VERSION 5.8 ;
BUSBITCHARS "[]" ;
DIVIDERCHAR "/" ;
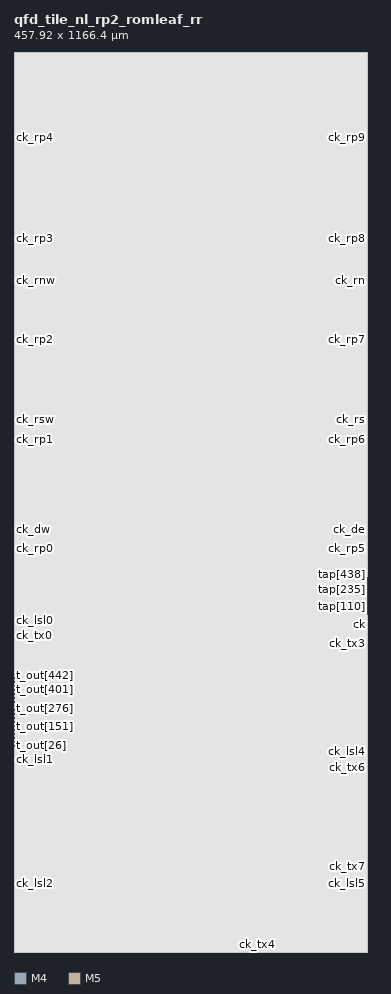
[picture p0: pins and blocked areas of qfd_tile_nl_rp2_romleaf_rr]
MACRO qfd_tile_nl_rp2_romleaf_rr
  CLASS BLOCK ;
  ORIGIN 0 0 ;
  FOREIGN qfd_tile_nl_rp2_romleaf_rr 0 0 ;
  SIZE 457.92 BY 1166.4 ;
  SYMMETRY X Y ;
  PIN t_out[0]
    DIRECTION OUTPUT ;
    USE SIGNAL ;
    PORT
      LAYER M4 ;
        RECT 0.000 262.752 0.192 262.776 ;
    END
  END t_out[0]
  PIN t_out[1]
    DIRECTION OUTPUT ;
    USE SIGNAL ;
    PORT
      LAYER M4 ;
        RECT 0.000 262.944 0.192 262.968 ;
    END
  END t_out[1]
  PIN t_out[2]
    DIRECTION OUTPUT ;
    USE SIGNAL ;
    PORT
      LAYER M4 ;
        RECT 0.000 263.136 0.192 263.160 ;
    END
  END t_out[2]
  PIN t_out[3]
    DIRECTION OUTPUT ;
    USE SIGNAL ;
    PORT
      LAYER M4 ;
        RECT 0.000 263.328 0.192 263.352 ;
    END
  END t_out[3]
  PIN t_out[4]
    DIRECTION OUTPUT ;
    USE SIGNAL ;
    PORT
      LAYER M4 ;
        RECT 0.000 263.520 0.192 263.544 ;
    END
  END t_out[4]
  PIN t_out[5]
    DIRECTION OUTPUT ;
    USE SIGNAL ;
    PORT
      LAYER M4 ;
        RECT 0.000 263.712 0.192 263.736 ;
    END
  END t_out[5]
  PIN t_out[6]
    DIRECTION OUTPUT ;
    USE SIGNAL ;
    PORT
      LAYER M4 ;
        RECT 0.000 263.904 0.192 263.928 ;
    END
  END t_out[6]
  PIN t_out[7]
    DIRECTION OUTPUT ;
    USE SIGNAL ;
    PORT
      LAYER M4 ;
        RECT 0.000 264.096 0.192 264.120 ;
    END
  END t_out[7]
  PIN t_out[8]
    DIRECTION OUTPUT ;
    USE SIGNAL ;
    PORT
      LAYER M4 ;
        RECT 0.000 264.288 0.192 264.312 ;
    END
  END t_out[8]
  PIN t_out[9]
    DIRECTION OUTPUT ;
    USE SIGNAL ;
    PORT
      LAYER M4 ;
        RECT 0.000 264.480 0.192 264.504 ;
    END
  END t_out[9]
  PIN t_out[10]
    DIRECTION OUTPUT ;
    USE SIGNAL ;
    PORT
      LAYER M4 ;
        RECT 0.000 264.672 0.192 264.696 ;
    END
  END t_out[10]
  PIN t_out[11]
    DIRECTION OUTPUT ;
    USE SIGNAL ;
    PORT
      LAYER M4 ;
        RECT 0.000 264.864 0.192 264.888 ;
    END
  END t_out[11]
  PIN t_out[12]
    DIRECTION OUTPUT ;
    USE SIGNAL ;
    PORT
      LAYER M4 ;
        RECT 0.000 265.056 0.192 265.080 ;
    END
  END t_out[12]
  PIN t_out[13]
    DIRECTION OUTPUT ;
    USE SIGNAL ;
    PORT
      LAYER M4 ;
        RECT 0.000 265.248 0.192 265.272 ;
    END
  END t_out[13]
  PIN t_out[14]
    DIRECTION OUTPUT ;
    USE SIGNAL ;
    PORT
      LAYER M4 ;
        RECT 0.000 265.440 0.192 265.464 ;
    END
  END t_out[14]
  PIN t_out[15]
    DIRECTION OUTPUT ;
    USE SIGNAL ;
    PORT
      LAYER M4 ;
        RECT 0.000 265.632 0.192 265.656 ;
    END
  END t_out[15]
  PIN t_out[16]
    DIRECTION OUTPUT ;
    USE SIGNAL ;
    PORT
      LAYER M4 ;
        RECT 0.000 265.824 0.192 265.848 ;
    END
  END t_out[16]
  PIN t_out[17]
    DIRECTION OUTPUT ;
    USE SIGNAL ;
    PORT
      LAYER M4 ;
        RECT 0.000 266.016 0.192 266.040 ;
    END
  END t_out[17]
  PIN t_out[18]
    DIRECTION OUTPUT ;
    USE SIGNAL ;
    PORT
      LAYER M4 ;
        RECT 0.000 266.208 0.192 266.232 ;
    END
  END t_out[18]
  PIN t_out[19]
    DIRECTION OUTPUT ;
    USE SIGNAL ;
    PORT
      LAYER M4 ;
        RECT 0.000 266.400 0.192 266.424 ;
    END
  END t_out[19]
  PIN t_out[20]
    DIRECTION OUTPUT ;
    USE SIGNAL ;
    PORT
      LAYER M4 ;
        RECT 0.000 266.592 0.192 266.616 ;
    END
  END t_out[20]
  PIN t_out[21]
    DIRECTION OUTPUT ;
    USE SIGNAL ;
    PORT
      LAYER M4 ;
        RECT 0.000 266.784 0.192 266.808 ;
    END
  END t_out[21]
  PIN t_out[22]
    DIRECTION OUTPUT ;
    USE SIGNAL ;
    PORT
      LAYER M4 ;
        RECT 0.000 266.976 0.192 267.000 ;
    END
  END t_out[22]
  PIN t_out[23]
    DIRECTION OUTPUT ;
    USE SIGNAL ;
    PORT
      LAYER M4 ;
        RECT 0.000 267.168 0.192 267.192 ;
    END
  END t_out[23]
  PIN t_out[24]
    DIRECTION OUTPUT ;
    USE SIGNAL ;
    PORT
      LAYER M4 ;
        RECT 0.000 267.360 0.192 267.384 ;
    END
  END t_out[24]
  PIN t_out[25]
    DIRECTION OUTPUT ;
    USE SIGNAL ;
    PORT
      LAYER M4 ;
        RECT 0.000 267.552 0.192 267.576 ;
    END
  END t_out[25]
  PIN t_out[26]
    DIRECTION OUTPUT ;
    USE SIGNAL ;
    PORT
      LAYER M4 ;
        RECT 0.000 267.744 0.192 267.768 ;
    END
  END t_out[26]
  PIN t_out[27]
    DIRECTION OUTPUT ;
    USE SIGNAL ;
    PORT
      LAYER M4 ;
        RECT 0.000 267.936 0.192 267.960 ;
    END
  END t_out[27]
  PIN t_out[28]
    DIRECTION OUTPUT ;
    USE SIGNAL ;
    PORT
      LAYER M4 ;
        RECT 0.000 268.128 0.192 268.152 ;
    END
  END t_out[28]
  PIN t_out[29]
    DIRECTION OUTPUT ;
    USE SIGNAL ;
    PORT
      LAYER M4 ;
        RECT 0.000 268.320 0.192 268.344 ;
    END
  END t_out[29]
  PIN t_out[30]
    DIRECTION OUTPUT ;
    USE SIGNAL ;
    PORT
      LAYER M4 ;
        RECT 0.000 268.512 0.192 268.536 ;
    END
  END t_out[30]
  PIN t_out[31]
    DIRECTION OUTPUT ;
    USE SIGNAL ;
    PORT
      LAYER M4 ;
        RECT 0.000 268.704 0.192 268.728 ;
    END
  END t_out[31]
  PIN t_out[32]
    DIRECTION OUTPUT ;
    USE SIGNAL ;
    PORT
      LAYER M4 ;
        RECT 0.000 268.896 0.192 268.920 ;
    END
  END t_out[32]
  PIN t_out[33]
    DIRECTION OUTPUT ;
    USE SIGNAL ;
    PORT
      LAYER M4 ;
        RECT 0.000 269.088 0.192 269.112 ;
    END
  END t_out[33]
  PIN t_out[34]
    DIRECTION OUTPUT ;
    USE SIGNAL ;
    PORT
      LAYER M4 ;
        RECT 0.000 269.280 0.192 269.304 ;
    END
  END t_out[34]
  PIN t_out[35]
    DIRECTION OUTPUT ;
    USE SIGNAL ;
    PORT
      LAYER M4 ;
        RECT 0.000 269.472 0.192 269.496 ;
    END
  END t_out[35]
  PIN t_out[36]
    DIRECTION OUTPUT ;
    USE SIGNAL ;
    PORT
      LAYER M4 ;
        RECT 0.000 269.664 0.192 269.688 ;
    END
  END t_out[36]
  PIN t_out[37]
    DIRECTION OUTPUT ;
    USE SIGNAL ;
    PORT
      LAYER M4 ;
        RECT 0.000 269.856 0.192 269.880 ;
    END
  END t_out[37]
  PIN t_out[38]
    DIRECTION OUTPUT ;
    USE SIGNAL ;
    PORT
      LAYER M4 ;
        RECT 0.000 270.048 0.192 270.072 ;
    END
  END t_out[38]
  PIN t_out[39]
    DIRECTION OUTPUT ;
    USE SIGNAL ;
    PORT
      LAYER M4 ;
        RECT 0.000 270.240 0.192 270.264 ;
    END
  END t_out[39]
  PIN t_out[40]
    DIRECTION OUTPUT ;
    USE SIGNAL ;
    PORT
      LAYER M4 ;
        RECT 0.000 270.432 0.192 270.456 ;
    END
  END t_out[40]
  PIN t_out[41]
    DIRECTION OUTPUT ;
    USE SIGNAL ;
    PORT
      LAYER M4 ;
        RECT 0.000 270.624 0.192 270.648 ;
    END
  END t_out[41]
  PIN t_out[42]
    DIRECTION OUTPUT ;
    USE SIGNAL ;
    PORT
      LAYER M4 ;
        RECT 0.000 270.816 0.192 270.840 ;
    END
  END t_out[42]
  PIN t_out[43]
    DIRECTION OUTPUT ;
    USE SIGNAL ;
    PORT
      LAYER M4 ;
        RECT 0.000 271.008 0.192 271.032 ;
    END
  END t_out[43]
  PIN t_out[44]
    DIRECTION OUTPUT ;
    USE SIGNAL ;
    PORT
      LAYER M4 ;
        RECT 0.000 271.200 0.192 271.224 ;
    END
  END t_out[44]
  PIN t_out[45]
    DIRECTION OUTPUT ;
    USE SIGNAL ;
    PORT
      LAYER M4 ;
        RECT 0.000 271.392 0.192 271.416 ;
    END
  END t_out[45]
  PIN t_out[46]
    DIRECTION OUTPUT ;
    USE SIGNAL ;
    PORT
      LAYER M4 ;
        RECT 0.000 271.584 0.192 271.608 ;
    END
  END t_out[46]
  PIN t_out[47]
    DIRECTION OUTPUT ;
    USE SIGNAL ;
    PORT
      LAYER M4 ;
        RECT 0.000 271.776 0.192 271.800 ;
    END
  END t_out[47]
  PIN t_out[48]
    DIRECTION OUTPUT ;
    USE SIGNAL ;
    PORT
      LAYER M4 ;
        RECT 0.000 271.968 0.192 271.992 ;
    END
  END t_out[48]
  PIN t_out[49]
    DIRECTION OUTPUT ;
    USE SIGNAL ;
    PORT
      LAYER M4 ;
        RECT 0.000 272.160 0.192 272.184 ;
    END
  END t_out[49]
  PIN t_out[50]
    DIRECTION OUTPUT ;
    USE SIGNAL ;
    PORT
      LAYER M4 ;
        RECT 0.000 272.352 0.192 272.376 ;
    END
  END t_out[50]
  PIN t_out[51]
    DIRECTION OUTPUT ;
    USE SIGNAL ;
    PORT
      LAYER M4 ;
        RECT 0.000 272.544 0.192 272.568 ;
    END
  END t_out[51]
  PIN t_out[52]
    DIRECTION OUTPUT ;
    USE SIGNAL ;
    PORT
      LAYER M4 ;
        RECT 0.000 272.736 0.192 272.760 ;
    END
  END t_out[52]
  PIN t_out[53]
    DIRECTION OUTPUT ;
    USE SIGNAL ;
    PORT
      LAYER M4 ;
        RECT 0.000 272.928 0.192 272.952 ;
    END
  END t_out[53]
  PIN t_out[54]
    DIRECTION OUTPUT ;
    USE SIGNAL ;
    PORT
      LAYER M4 ;
        RECT 0.000 273.120 0.192 273.144 ;
    END
  END t_out[54]
  PIN t_out[55]
    DIRECTION OUTPUT ;
    USE SIGNAL ;
    PORT
      LAYER M4 ;
        RECT 0.000 273.312 0.192 273.336 ;
    END
  END t_out[55]
  PIN t_out[56]
    DIRECTION OUTPUT ;
    USE SIGNAL ;
    PORT
      LAYER M4 ;
        RECT 0.000 273.504 0.192 273.528 ;
    END
  END t_out[56]
  PIN t_out[57]
    DIRECTION OUTPUT ;
    USE SIGNAL ;
    PORT
      LAYER M4 ;
        RECT 0.000 273.696 0.192 273.720 ;
    END
  END t_out[57]
  PIN t_out[58]
    DIRECTION OUTPUT ;
    USE SIGNAL ;
    PORT
      LAYER M4 ;
        RECT 0.000 273.888 0.192 273.912 ;
    END
  END t_out[58]
  PIN t_out[59]
    DIRECTION OUTPUT ;
    USE SIGNAL ;
    PORT
      LAYER M4 ;
        RECT 0.000 274.080 0.192 274.104 ;
    END
  END t_out[59]
  PIN t_out[60]
    DIRECTION OUTPUT ;
    USE SIGNAL ;
    PORT
      LAYER M4 ;
        RECT 0.000 274.272 0.192 274.296 ;
    END
  END t_out[60]
  PIN t_out[61]
    DIRECTION OUTPUT ;
    USE SIGNAL ;
    PORT
      LAYER M4 ;
        RECT 0.000 274.464 0.192 274.488 ;
    END
  END t_out[61]
  PIN t_out[62]
    DIRECTION OUTPUT ;
    USE SIGNAL ;
    PORT
      LAYER M4 ;
        RECT 0.000 274.656 0.192 274.680 ;
    END
  END t_out[62]
  PIN t_out[63]
    DIRECTION OUTPUT ;
    USE SIGNAL ;
    PORT
      LAYER M4 ;
        RECT 0.000 274.848 0.192 274.872 ;
    END
  END t_out[63]
  PIN t_out[64]
    DIRECTION OUTPUT ;
    USE SIGNAL ;
    PORT
      LAYER M4 ;
        RECT 0.000 275.040 0.192 275.064 ;
    END
  END t_out[64]
  PIN t_out[65]
    DIRECTION OUTPUT ;
    USE SIGNAL ;
    PORT
      LAYER M4 ;
        RECT 0.000 275.232 0.192 275.256 ;
    END
  END t_out[65]
  PIN t_out[66]
    DIRECTION OUTPUT ;
    USE SIGNAL ;
    PORT
      LAYER M4 ;
        RECT 0.000 275.424 0.192 275.448 ;
    END
  END t_out[66]
  PIN t_out[67]
    DIRECTION OUTPUT ;
    USE SIGNAL ;
    PORT
      LAYER M4 ;
        RECT 0.000 275.616 0.192 275.640 ;
    END
  END t_out[67]
  PIN t_out[68]
    DIRECTION OUTPUT ;
    USE SIGNAL ;
    PORT
      LAYER M4 ;
        RECT 0.000 275.808 0.192 275.832 ;
    END
  END t_out[68]
  PIN t_out[69]
    DIRECTION OUTPUT ;
    USE SIGNAL ;
    PORT
      LAYER M4 ;
        RECT 0.000 276.000 0.192 276.024 ;
    END
  END t_out[69]
  PIN t_out[70]
    DIRECTION OUTPUT ;
    USE SIGNAL ;
    PORT
      LAYER M4 ;
        RECT 0.000 276.192 0.192 276.216 ;
    END
  END t_out[70]
  PIN t_out[71]
    DIRECTION OUTPUT ;
    USE SIGNAL ;
    PORT
      LAYER M4 ;
        RECT 0.000 276.384 0.192 276.408 ;
    END
  END t_out[71]
  PIN t_out[72]
    DIRECTION OUTPUT ;
    USE SIGNAL ;
    PORT
      LAYER M4 ;
        RECT 0.000 276.576 0.192 276.600 ;
    END
  END t_out[72]
  PIN t_out[73]
    DIRECTION OUTPUT ;
    USE SIGNAL ;
    PORT
      LAYER M4 ;
        RECT 0.000 276.768 0.192 276.792 ;
    END
  END t_out[73]
  PIN t_out[74]
    DIRECTION OUTPUT ;
    USE SIGNAL ;
    PORT
      LAYER M4 ;
        RECT 0.000 276.960 0.192 276.984 ;
    END
  END t_out[74]
  PIN t_out[75]
    DIRECTION OUTPUT ;
    USE SIGNAL ;
    PORT
      LAYER M4 ;
        RECT 0.000 277.152 0.192 277.176 ;
    END
  END t_out[75]
  PIN t_out[76]
    DIRECTION OUTPUT ;
    USE SIGNAL ;
    PORT
      LAYER M4 ;
        RECT 0.000 277.344 0.192 277.368 ;
    END
  END t_out[76]
  PIN t_out[77]
    DIRECTION OUTPUT ;
    USE SIGNAL ;
    PORT
      LAYER M4 ;
        RECT 0.000 277.536 0.192 277.560 ;
    END
  END t_out[77]
  PIN t_out[78]
    DIRECTION OUTPUT ;
    USE SIGNAL ;
    PORT
      LAYER M4 ;
        RECT 0.000 277.728 0.192 277.752 ;
    END
  END t_out[78]
  PIN t_out[79]
    DIRECTION OUTPUT ;
    USE SIGNAL ;
    PORT
      LAYER M4 ;
        RECT 0.000 277.920 0.192 277.944 ;
    END
  END t_out[79]
  PIN t_out[80]
    DIRECTION OUTPUT ;
    USE SIGNAL ;
    PORT
      LAYER M4 ;
        RECT 0.000 278.112 0.192 278.136 ;
    END
  END t_out[80]
  PIN t_out[81]
    DIRECTION OUTPUT ;
    USE SIGNAL ;
    PORT
      LAYER M4 ;
        RECT 0.000 278.304 0.192 278.328 ;
    END
  END t_out[81]
  PIN t_out[82]
    DIRECTION OUTPUT ;
    USE SIGNAL ;
    PORT
      LAYER M4 ;
        RECT 0.000 278.496 0.192 278.520 ;
    END
  END t_out[82]
  PIN t_out[83]
    DIRECTION OUTPUT ;
    USE SIGNAL ;
    PORT
      LAYER M4 ;
        RECT 0.000 278.688 0.192 278.712 ;
    END
  END t_out[83]
  PIN t_out[84]
    DIRECTION OUTPUT ;
    USE SIGNAL ;
    PORT
      LAYER M4 ;
        RECT 0.000 278.880 0.192 278.904 ;
    END
  END t_out[84]
  PIN t_out[85]
    DIRECTION OUTPUT ;
    USE SIGNAL ;
    PORT
      LAYER M4 ;
        RECT 0.000 279.072 0.192 279.096 ;
    END
  END t_out[85]
  PIN t_out[86]
    DIRECTION OUTPUT ;
    USE SIGNAL ;
    PORT
      LAYER M4 ;
        RECT 0.000 279.264 0.192 279.288 ;
    END
  END t_out[86]
  PIN t_out[87]
    DIRECTION OUTPUT ;
    USE SIGNAL ;
    PORT
      LAYER M4 ;
        RECT 0.000 279.456 0.192 279.480 ;
    END
  END t_out[87]
  PIN t_out[88]
    DIRECTION OUTPUT ;
    USE SIGNAL ;
    PORT
      LAYER M4 ;
        RECT 0.000 279.648 0.192 279.672 ;
    END
  END t_out[88]
  PIN t_out[89]
    DIRECTION OUTPUT ;
    USE SIGNAL ;
    PORT
      LAYER M4 ;
        RECT 0.000 279.840 0.192 279.864 ;
    END
  END t_out[89]
  PIN t_out[90]
    DIRECTION OUTPUT ;
    USE SIGNAL ;
    PORT
      LAYER M4 ;
        RECT 0.000 280.032 0.192 280.056 ;
    END
  END t_out[90]
  PIN t_out[91]
    DIRECTION OUTPUT ;
    USE SIGNAL ;
    PORT
      LAYER M4 ;
        RECT 0.000 280.224 0.192 280.248 ;
    END
  END t_out[91]
  PIN t_out[92]
    DIRECTION OUTPUT ;
    USE SIGNAL ;
    PORT
      LAYER M4 ;
        RECT 0.000 280.416 0.192 280.440 ;
    END
  END t_out[92]
  PIN t_out[93]
    DIRECTION OUTPUT ;
    USE SIGNAL ;
    PORT
      LAYER M4 ;
        RECT 0.000 280.608 0.192 280.632 ;
    END
  END t_out[93]
  PIN t_out[94]
    DIRECTION OUTPUT ;
    USE SIGNAL ;
    PORT
      LAYER M4 ;
        RECT 0.000 280.800 0.192 280.824 ;
    END
  END t_out[94]
  PIN t_out[95]
    DIRECTION OUTPUT ;
    USE SIGNAL ;
    PORT
      LAYER M4 ;
        RECT 0.000 280.992 0.192 281.016 ;
    END
  END t_out[95]
  PIN t_out[96]
    DIRECTION OUTPUT ;
    USE SIGNAL ;
    PORT
      LAYER M4 ;
        RECT 0.000 281.184 0.192 281.208 ;
    END
  END t_out[96]
  PIN t_out[97]
    DIRECTION OUTPUT ;
    USE SIGNAL ;
    PORT
      LAYER M4 ;
        RECT 0.000 281.376 0.192 281.400 ;
    END
  END t_out[97]
  PIN t_out[98]
    DIRECTION OUTPUT ;
    USE SIGNAL ;
    PORT
      LAYER M4 ;
        RECT 0.000 281.568 0.192 281.592 ;
    END
  END t_out[98]
  PIN t_out[99]
    DIRECTION OUTPUT ;
    USE SIGNAL ;
    PORT
      LAYER M4 ;
        RECT 0.000 281.760 0.192 281.784 ;
    END
  END t_out[99]
  PIN t_out[100]
    DIRECTION OUTPUT ;
    USE SIGNAL ;
    PORT
      LAYER M4 ;
        RECT 0.000 281.952 0.192 281.976 ;
    END
  END t_out[100]
  PIN t_out[101]
    DIRECTION OUTPUT ;
    USE SIGNAL ;
    PORT
      LAYER M4 ;
        RECT 0.000 282.144 0.192 282.168 ;
    END
  END t_out[101]
  PIN t_out[102]
    DIRECTION OUTPUT ;
    USE SIGNAL ;
    PORT
      LAYER M4 ;
        RECT 0.000 282.336 0.192 282.360 ;
    END
  END t_out[102]
  PIN t_out[103]
    DIRECTION OUTPUT ;
    USE SIGNAL ;
    PORT
      LAYER M4 ;
        RECT 0.000 282.528 0.192 282.552 ;
    END
  END t_out[103]
  PIN t_out[104]
    DIRECTION OUTPUT ;
    USE SIGNAL ;
    PORT
      LAYER M4 ;
        RECT 0.000 282.720 0.192 282.744 ;
    END
  END t_out[104]
  PIN t_out[105]
    DIRECTION OUTPUT ;
    USE SIGNAL ;
    PORT
      LAYER M4 ;
        RECT 0.000 282.912 0.192 282.936 ;
    END
  END t_out[105]
  PIN t_out[106]
    DIRECTION OUTPUT ;
    USE SIGNAL ;
    PORT
      LAYER M4 ;
        RECT 0.000 283.104 0.192 283.128 ;
    END
  END t_out[106]
  PIN t_out[107]
    DIRECTION OUTPUT ;
    USE SIGNAL ;
    PORT
      LAYER M4 ;
        RECT 0.000 283.296 0.192 283.320 ;
    END
  END t_out[107]
  PIN t_out[108]
    DIRECTION OUTPUT ;
    USE SIGNAL ;
    PORT
      LAYER M4 ;
        RECT 0.000 283.488 0.192 283.512 ;
    END
  END t_out[108]
  PIN t_out[109]
    DIRECTION OUTPUT ;
    USE SIGNAL ;
    PORT
      LAYER M4 ;
        RECT 0.000 283.680 0.192 283.704 ;
    END
  END t_out[109]
  PIN t_out[110]
    DIRECTION OUTPUT ;
    USE SIGNAL ;
    PORT
      LAYER M4 ;
        RECT 0.000 283.872 0.192 283.896 ;
    END
  END t_out[110]
  PIN t_out[111]
    DIRECTION OUTPUT ;
    USE SIGNAL ;
    PORT
      LAYER M4 ;
        RECT 0.000 284.064 0.192 284.088 ;
    END
  END t_out[111]
  PIN t_out[112]
    DIRECTION OUTPUT ;
    USE SIGNAL ;
    PORT
      LAYER M4 ;
        RECT 0.000 284.256 0.192 284.280 ;
    END
  END t_out[112]
  PIN t_out[113]
    DIRECTION OUTPUT ;
    USE SIGNAL ;
    PORT
      LAYER M4 ;
        RECT 0.000 284.448 0.192 284.472 ;
    END
  END t_out[113]
  PIN t_out[114]
    DIRECTION OUTPUT ;
    USE SIGNAL ;
    PORT
      LAYER M4 ;
        RECT 0.000 284.640 0.192 284.664 ;
    END
  END t_out[114]
  PIN t_out[115]
    DIRECTION OUTPUT ;
    USE SIGNAL ;
    PORT
      LAYER M4 ;
        RECT 0.000 284.832 0.192 284.856 ;
    END
  END t_out[115]
  PIN t_out[116]
    DIRECTION OUTPUT ;
    USE SIGNAL ;
    PORT
      LAYER M4 ;
        RECT 0.000 285.024 0.192 285.048 ;
    END
  END t_out[116]
  PIN t_out[117]
    DIRECTION OUTPUT ;
    USE SIGNAL ;
    PORT
      LAYER M4 ;
        RECT 0.000 285.216 0.192 285.240 ;
    END
  END t_out[117]
  PIN t_out[118]
    DIRECTION OUTPUT ;
    USE SIGNAL ;
    PORT
      LAYER M4 ;
        RECT 0.000 285.408 0.192 285.432 ;
    END
  END t_out[118]
  PIN t_out[119]
    DIRECTION OUTPUT ;
    USE SIGNAL ;
    PORT
      LAYER M4 ;
        RECT 0.000 285.600 0.192 285.624 ;
    END
  END t_out[119]
  PIN t_out[120]
    DIRECTION OUTPUT ;
    USE SIGNAL ;
    PORT
      LAYER M4 ;
        RECT 0.000 285.792 0.192 285.816 ;
    END
  END t_out[120]
  PIN t_out[121]
    DIRECTION OUTPUT ;
    USE SIGNAL ;
    PORT
      LAYER M4 ;
        RECT 0.000 285.984 0.192 286.008 ;
    END
  END t_out[121]
  PIN t_out[122]
    DIRECTION OUTPUT ;
    USE SIGNAL ;
    PORT
      LAYER M4 ;
        RECT 0.000 286.176 0.192 286.200 ;
    END
  END t_out[122]
  PIN t_out[123]
    DIRECTION OUTPUT ;
    USE SIGNAL ;
    PORT
      LAYER M4 ;
        RECT 0.000 286.368 0.192 286.392 ;
    END
  END t_out[123]
  PIN t_out[124]
    DIRECTION OUTPUT ;
    USE SIGNAL ;
    PORT
      LAYER M4 ;
        RECT 0.000 286.560 0.192 286.584 ;
    END
  END t_out[124]
  PIN t_out[125]
    DIRECTION OUTPUT ;
    USE SIGNAL ;
    PORT
      LAYER M4 ;
        RECT 0.000 286.752 0.192 286.776 ;
    END
  END t_out[125]
  PIN t_out[126]
    DIRECTION OUTPUT ;
    USE SIGNAL ;
    PORT
      LAYER M4 ;
        RECT 0.000 286.944 0.192 286.968 ;
    END
  END t_out[126]
  PIN t_out[127]
    DIRECTION OUTPUT ;
    USE SIGNAL ;
    PORT
      LAYER M4 ;
        RECT 0.000 287.136 0.192 287.160 ;
    END
  END t_out[127]
  PIN t_out[128]
    DIRECTION OUTPUT ;
    USE SIGNAL ;
    PORT
      LAYER M4 ;
        RECT 0.000 287.328 0.192 287.352 ;
    END
  END t_out[128]
  PIN t_out[129]
    DIRECTION OUTPUT ;
    USE SIGNAL ;
    PORT
      LAYER M4 ;
        RECT 0.000 287.520 0.192 287.544 ;
    END
  END t_out[129]
  PIN t_out[130]
    DIRECTION OUTPUT ;
    USE SIGNAL ;
    PORT
      LAYER M4 ;
        RECT 0.000 287.712 0.192 287.736 ;
    END
  END t_out[130]
  PIN t_out[131]
    DIRECTION OUTPUT ;
    USE SIGNAL ;
    PORT
      LAYER M4 ;
        RECT 0.000 287.904 0.192 287.928 ;
    END
  END t_out[131]
  PIN t_out[132]
    DIRECTION OUTPUT ;
    USE SIGNAL ;
    PORT
      LAYER M4 ;
        RECT 0.000 288.096 0.192 288.120 ;
    END
  END t_out[132]
  PIN t_out[133]
    DIRECTION OUTPUT ;
    USE SIGNAL ;
    PORT
      LAYER M4 ;
        RECT 0.000 288.288 0.192 288.312 ;
    END
  END t_out[133]
  PIN t_out[134]
    DIRECTION OUTPUT ;
    USE SIGNAL ;
    PORT
      LAYER M4 ;
        RECT 0.000 288.480 0.192 288.504 ;
    END
  END t_out[134]
  PIN t_out[135]
    DIRECTION OUTPUT ;
    USE SIGNAL ;
    PORT
      LAYER M4 ;
        RECT 0.000 288.672 0.192 288.696 ;
    END
  END t_out[135]
  PIN t_out[136]
    DIRECTION OUTPUT ;
    USE SIGNAL ;
    PORT
      LAYER M4 ;
        RECT 0.000 288.864 0.192 288.888 ;
    END
  END t_out[136]
  PIN t_out[137]
    DIRECTION OUTPUT ;
    USE SIGNAL ;
    PORT
      LAYER M4 ;
        RECT 0.000 289.056 0.192 289.080 ;
    END
  END t_out[137]
  PIN t_out[138]
    DIRECTION OUTPUT ;
    USE SIGNAL ;
    PORT
      LAYER M4 ;
        RECT 0.000 289.248 0.192 289.272 ;
    END
  END t_out[138]
  PIN t_out[139]
    DIRECTION OUTPUT ;
    USE SIGNAL ;
    PORT
      LAYER M4 ;
        RECT 0.000 289.440 0.192 289.464 ;
    END
  END t_out[139]
  PIN t_out[140]
    DIRECTION OUTPUT ;
    USE SIGNAL ;
    PORT
      LAYER M4 ;
        RECT 0.000 289.632 0.192 289.656 ;
    END
  END t_out[140]
  PIN t_out[141]
    DIRECTION OUTPUT ;
    USE SIGNAL ;
    PORT
      LAYER M4 ;
        RECT 0.000 289.824 0.192 289.848 ;
    END
  END t_out[141]
  PIN t_out[142]
    DIRECTION OUTPUT ;
    USE SIGNAL ;
    PORT
      LAYER M4 ;
        RECT 0.000 290.016 0.192 290.040 ;
    END
  END t_out[142]
  PIN t_out[143]
    DIRECTION OUTPUT ;
    USE SIGNAL ;
    PORT
      LAYER M4 ;
        RECT 0.000 290.208 0.192 290.232 ;
    END
  END t_out[143]
  PIN t_out[144]
    DIRECTION OUTPUT ;
    USE SIGNAL ;
    PORT
      LAYER M4 ;
        RECT 0.000 290.400 0.192 290.424 ;
    END
  END t_out[144]
  PIN t_out[145]
    DIRECTION OUTPUT ;
    USE SIGNAL ;
    PORT
      LAYER M4 ;
        RECT 0.000 290.592 0.192 290.616 ;
    END
  END t_out[145]
  PIN t_out[146]
    DIRECTION OUTPUT ;
    USE SIGNAL ;
    PORT
      LAYER M4 ;
        RECT 0.000 290.784 0.192 290.808 ;
    END
  END t_out[146]
  PIN t_out[147]
    DIRECTION OUTPUT ;
    USE SIGNAL ;
    PORT
      LAYER M4 ;
        RECT 0.000 290.976 0.192 291.000 ;
    END
  END t_out[147]
  PIN t_out[148]
    DIRECTION OUTPUT ;
    USE SIGNAL ;
    PORT
      LAYER M4 ;
        RECT 0.000 291.168 0.192 291.192 ;
    END
  END t_out[148]
  PIN t_out[149]
    DIRECTION OUTPUT ;
    USE SIGNAL ;
    PORT
      LAYER M4 ;
        RECT 0.000 291.360 0.192 291.384 ;
    END
  END t_out[149]
  PIN t_out[150]
    DIRECTION OUTPUT ;
    USE SIGNAL ;
    PORT
      LAYER M4 ;
        RECT 0.000 291.552 0.192 291.576 ;
    END
  END t_out[150]
  PIN t_out[151]
    DIRECTION OUTPUT ;
    USE SIGNAL ;
    PORT
      LAYER M4 ;
        RECT 0.000 291.744 0.192 291.768 ;
    END
  END t_out[151]
  PIN t_out[152]
    DIRECTION OUTPUT ;
    USE SIGNAL ;
    PORT
      LAYER M4 ;
        RECT 0.000 291.936 0.192 291.960 ;
    END
  END t_out[152]
  PIN t_out[153]
    DIRECTION OUTPUT ;
    USE SIGNAL ;
    PORT
      LAYER M4 ;
        RECT 0.000 292.128 0.192 292.152 ;
    END
  END t_out[153]
  PIN t_out[154]
    DIRECTION OUTPUT ;
    USE SIGNAL ;
    PORT
      LAYER M4 ;
        RECT 0.000 292.320 0.192 292.344 ;
    END
  END t_out[154]
  PIN t_out[155]
    DIRECTION OUTPUT ;
    USE SIGNAL ;
    PORT
      LAYER M4 ;
        RECT 0.000 292.512 0.192 292.536 ;
    END
  END t_out[155]
  PIN t_out[156]
    DIRECTION OUTPUT ;
    USE SIGNAL ;
    PORT
      LAYER M4 ;
        RECT 0.000 292.704 0.192 292.728 ;
    END
  END t_out[156]
  PIN t_out[157]
    DIRECTION OUTPUT ;
    USE SIGNAL ;
    PORT
      LAYER M4 ;
        RECT 0.000 292.896 0.192 292.920 ;
    END
  END t_out[157]
  PIN t_out[158]
    DIRECTION OUTPUT ;
    USE SIGNAL ;
    PORT
      LAYER M4 ;
        RECT 0.000 293.088 0.192 293.112 ;
    END
  END t_out[158]
  PIN t_out[159]
    DIRECTION OUTPUT ;
    USE SIGNAL ;
    PORT
      LAYER M4 ;
        RECT 0.000 293.280 0.192 293.304 ;
    END
  END t_out[159]
  PIN t_out[160]
    DIRECTION OUTPUT ;
    USE SIGNAL ;
    PORT
      LAYER M4 ;
        RECT 0.000 293.472 0.192 293.496 ;
    END
  END t_out[160]
  PIN t_out[161]
    DIRECTION OUTPUT ;
    USE SIGNAL ;
    PORT
      LAYER M4 ;
        RECT 0.000 293.664 0.192 293.688 ;
    END
  END t_out[161]
  PIN t_out[162]
    DIRECTION OUTPUT ;
    USE SIGNAL ;
    PORT
      LAYER M4 ;
        RECT 0.000 293.856 0.192 293.880 ;
    END
  END t_out[162]
  PIN t_out[163]
    DIRECTION OUTPUT ;
    USE SIGNAL ;
    PORT
      LAYER M4 ;
        RECT 0.000 294.048 0.192 294.072 ;
    END
  END t_out[163]
  PIN t_out[164]
    DIRECTION OUTPUT ;
    USE SIGNAL ;
    PORT
      LAYER M4 ;
        RECT 0.000 294.240 0.192 294.264 ;
    END
  END t_out[164]
  PIN t_out[165]
    DIRECTION OUTPUT ;
    USE SIGNAL ;
    PORT
      LAYER M4 ;
        RECT 0.000 294.432 0.192 294.456 ;
    END
  END t_out[165]
  PIN t_out[166]
    DIRECTION OUTPUT ;
    USE SIGNAL ;
    PORT
      LAYER M4 ;
        RECT 0.000 294.624 0.192 294.648 ;
    END
  END t_out[166]
  PIN t_out[167]
    DIRECTION OUTPUT ;
    USE SIGNAL ;
    PORT
      LAYER M4 ;
        RECT 0.000 294.816 0.192 294.840 ;
    END
  END t_out[167]
  PIN t_out[168]
    DIRECTION OUTPUT ;
    USE SIGNAL ;
    PORT
      LAYER M4 ;
        RECT 0.000 295.008 0.192 295.032 ;
    END
  END t_out[168]
  PIN t_out[169]
    DIRECTION OUTPUT ;
    USE SIGNAL ;
    PORT
      LAYER M4 ;
        RECT 0.000 295.200 0.192 295.224 ;
    END
  END t_out[169]
  PIN t_out[170]
    DIRECTION OUTPUT ;
    USE SIGNAL ;
    PORT
      LAYER M4 ;
        RECT 0.000 295.392 0.192 295.416 ;
    END
  END t_out[170]
  PIN t_out[171]
    DIRECTION OUTPUT ;
    USE SIGNAL ;
    PORT
      LAYER M4 ;
        RECT 0.000 295.584 0.192 295.608 ;
    END
  END t_out[171]
  PIN t_out[172]
    DIRECTION OUTPUT ;
    USE SIGNAL ;
    PORT
      LAYER M4 ;
        RECT 0.000 295.776 0.192 295.800 ;
    END
  END t_out[172]
  PIN t_out[173]
    DIRECTION OUTPUT ;
    USE SIGNAL ;
    PORT
      LAYER M4 ;
        RECT 0.000 295.968 0.192 295.992 ;
    END
  END t_out[173]
  PIN t_out[174]
    DIRECTION OUTPUT ;
    USE SIGNAL ;
    PORT
      LAYER M4 ;
        RECT 0.000 296.160 0.192 296.184 ;
    END
  END t_out[174]
  PIN t_out[175]
    DIRECTION OUTPUT ;
    USE SIGNAL ;
    PORT
      LAYER M4 ;
        RECT 0.000 296.352 0.192 296.376 ;
    END
  END t_out[175]
  PIN t_out[176]
    DIRECTION OUTPUT ;
    USE SIGNAL ;
    PORT
      LAYER M4 ;
        RECT 0.000 296.544 0.192 296.568 ;
    END
  END t_out[176]
  PIN t_out[177]
    DIRECTION OUTPUT ;
    USE SIGNAL ;
    PORT
      LAYER M4 ;
        RECT 0.000 296.736 0.192 296.760 ;
    END
  END t_out[177]
  PIN t_out[178]
    DIRECTION OUTPUT ;
    USE SIGNAL ;
    PORT
      LAYER M4 ;
        RECT 0.000 296.928 0.192 296.952 ;
    END
  END t_out[178]
  PIN t_out[179]
    DIRECTION OUTPUT ;
    USE SIGNAL ;
    PORT
      LAYER M4 ;
        RECT 0.000 297.120 0.192 297.144 ;
    END
  END t_out[179]
  PIN t_out[180]
    DIRECTION OUTPUT ;
    USE SIGNAL ;
    PORT
      LAYER M4 ;
        RECT 0.000 297.312 0.192 297.336 ;
    END
  END t_out[180]
  PIN t_out[181]
    DIRECTION OUTPUT ;
    USE SIGNAL ;
    PORT
      LAYER M4 ;
        RECT 0.000 297.504 0.192 297.528 ;
    END
  END t_out[181]
  PIN t_out[182]
    DIRECTION OUTPUT ;
    USE SIGNAL ;
    PORT
      LAYER M4 ;
        RECT 0.000 297.696 0.192 297.720 ;
    END
  END t_out[182]
  PIN t_out[183]
    DIRECTION OUTPUT ;
    USE SIGNAL ;
    PORT
      LAYER M4 ;
        RECT 0.000 297.888 0.192 297.912 ;
    END
  END t_out[183]
  PIN t_out[184]
    DIRECTION OUTPUT ;
    USE SIGNAL ;
    PORT
      LAYER M4 ;
        RECT 0.000 298.080 0.192 298.104 ;
    END
  END t_out[184]
  PIN t_out[185]
    DIRECTION OUTPUT ;
    USE SIGNAL ;
    PORT
      LAYER M4 ;
        RECT 0.000 298.272 0.192 298.296 ;
    END
  END t_out[185]
  PIN t_out[186]
    DIRECTION OUTPUT ;
    USE SIGNAL ;
    PORT
      LAYER M4 ;
        RECT 0.000 298.464 0.192 298.488 ;
    END
  END t_out[186]
  PIN t_out[187]
    DIRECTION OUTPUT ;
    USE SIGNAL ;
    PORT
      LAYER M4 ;
        RECT 0.000 298.656 0.192 298.680 ;
    END
  END t_out[187]
  PIN t_out[188]
    DIRECTION OUTPUT ;
    USE SIGNAL ;
    PORT
      LAYER M4 ;
        RECT 0.000 298.848 0.192 298.872 ;
    END
  END t_out[188]
  PIN t_out[189]
    DIRECTION OUTPUT ;
    USE SIGNAL ;
    PORT
      LAYER M4 ;
        RECT 0.000 299.040 0.192 299.064 ;
    END
  END t_out[189]
  PIN t_out[190]
    DIRECTION OUTPUT ;
    USE SIGNAL ;
    PORT
      LAYER M4 ;
        RECT 0.000 299.232 0.192 299.256 ;
    END
  END t_out[190]
  PIN t_out[191]
    DIRECTION OUTPUT ;
    USE SIGNAL ;
    PORT
      LAYER M4 ;
        RECT 0.000 299.424 0.192 299.448 ;
    END
  END t_out[191]
  PIN t_out[192]
    DIRECTION OUTPUT ;
    USE SIGNAL ;
    PORT
      LAYER M4 ;
        RECT 0.000 299.616 0.192 299.640 ;
    END
  END t_out[192]
  PIN t_out[193]
    DIRECTION OUTPUT ;
    USE SIGNAL ;
    PORT
      LAYER M4 ;
        RECT 0.000 299.808 0.192 299.832 ;
    END
  END t_out[193]
  PIN t_out[194]
    DIRECTION OUTPUT ;
    USE SIGNAL ;
    PORT
      LAYER M4 ;
        RECT 0.000 300.000 0.192 300.024 ;
    END
  END t_out[194]
  PIN t_out[195]
    DIRECTION OUTPUT ;
    USE SIGNAL ;
    PORT
      LAYER M4 ;
        RECT 0.000 300.192 0.192 300.216 ;
    END
  END t_out[195]
  PIN t_out[196]
    DIRECTION OUTPUT ;
    USE SIGNAL ;
    PORT
      LAYER M4 ;
        RECT 0.000 300.384 0.192 300.408 ;
    END
  END t_out[196]
  PIN t_out[197]
    DIRECTION OUTPUT ;
    USE SIGNAL ;
    PORT
      LAYER M4 ;
        RECT 0.000 300.576 0.192 300.600 ;
    END
  END t_out[197]
  PIN t_out[198]
    DIRECTION OUTPUT ;
    USE SIGNAL ;
    PORT
      LAYER M4 ;
        RECT 0.000 300.768 0.192 300.792 ;
    END
  END t_out[198]
  PIN t_out[199]
    DIRECTION OUTPUT ;
    USE SIGNAL ;
    PORT
      LAYER M4 ;
        RECT 0.000 300.960 0.192 300.984 ;
    END
  END t_out[199]
  PIN t_out[200]
    DIRECTION OUTPUT ;
    USE SIGNAL ;
    PORT
      LAYER M4 ;
        RECT 0.000 301.152 0.192 301.176 ;
    END
  END t_out[200]
  PIN t_out[201]
    DIRECTION OUTPUT ;
    USE SIGNAL ;
    PORT
      LAYER M4 ;
        RECT 0.000 301.344 0.192 301.368 ;
    END
  END t_out[201]
  PIN t_out[202]
    DIRECTION OUTPUT ;
    USE SIGNAL ;
    PORT
      LAYER M4 ;
        RECT 0.000 301.536 0.192 301.560 ;
    END
  END t_out[202]
  PIN t_out[203]
    DIRECTION OUTPUT ;
    USE SIGNAL ;
    PORT
      LAYER M4 ;
        RECT 0.000 301.728 0.192 301.752 ;
    END
  END t_out[203]
  PIN t_out[204]
    DIRECTION OUTPUT ;
    USE SIGNAL ;
    PORT
      LAYER M4 ;
        RECT 0.000 301.920 0.192 301.944 ;
    END
  END t_out[204]
  PIN t_out[205]
    DIRECTION OUTPUT ;
    USE SIGNAL ;
    PORT
      LAYER M4 ;
        RECT 0.000 302.112 0.192 302.136 ;
    END
  END t_out[205]
  PIN t_out[206]
    DIRECTION OUTPUT ;
    USE SIGNAL ;
    PORT
      LAYER M4 ;
        RECT 0.000 302.304 0.192 302.328 ;
    END
  END t_out[206]
  PIN t_out[207]
    DIRECTION OUTPUT ;
    USE SIGNAL ;
    PORT
      LAYER M4 ;
        RECT 0.000 302.496 0.192 302.520 ;
    END
  END t_out[207]
  PIN t_out[208]
    DIRECTION OUTPUT ;
    USE SIGNAL ;
    PORT
      LAYER M4 ;
        RECT 0.000 302.688 0.192 302.712 ;
    END
  END t_out[208]
  PIN t_out[209]
    DIRECTION OUTPUT ;
    USE SIGNAL ;
    PORT
      LAYER M4 ;
        RECT 0.000 302.880 0.192 302.904 ;
    END
  END t_out[209]
  PIN t_out[210]
    DIRECTION OUTPUT ;
    USE SIGNAL ;
    PORT
      LAYER M4 ;
        RECT 0.000 303.072 0.192 303.096 ;
    END
  END t_out[210]
  PIN t_out[211]
    DIRECTION OUTPUT ;
    USE SIGNAL ;
    PORT
      LAYER M4 ;
        RECT 0.000 303.264 0.192 303.288 ;
    END
  END t_out[211]
  PIN t_out[212]
    DIRECTION OUTPUT ;
    USE SIGNAL ;
    PORT
      LAYER M4 ;
        RECT 0.000 303.456 0.192 303.480 ;
    END
  END t_out[212]
  PIN t_out[213]
    DIRECTION OUTPUT ;
    USE SIGNAL ;
    PORT
      LAYER M4 ;
        RECT 0.000 303.648 0.192 303.672 ;
    END
  END t_out[213]
  PIN t_out[214]
    DIRECTION OUTPUT ;
    USE SIGNAL ;
    PORT
      LAYER M4 ;
        RECT 0.000 303.840 0.192 303.864 ;
    END
  END t_out[214]
  PIN t_out[215]
    DIRECTION OUTPUT ;
    USE SIGNAL ;
    PORT
      LAYER M4 ;
        RECT 0.000 304.032 0.192 304.056 ;
    END
  END t_out[215]
  PIN t_out[216]
    DIRECTION OUTPUT ;
    USE SIGNAL ;
    PORT
      LAYER M4 ;
        RECT 0.000 304.224 0.192 304.248 ;
    END
  END t_out[216]
  PIN t_out[217]
    DIRECTION OUTPUT ;
    USE SIGNAL ;
    PORT
      LAYER M4 ;
        RECT 0.000 304.416 0.192 304.440 ;
    END
  END t_out[217]
  PIN t_out[218]
    DIRECTION OUTPUT ;
    USE SIGNAL ;
    PORT
      LAYER M4 ;
        RECT 0.000 304.608 0.192 304.632 ;
    END
  END t_out[218]
  PIN t_out[219]
    DIRECTION OUTPUT ;
    USE SIGNAL ;
    PORT
      LAYER M4 ;
        RECT 0.000 304.800 0.192 304.824 ;
    END
  END t_out[219]
  PIN t_out[220]
    DIRECTION OUTPUT ;
    USE SIGNAL ;
    PORT
      LAYER M4 ;
        RECT 0.000 304.992 0.192 305.016 ;
    END
  END t_out[220]
  PIN t_out[221]
    DIRECTION OUTPUT ;
    USE SIGNAL ;
    PORT
      LAYER M4 ;
        RECT 0.000 305.184 0.192 305.208 ;
    END
  END t_out[221]
  PIN t_out[222]
    DIRECTION OUTPUT ;
    USE SIGNAL ;
    PORT
      LAYER M4 ;
        RECT 0.000 305.376 0.192 305.400 ;
    END
  END t_out[222]
  PIN t_out[223]
    DIRECTION OUTPUT ;
    USE SIGNAL ;
    PORT
      LAYER M4 ;
        RECT 0.000 305.568 0.192 305.592 ;
    END
  END t_out[223]
  PIN t_out[224]
    DIRECTION OUTPUT ;
    USE SIGNAL ;
    PORT
      LAYER M4 ;
        RECT 0.000 305.760 0.192 305.784 ;
    END
  END t_out[224]
  PIN t_out[225]
    DIRECTION OUTPUT ;
    USE SIGNAL ;
    PORT
      LAYER M4 ;
        RECT 0.000 305.952 0.192 305.976 ;
    END
  END t_out[225]
  PIN t_out[226]
    DIRECTION OUTPUT ;
    USE SIGNAL ;
    PORT
      LAYER M4 ;
        RECT 0.000 306.144 0.192 306.168 ;
    END
  END t_out[226]
  PIN t_out[227]
    DIRECTION OUTPUT ;
    USE SIGNAL ;
    PORT
      LAYER M4 ;
        RECT 0.000 306.336 0.192 306.360 ;
    END
  END t_out[227]
  PIN t_out[228]
    DIRECTION OUTPUT ;
    USE SIGNAL ;
    PORT
      LAYER M4 ;
        RECT 0.000 306.528 0.192 306.552 ;
    END
  END t_out[228]
  PIN t_out[229]
    DIRECTION OUTPUT ;
    USE SIGNAL ;
    PORT
      LAYER M4 ;
        RECT 0.000 306.720 0.192 306.744 ;
    END
  END t_out[229]
  PIN t_out[230]
    DIRECTION OUTPUT ;
    USE SIGNAL ;
    PORT
      LAYER M4 ;
        RECT 0.000 306.912 0.192 306.936 ;
    END
  END t_out[230]
  PIN t_out[231]
    DIRECTION OUTPUT ;
    USE SIGNAL ;
    PORT
      LAYER M4 ;
        RECT 0.000 307.104 0.192 307.128 ;
    END
  END t_out[231]
  PIN t_out[232]
    DIRECTION OUTPUT ;
    USE SIGNAL ;
    PORT
      LAYER M4 ;
        RECT 0.000 307.296 0.192 307.320 ;
    END
  END t_out[232]
  PIN t_out[233]
    DIRECTION OUTPUT ;
    USE SIGNAL ;
    PORT
      LAYER M4 ;
        RECT 0.000 307.488 0.192 307.512 ;
    END
  END t_out[233]
  PIN t_out[234]
    DIRECTION OUTPUT ;
    USE SIGNAL ;
    PORT
      LAYER M4 ;
        RECT 0.000 307.680 0.192 307.704 ;
    END
  END t_out[234]
  PIN t_out[235]
    DIRECTION OUTPUT ;
    USE SIGNAL ;
    PORT
      LAYER M4 ;
        RECT 0.000 307.872 0.192 307.896 ;
    END
  END t_out[235]
  PIN t_out[236]
    DIRECTION OUTPUT ;
    USE SIGNAL ;
    PORT
      LAYER M4 ;
        RECT 0.000 308.064 0.192 308.088 ;
    END
  END t_out[236]
  PIN t_out[237]
    DIRECTION OUTPUT ;
    USE SIGNAL ;
    PORT
      LAYER M4 ;
        RECT 0.000 308.256 0.192 308.280 ;
    END
  END t_out[237]
  PIN t_out[238]
    DIRECTION OUTPUT ;
    USE SIGNAL ;
    PORT
      LAYER M4 ;
        RECT 0.000 308.448 0.192 308.472 ;
    END
  END t_out[238]
  PIN t_out[239]
    DIRECTION OUTPUT ;
    USE SIGNAL ;
    PORT
      LAYER M4 ;
        RECT 0.000 308.640 0.192 308.664 ;
    END
  END t_out[239]
  PIN t_out[240]
    DIRECTION OUTPUT ;
    USE SIGNAL ;
    PORT
      LAYER M4 ;
        RECT 0.000 308.832 0.192 308.856 ;
    END
  END t_out[240]
  PIN t_out[241]
    DIRECTION OUTPUT ;
    USE SIGNAL ;
    PORT
      LAYER M4 ;
        RECT 0.000 309.024 0.192 309.048 ;
    END
  END t_out[241]
  PIN t_out[242]
    DIRECTION OUTPUT ;
    USE SIGNAL ;
    PORT
      LAYER M4 ;
        RECT 0.000 309.216 0.192 309.240 ;
    END
  END t_out[242]
  PIN t_out[243]
    DIRECTION OUTPUT ;
    USE SIGNAL ;
    PORT
      LAYER M4 ;
        RECT 0.000 309.408 0.192 309.432 ;
    END
  END t_out[243]
  PIN t_out[244]
    DIRECTION OUTPUT ;
    USE SIGNAL ;
    PORT
      LAYER M4 ;
        RECT 0.000 309.600 0.192 309.624 ;
    END
  END t_out[244]
  PIN t_out[245]
    DIRECTION OUTPUT ;
    USE SIGNAL ;
    PORT
      LAYER M4 ;
        RECT 0.000 309.792 0.192 309.816 ;
    END
  END t_out[245]
  PIN t_out[246]
    DIRECTION OUTPUT ;
    USE SIGNAL ;
    PORT
      LAYER M4 ;
        RECT 0.000 309.984 0.192 310.008 ;
    END
  END t_out[246]
  PIN t_out[247]
    DIRECTION OUTPUT ;
    USE SIGNAL ;
    PORT
      LAYER M4 ;
        RECT 0.000 310.176 0.192 310.200 ;
    END
  END t_out[247]
  PIN t_out[248]
    DIRECTION OUTPUT ;
    USE SIGNAL ;
    PORT
      LAYER M4 ;
        RECT 0.000 310.368 0.192 310.392 ;
    END
  END t_out[248]
  PIN t_out[249]
    DIRECTION OUTPUT ;
    USE SIGNAL ;
    PORT
      LAYER M4 ;
        RECT 0.000 310.560 0.192 310.584 ;
    END
  END t_out[249]
  PIN t_out[250]
    DIRECTION OUTPUT ;
    USE SIGNAL ;
    PORT
      LAYER M4 ;
        RECT 0.000 310.752 0.192 310.776 ;
    END
  END t_out[250]
  PIN t_out[251]
    DIRECTION OUTPUT ;
    USE SIGNAL ;
    PORT
      LAYER M4 ;
        RECT 0.000 310.944 0.192 310.968 ;
    END
  END t_out[251]
  PIN t_out[252]
    DIRECTION OUTPUT ;
    USE SIGNAL ;
    PORT
      LAYER M4 ;
        RECT 0.000 311.136 0.192 311.160 ;
    END
  END t_out[252]
  PIN t_out[253]
    DIRECTION OUTPUT ;
    USE SIGNAL ;
    PORT
      LAYER M4 ;
        RECT 0.000 311.328 0.192 311.352 ;
    END
  END t_out[253]
  PIN t_out[254]
    DIRECTION OUTPUT ;
    USE SIGNAL ;
    PORT
      LAYER M4 ;
        RECT 0.000 311.520 0.192 311.544 ;
    END
  END t_out[254]
  PIN t_out[255]
    DIRECTION OUTPUT ;
    USE SIGNAL ;
    PORT
      LAYER M4 ;
        RECT 0.000 311.712 0.192 311.736 ;
    END
  END t_out[255]
  PIN t_out[256]
    DIRECTION OUTPUT ;
    USE SIGNAL ;
    PORT
      LAYER M4 ;
        RECT 0.000 311.904 0.192 311.928 ;
    END
  END t_out[256]
  PIN t_out[257]
    DIRECTION OUTPUT ;
    USE SIGNAL ;
    PORT
      LAYER M4 ;
        RECT 0.000 312.096 0.192 312.120 ;
    END
  END t_out[257]
  PIN t_out[258]
    DIRECTION OUTPUT ;
    USE SIGNAL ;
    PORT
      LAYER M4 ;
        RECT 0.000 312.288 0.192 312.312 ;
    END
  END t_out[258]
  PIN t_out[259]
    DIRECTION OUTPUT ;
    USE SIGNAL ;
    PORT
      LAYER M4 ;
        RECT 0.000 312.480 0.192 312.504 ;
    END
  END t_out[259]
  PIN t_out[260]
    DIRECTION OUTPUT ;
    USE SIGNAL ;
    PORT
      LAYER M4 ;
        RECT 0.000 312.672 0.192 312.696 ;
    END
  END t_out[260]
  PIN t_out[261]
    DIRECTION OUTPUT ;
    USE SIGNAL ;
    PORT
      LAYER M4 ;
        RECT 0.000 312.864 0.192 312.888 ;
    END
  END t_out[261]
  PIN t_out[262]
    DIRECTION OUTPUT ;
    USE SIGNAL ;
    PORT
      LAYER M4 ;
        RECT 0.000 313.056 0.192 313.080 ;
    END
  END t_out[262]
  PIN t_out[263]
    DIRECTION OUTPUT ;
    USE SIGNAL ;
    PORT
      LAYER M4 ;
        RECT 0.000 313.248 0.192 313.272 ;
    END
  END t_out[263]
  PIN t_out[264]
    DIRECTION OUTPUT ;
    USE SIGNAL ;
    PORT
      LAYER M4 ;
        RECT 0.000 313.440 0.192 313.464 ;
    END
  END t_out[264]
  PIN t_out[265]
    DIRECTION OUTPUT ;
    USE SIGNAL ;
    PORT
      LAYER M4 ;
        RECT 0.000 313.632 0.192 313.656 ;
    END
  END t_out[265]
  PIN t_out[266]
    DIRECTION OUTPUT ;
    USE SIGNAL ;
    PORT
      LAYER M4 ;
        RECT 0.000 313.824 0.192 313.848 ;
    END
  END t_out[266]
  PIN t_out[267]
    DIRECTION OUTPUT ;
    USE SIGNAL ;
    PORT
      LAYER M4 ;
        RECT 0.000 314.016 0.192 314.040 ;
    END
  END t_out[267]
  PIN t_out[268]
    DIRECTION OUTPUT ;
    USE SIGNAL ;
    PORT
      LAYER M4 ;
        RECT 0.000 314.208 0.192 314.232 ;
    END
  END t_out[268]
  PIN t_out[269]
    DIRECTION OUTPUT ;
    USE SIGNAL ;
    PORT
      LAYER M4 ;
        RECT 0.000 314.400 0.192 314.424 ;
    END
  END t_out[269]
  PIN t_out[270]
    DIRECTION OUTPUT ;
    USE SIGNAL ;
    PORT
      LAYER M4 ;
        RECT 0.000 314.592 0.192 314.616 ;
    END
  END t_out[270]
  PIN t_out[271]
    DIRECTION OUTPUT ;
    USE SIGNAL ;
    PORT
      LAYER M4 ;
        RECT 0.000 314.784 0.192 314.808 ;
    END
  END t_out[271]
  PIN t_out[272]
    DIRECTION OUTPUT ;
    USE SIGNAL ;
    PORT
      LAYER M4 ;
        RECT 0.000 314.976 0.192 315.000 ;
    END
  END t_out[272]
  PIN t_out[273]
    DIRECTION OUTPUT ;
    USE SIGNAL ;
    PORT
      LAYER M4 ;
        RECT 0.000 315.168 0.192 315.192 ;
    END
  END t_out[273]
  PIN t_out[274]
    DIRECTION OUTPUT ;
    USE SIGNAL ;
    PORT
      LAYER M4 ;
        RECT 0.000 315.360 0.192 315.384 ;
    END
  END t_out[274]
  PIN t_out[275]
    DIRECTION OUTPUT ;
    USE SIGNAL ;
    PORT
      LAYER M4 ;
        RECT 0.000 315.552 0.192 315.576 ;
    END
  END t_out[275]
  PIN t_out[276]
    DIRECTION OUTPUT ;
    USE SIGNAL ;
    PORT
      LAYER M4 ;
        RECT 0.000 315.744 0.192 315.768 ;
    END
  END t_out[276]
  PIN t_out[277]
    DIRECTION OUTPUT ;
    USE SIGNAL ;
    PORT
      LAYER M4 ;
        RECT 0.000 315.936 0.192 315.960 ;
    END
  END t_out[277]
  PIN t_out[278]
    DIRECTION OUTPUT ;
    USE SIGNAL ;
    PORT
      LAYER M4 ;
        RECT 0.000 316.128 0.192 316.152 ;
    END
  END t_out[278]
  PIN t_out[279]
    DIRECTION OUTPUT ;
    USE SIGNAL ;
    PORT
      LAYER M4 ;
        RECT 0.000 316.320 0.192 316.344 ;
    END
  END t_out[279]
  PIN t_out[280]
    DIRECTION OUTPUT ;
    USE SIGNAL ;
    PORT
      LAYER M4 ;
        RECT 0.000 316.512 0.192 316.536 ;
    END
  END t_out[280]
  PIN t_out[281]
    DIRECTION OUTPUT ;
    USE SIGNAL ;
    PORT
      LAYER M4 ;
        RECT 0.000 316.704 0.192 316.728 ;
    END
  END t_out[281]
  PIN t_out[282]
    DIRECTION OUTPUT ;
    USE SIGNAL ;
    PORT
      LAYER M4 ;
        RECT 0.000 316.896 0.192 316.920 ;
    END
  END t_out[282]
  PIN t_out[283]
    DIRECTION OUTPUT ;
    USE SIGNAL ;
    PORT
      LAYER M4 ;
        RECT 0.000 317.088 0.192 317.112 ;
    END
  END t_out[283]
  PIN t_out[284]
    DIRECTION OUTPUT ;
    USE SIGNAL ;
    PORT
      LAYER M4 ;
        RECT 0.000 317.280 0.192 317.304 ;
    END
  END t_out[284]
  PIN t_out[285]
    DIRECTION OUTPUT ;
    USE SIGNAL ;
    PORT
      LAYER M4 ;
        RECT 0.000 317.472 0.192 317.496 ;
    END
  END t_out[285]
  PIN t_out[286]
    DIRECTION OUTPUT ;
    USE SIGNAL ;
    PORT
      LAYER M4 ;
        RECT 0.000 317.664 0.192 317.688 ;
    END
  END t_out[286]
  PIN t_out[287]
    DIRECTION OUTPUT ;
    USE SIGNAL ;
    PORT
      LAYER M4 ;
        RECT 0.000 317.856 0.192 317.880 ;
    END
  END t_out[287]
  PIN t_out[288]
    DIRECTION OUTPUT ;
    USE SIGNAL ;
    PORT
      LAYER M4 ;
        RECT 0.000 318.048 0.192 318.072 ;
    END
  END t_out[288]
  PIN t_out[289]
    DIRECTION OUTPUT ;
    USE SIGNAL ;
    PORT
      LAYER M4 ;
        RECT 0.000 318.240 0.192 318.264 ;
    END
  END t_out[289]
  PIN t_out[290]
    DIRECTION OUTPUT ;
    USE SIGNAL ;
    PORT
      LAYER M4 ;
        RECT 0.000 318.432 0.192 318.456 ;
    END
  END t_out[290]
  PIN t_out[291]
    DIRECTION OUTPUT ;
    USE SIGNAL ;
    PORT
      LAYER M4 ;
        RECT 0.000 318.624 0.192 318.648 ;
    END
  END t_out[291]
  PIN t_out[292]
    DIRECTION OUTPUT ;
    USE SIGNAL ;
    PORT
      LAYER M4 ;
        RECT 0.000 318.816 0.192 318.840 ;
    END
  END t_out[292]
  PIN t_out[293]
    DIRECTION OUTPUT ;
    USE SIGNAL ;
    PORT
      LAYER M4 ;
        RECT 0.000 319.008 0.192 319.032 ;
    END
  END t_out[293]
  PIN t_out[294]
    DIRECTION OUTPUT ;
    USE SIGNAL ;
    PORT
      LAYER M4 ;
        RECT 0.000 319.200 0.192 319.224 ;
    END
  END t_out[294]
  PIN t_out[295]
    DIRECTION OUTPUT ;
    USE SIGNAL ;
    PORT
      LAYER M4 ;
        RECT 0.000 319.392 0.192 319.416 ;
    END
  END t_out[295]
  PIN t_out[296]
    DIRECTION OUTPUT ;
    USE SIGNAL ;
    PORT
      LAYER M4 ;
        RECT 0.000 319.584 0.192 319.608 ;
    END
  END t_out[296]
  PIN t_out[297]
    DIRECTION OUTPUT ;
    USE SIGNAL ;
    PORT
      LAYER M4 ;
        RECT 0.000 319.776 0.192 319.800 ;
    END
  END t_out[297]
  PIN t_out[298]
    DIRECTION OUTPUT ;
    USE SIGNAL ;
    PORT
      LAYER M4 ;
        RECT 0.000 319.968 0.192 319.992 ;
    END
  END t_out[298]
  PIN t_out[299]
    DIRECTION OUTPUT ;
    USE SIGNAL ;
    PORT
      LAYER M4 ;
        RECT 0.000 320.160 0.192 320.184 ;
    END
  END t_out[299]
  PIN t_out[300]
    DIRECTION OUTPUT ;
    USE SIGNAL ;
    PORT
      LAYER M4 ;
        RECT 0.000 320.352 0.192 320.376 ;
    END
  END t_out[300]
  PIN t_out[301]
    DIRECTION OUTPUT ;
    USE SIGNAL ;
    PORT
      LAYER M4 ;
        RECT 0.000 320.544 0.192 320.568 ;
    END
  END t_out[301]
  PIN t_out[302]
    DIRECTION OUTPUT ;
    USE SIGNAL ;
    PORT
      LAYER M4 ;
        RECT 0.000 320.736 0.192 320.760 ;
    END
  END t_out[302]
  PIN t_out[303]
    DIRECTION OUTPUT ;
    USE SIGNAL ;
    PORT
      LAYER M4 ;
        RECT 0.000 320.928 0.192 320.952 ;
    END
  END t_out[303]
  PIN t_out[304]
    DIRECTION OUTPUT ;
    USE SIGNAL ;
    PORT
      LAYER M4 ;
        RECT 0.000 321.120 0.192 321.144 ;
    END
  END t_out[304]
  PIN t_out[305]
    DIRECTION OUTPUT ;
    USE SIGNAL ;
    PORT
      LAYER M4 ;
        RECT 0.000 321.312 0.192 321.336 ;
    END
  END t_out[305]
  PIN t_out[306]
    DIRECTION OUTPUT ;
    USE SIGNAL ;
    PORT
      LAYER M4 ;
        RECT 0.000 321.504 0.192 321.528 ;
    END
  END t_out[306]
  PIN t_out[307]
    DIRECTION OUTPUT ;
    USE SIGNAL ;
    PORT
      LAYER M4 ;
        RECT 0.000 321.696 0.192 321.720 ;
    END
  END t_out[307]
  PIN t_out[308]
    DIRECTION OUTPUT ;
    USE SIGNAL ;
    PORT
      LAYER M4 ;
        RECT 0.000 321.888 0.192 321.912 ;
    END
  END t_out[308]
  PIN t_out[309]
    DIRECTION OUTPUT ;
    USE SIGNAL ;
    PORT
      LAYER M4 ;
        RECT 0.000 322.080 0.192 322.104 ;
    END
  END t_out[309]
  PIN t_out[310]
    DIRECTION OUTPUT ;
    USE SIGNAL ;
    PORT
      LAYER M4 ;
        RECT 0.000 322.272 0.192 322.296 ;
    END
  END t_out[310]
  PIN t_out[311]
    DIRECTION OUTPUT ;
    USE SIGNAL ;
    PORT
      LAYER M4 ;
        RECT 0.000 322.464 0.192 322.488 ;
    END
  END t_out[311]
  PIN t_out[312]
    DIRECTION OUTPUT ;
    USE SIGNAL ;
    PORT
      LAYER M4 ;
        RECT 0.000 322.656 0.192 322.680 ;
    END
  END t_out[312]
  PIN t_out[313]
    DIRECTION OUTPUT ;
    USE SIGNAL ;
    PORT
      LAYER M4 ;
        RECT 0.000 322.848 0.192 322.872 ;
    END
  END t_out[313]
  PIN t_out[314]
    DIRECTION OUTPUT ;
    USE SIGNAL ;
    PORT
      LAYER M4 ;
        RECT 0.000 323.040 0.192 323.064 ;
    END
  END t_out[314]
  PIN t_out[315]
    DIRECTION OUTPUT ;
    USE SIGNAL ;
    PORT
      LAYER M4 ;
        RECT 0.000 323.232 0.192 323.256 ;
    END
  END t_out[315]
  PIN t_out[316]
    DIRECTION OUTPUT ;
    USE SIGNAL ;
    PORT
      LAYER M4 ;
        RECT 0.000 323.424 0.192 323.448 ;
    END
  END t_out[316]
  PIN t_out[317]
    DIRECTION OUTPUT ;
    USE SIGNAL ;
    PORT
      LAYER M4 ;
        RECT 0.000 323.616 0.192 323.640 ;
    END
  END t_out[317]
  PIN t_out[318]
    DIRECTION OUTPUT ;
    USE SIGNAL ;
    PORT
      LAYER M4 ;
        RECT 0.000 323.808 0.192 323.832 ;
    END
  END t_out[318]
  PIN t_out[319]
    DIRECTION OUTPUT ;
    USE SIGNAL ;
    PORT
      LAYER M4 ;
        RECT 0.000 324.000 0.192 324.024 ;
    END
  END t_out[319]
  PIN t_out[320]
    DIRECTION OUTPUT ;
    USE SIGNAL ;
    PORT
      LAYER M4 ;
        RECT 0.000 324.192 0.192 324.216 ;
    END
  END t_out[320]
  PIN t_out[321]
    DIRECTION OUTPUT ;
    USE SIGNAL ;
    PORT
      LAYER M4 ;
        RECT 0.000 324.384 0.192 324.408 ;
    END
  END t_out[321]
  PIN t_out[322]
    DIRECTION OUTPUT ;
    USE SIGNAL ;
    PORT
      LAYER M4 ;
        RECT 0.000 324.576 0.192 324.600 ;
    END
  END t_out[322]
  PIN t_out[323]
    DIRECTION OUTPUT ;
    USE SIGNAL ;
    PORT
      LAYER M4 ;
        RECT 0.000 324.768 0.192 324.792 ;
    END
  END t_out[323]
  PIN t_out[324]
    DIRECTION OUTPUT ;
    USE SIGNAL ;
    PORT
      LAYER M4 ;
        RECT 0.000 324.960 0.192 324.984 ;
    END
  END t_out[324]
  PIN t_out[325]
    DIRECTION OUTPUT ;
    USE SIGNAL ;
    PORT
      LAYER M4 ;
        RECT 0.000 325.152 0.192 325.176 ;
    END
  END t_out[325]
  PIN t_out[326]
    DIRECTION OUTPUT ;
    USE SIGNAL ;
    PORT
      LAYER M4 ;
        RECT 0.000 325.344 0.192 325.368 ;
    END
  END t_out[326]
  PIN t_out[327]
    DIRECTION OUTPUT ;
    USE SIGNAL ;
    PORT
      LAYER M4 ;
        RECT 0.000 325.536 0.192 325.560 ;
    END
  END t_out[327]
  PIN t_out[328]
    DIRECTION OUTPUT ;
    USE SIGNAL ;
    PORT
      LAYER M4 ;
        RECT 0.000 325.728 0.192 325.752 ;
    END
  END t_out[328]
  PIN t_out[329]
    DIRECTION OUTPUT ;
    USE SIGNAL ;
    PORT
      LAYER M4 ;
        RECT 0.000 325.920 0.192 325.944 ;
    END
  END t_out[329]
  PIN t_out[330]
    DIRECTION OUTPUT ;
    USE SIGNAL ;
    PORT
      LAYER M4 ;
        RECT 0.000 326.112 0.192 326.136 ;
    END
  END t_out[330]
  PIN t_out[331]
    DIRECTION OUTPUT ;
    USE SIGNAL ;
    PORT
      LAYER M4 ;
        RECT 0.000 326.304 0.192 326.328 ;
    END
  END t_out[331]
  PIN t_out[332]
    DIRECTION OUTPUT ;
    USE SIGNAL ;
    PORT
      LAYER M4 ;
        RECT 0.000 326.496 0.192 326.520 ;
    END
  END t_out[332]
  PIN t_out[333]
    DIRECTION OUTPUT ;
    USE SIGNAL ;
    PORT
      LAYER M4 ;
        RECT 0.000 326.688 0.192 326.712 ;
    END
  END t_out[333]
  PIN t_out[334]
    DIRECTION OUTPUT ;
    USE SIGNAL ;
    PORT
      LAYER M4 ;
        RECT 0.000 326.880 0.192 326.904 ;
    END
  END t_out[334]
  PIN t_out[335]
    DIRECTION OUTPUT ;
    USE SIGNAL ;
    PORT
      LAYER M4 ;
        RECT 0.000 327.072 0.192 327.096 ;
    END
  END t_out[335]
  PIN t_out[336]
    DIRECTION OUTPUT ;
    USE SIGNAL ;
    PORT
      LAYER M4 ;
        RECT 0.000 327.264 0.192 327.288 ;
    END
  END t_out[336]
  PIN t_out[337]
    DIRECTION OUTPUT ;
    USE SIGNAL ;
    PORT
      LAYER M4 ;
        RECT 0.000 327.456 0.192 327.480 ;
    END
  END t_out[337]
  PIN t_out[338]
    DIRECTION OUTPUT ;
    USE SIGNAL ;
    PORT
      LAYER M4 ;
        RECT 0.000 327.648 0.192 327.672 ;
    END
  END t_out[338]
  PIN t_out[339]
    DIRECTION OUTPUT ;
    USE SIGNAL ;
    PORT
      LAYER M4 ;
        RECT 0.000 327.840 0.192 327.864 ;
    END
  END t_out[339]
  PIN t_out[340]
    DIRECTION OUTPUT ;
    USE SIGNAL ;
    PORT
      LAYER M4 ;
        RECT 0.000 328.032 0.192 328.056 ;
    END
  END t_out[340]
  PIN t_out[341]
    DIRECTION OUTPUT ;
    USE SIGNAL ;
    PORT
      LAYER M4 ;
        RECT 0.000 328.224 0.192 328.248 ;
    END
  END t_out[341]
  PIN t_out[342]
    DIRECTION OUTPUT ;
    USE SIGNAL ;
    PORT
      LAYER M4 ;
        RECT 0.000 328.416 0.192 328.440 ;
    END
  END t_out[342]
  PIN t_out[343]
    DIRECTION OUTPUT ;
    USE SIGNAL ;
    PORT
      LAYER M4 ;
        RECT 0.000 328.608 0.192 328.632 ;
    END
  END t_out[343]
  PIN t_out[344]
    DIRECTION OUTPUT ;
    USE SIGNAL ;
    PORT
      LAYER M4 ;
        RECT 0.000 328.800 0.192 328.824 ;
    END
  END t_out[344]
  PIN t_out[345]
    DIRECTION OUTPUT ;
    USE SIGNAL ;
    PORT
      LAYER M4 ;
        RECT 0.000 328.992 0.192 329.016 ;
    END
  END t_out[345]
  PIN t_out[346]
    DIRECTION OUTPUT ;
    USE SIGNAL ;
    PORT
      LAYER M4 ;
        RECT 0.000 329.184 0.192 329.208 ;
    END
  END t_out[346]
  PIN t_out[347]
    DIRECTION OUTPUT ;
    USE SIGNAL ;
    PORT
      LAYER M4 ;
        RECT 0.000 329.376 0.192 329.400 ;
    END
  END t_out[347]
  PIN t_out[348]
    DIRECTION OUTPUT ;
    USE SIGNAL ;
    PORT
      LAYER M4 ;
        RECT 0.000 329.568 0.192 329.592 ;
    END
  END t_out[348]
  PIN t_out[349]
    DIRECTION OUTPUT ;
    USE SIGNAL ;
    PORT
      LAYER M4 ;
        RECT 0.000 329.760 0.192 329.784 ;
    END
  END t_out[349]
  PIN t_out[350]
    DIRECTION OUTPUT ;
    USE SIGNAL ;
    PORT
      LAYER M4 ;
        RECT 0.000 329.952 0.192 329.976 ;
    END
  END t_out[350]
  PIN t_out[351]
    DIRECTION OUTPUT ;
    USE SIGNAL ;
    PORT
      LAYER M4 ;
        RECT 0.000 330.144 0.192 330.168 ;
    END
  END t_out[351]
  PIN t_out[352]
    DIRECTION OUTPUT ;
    USE SIGNAL ;
    PORT
      LAYER M4 ;
        RECT 0.000 330.336 0.192 330.360 ;
    END
  END t_out[352]
  PIN t_out[353]
    DIRECTION OUTPUT ;
    USE SIGNAL ;
    PORT
      LAYER M4 ;
        RECT 0.000 330.528 0.192 330.552 ;
    END
  END t_out[353]
  PIN t_out[354]
    DIRECTION OUTPUT ;
    USE SIGNAL ;
    PORT
      LAYER M4 ;
        RECT 0.000 330.720 0.192 330.744 ;
    END
  END t_out[354]
  PIN t_out[355]
    DIRECTION OUTPUT ;
    USE SIGNAL ;
    PORT
      LAYER M4 ;
        RECT 0.000 330.912 0.192 330.936 ;
    END
  END t_out[355]
  PIN t_out[356]
    DIRECTION OUTPUT ;
    USE SIGNAL ;
    PORT
      LAYER M4 ;
        RECT 0.000 331.104 0.192 331.128 ;
    END
  END t_out[356]
  PIN t_out[357]
    DIRECTION OUTPUT ;
    USE SIGNAL ;
    PORT
      LAYER M4 ;
        RECT 0.000 331.296 0.192 331.320 ;
    END
  END t_out[357]
  PIN t_out[358]
    DIRECTION OUTPUT ;
    USE SIGNAL ;
    PORT
      LAYER M4 ;
        RECT 0.000 331.488 0.192 331.512 ;
    END
  END t_out[358]
  PIN t_out[359]
    DIRECTION OUTPUT ;
    USE SIGNAL ;
    PORT
      LAYER M4 ;
        RECT 0.000 331.680 0.192 331.704 ;
    END
  END t_out[359]
  PIN t_out[360]
    DIRECTION OUTPUT ;
    USE SIGNAL ;
    PORT
      LAYER M4 ;
        RECT 0.000 331.872 0.192 331.896 ;
    END
  END t_out[360]
  PIN t_out[361]
    DIRECTION OUTPUT ;
    USE SIGNAL ;
    PORT
      LAYER M4 ;
        RECT 0.000 332.064 0.192 332.088 ;
    END
  END t_out[361]
  PIN t_out[362]
    DIRECTION OUTPUT ;
    USE SIGNAL ;
    PORT
      LAYER M4 ;
        RECT 0.000 332.256 0.192 332.280 ;
    END
  END t_out[362]
  PIN t_out[363]
    DIRECTION OUTPUT ;
    USE SIGNAL ;
    PORT
      LAYER M4 ;
        RECT 0.000 332.448 0.192 332.472 ;
    END
  END t_out[363]
  PIN t_out[364]
    DIRECTION OUTPUT ;
    USE SIGNAL ;
    PORT
      LAYER M4 ;
        RECT 0.000 332.640 0.192 332.664 ;
    END
  END t_out[364]
  PIN t_out[365]
    DIRECTION OUTPUT ;
    USE SIGNAL ;
    PORT
      LAYER M4 ;
        RECT 0.000 332.832 0.192 332.856 ;
    END
  END t_out[365]
  PIN t_out[366]
    DIRECTION OUTPUT ;
    USE SIGNAL ;
    PORT
      LAYER M4 ;
        RECT 0.000 333.024 0.192 333.048 ;
    END
  END t_out[366]
  PIN t_out[367]
    DIRECTION OUTPUT ;
    USE SIGNAL ;
    PORT
      LAYER M4 ;
        RECT 0.000 333.216 0.192 333.240 ;
    END
  END t_out[367]
  PIN t_out[368]
    DIRECTION OUTPUT ;
    USE SIGNAL ;
    PORT
      LAYER M4 ;
        RECT 0.000 333.408 0.192 333.432 ;
    END
  END t_out[368]
  PIN t_out[369]
    DIRECTION OUTPUT ;
    USE SIGNAL ;
    PORT
      LAYER M4 ;
        RECT 0.000 333.600 0.192 333.624 ;
    END
  END t_out[369]
  PIN t_out[370]
    DIRECTION OUTPUT ;
    USE SIGNAL ;
    PORT
      LAYER M4 ;
        RECT 0.000 333.792 0.192 333.816 ;
    END
  END t_out[370]
  PIN t_out[371]
    DIRECTION OUTPUT ;
    USE SIGNAL ;
    PORT
      LAYER M4 ;
        RECT 0.000 333.984 0.192 334.008 ;
    END
  END t_out[371]
  PIN t_out[372]
    DIRECTION OUTPUT ;
    USE SIGNAL ;
    PORT
      LAYER M4 ;
        RECT 0.000 334.176 0.192 334.200 ;
    END
  END t_out[372]
  PIN t_out[373]
    DIRECTION OUTPUT ;
    USE SIGNAL ;
    PORT
      LAYER M4 ;
        RECT 0.000 334.368 0.192 334.392 ;
    END
  END t_out[373]
  PIN t_out[374]
    DIRECTION OUTPUT ;
    USE SIGNAL ;
    PORT
      LAYER M4 ;
        RECT 0.000 334.560 0.192 334.584 ;
    END
  END t_out[374]
  PIN t_out[375]
    DIRECTION OUTPUT ;
    USE SIGNAL ;
    PORT
      LAYER M4 ;
        RECT 0.000 334.752 0.192 334.776 ;
    END
  END t_out[375]
  PIN t_out[376]
    DIRECTION OUTPUT ;
    USE SIGNAL ;
    PORT
      LAYER M4 ;
        RECT 0.000 334.944 0.192 334.968 ;
    END
  END t_out[376]
  PIN t_out[377]
    DIRECTION OUTPUT ;
    USE SIGNAL ;
    PORT
      LAYER M4 ;
        RECT 0.000 335.136 0.192 335.160 ;
    END
  END t_out[377]
  PIN t_out[378]
    DIRECTION OUTPUT ;
    USE SIGNAL ;
    PORT
      LAYER M4 ;
        RECT 0.000 335.328 0.192 335.352 ;
    END
  END t_out[378]
  PIN t_out[379]
    DIRECTION OUTPUT ;
    USE SIGNAL ;
    PORT
      LAYER M4 ;
        RECT 0.000 335.520 0.192 335.544 ;
    END
  END t_out[379]
  PIN t_out[380]
    DIRECTION OUTPUT ;
    USE SIGNAL ;
    PORT
      LAYER M4 ;
        RECT 0.000 335.712 0.192 335.736 ;
    END
  END t_out[380]
  PIN t_out[381]
    DIRECTION OUTPUT ;
    USE SIGNAL ;
    PORT
      LAYER M4 ;
        RECT 0.000 335.904 0.192 335.928 ;
    END
  END t_out[381]
  PIN t_out[382]
    DIRECTION OUTPUT ;
    USE SIGNAL ;
    PORT
      LAYER M4 ;
        RECT 0.000 336.096 0.192 336.120 ;
    END
  END t_out[382]
  PIN t_out[383]
    DIRECTION OUTPUT ;
    USE SIGNAL ;
    PORT
      LAYER M4 ;
        RECT 0.000 336.288 0.192 336.312 ;
    END
  END t_out[383]
  PIN t_out[384]
    DIRECTION OUTPUT ;
    USE SIGNAL ;
    PORT
      LAYER M4 ;
        RECT 0.000 336.480 0.192 336.504 ;
    END
  END t_out[384]
  PIN t_out[385]
    DIRECTION OUTPUT ;
    USE SIGNAL ;
    PORT
      LAYER M4 ;
        RECT 0.000 336.672 0.192 336.696 ;
    END
  END t_out[385]
  PIN t_out[386]
    DIRECTION OUTPUT ;
    USE SIGNAL ;
    PORT
      LAYER M4 ;
        RECT 0.000 336.864 0.192 336.888 ;
    END
  END t_out[386]
  PIN t_out[387]
    DIRECTION OUTPUT ;
    USE SIGNAL ;
    PORT
      LAYER M4 ;
        RECT 0.000 337.056 0.192 337.080 ;
    END
  END t_out[387]
  PIN t_out[388]
    DIRECTION OUTPUT ;
    USE SIGNAL ;
    PORT
      LAYER M4 ;
        RECT 0.000 337.248 0.192 337.272 ;
    END
  END t_out[388]
  PIN t_out[389]
    DIRECTION OUTPUT ;
    USE SIGNAL ;
    PORT
      LAYER M4 ;
        RECT 0.000 337.440 0.192 337.464 ;
    END
  END t_out[389]
  PIN t_out[390]
    DIRECTION OUTPUT ;
    USE SIGNAL ;
    PORT
      LAYER M4 ;
        RECT 0.000 337.632 0.192 337.656 ;
    END
  END t_out[390]
  PIN t_out[391]
    DIRECTION OUTPUT ;
    USE SIGNAL ;
    PORT
      LAYER M4 ;
        RECT 0.000 337.824 0.192 337.848 ;
    END
  END t_out[391]
  PIN t_out[392]
    DIRECTION OUTPUT ;
    USE SIGNAL ;
    PORT
      LAYER M4 ;
        RECT 0.000 338.016 0.192 338.040 ;
    END
  END t_out[392]
  PIN t_out[393]
    DIRECTION OUTPUT ;
    USE SIGNAL ;
    PORT
      LAYER M4 ;
        RECT 0.000 338.208 0.192 338.232 ;
    END
  END t_out[393]
  PIN t_out[394]
    DIRECTION OUTPUT ;
    USE SIGNAL ;
    PORT
      LAYER M4 ;
        RECT 0.000 338.400 0.192 338.424 ;
    END
  END t_out[394]
  PIN t_out[395]
    DIRECTION OUTPUT ;
    USE SIGNAL ;
    PORT
      LAYER M4 ;
        RECT 0.000 338.592 0.192 338.616 ;
    END
  END t_out[395]
  PIN t_out[396]
    DIRECTION OUTPUT ;
    USE SIGNAL ;
    PORT
      LAYER M4 ;
        RECT 0.000 338.784 0.192 338.808 ;
    END
  END t_out[396]
  PIN t_out[397]
    DIRECTION OUTPUT ;
    USE SIGNAL ;
    PORT
      LAYER M4 ;
        RECT 0.000 338.976 0.192 339.000 ;
    END
  END t_out[397]
  PIN t_out[398]
    DIRECTION OUTPUT ;
    USE SIGNAL ;
    PORT
      LAYER M4 ;
        RECT 0.000 339.168 0.192 339.192 ;
    END
  END t_out[398]
  PIN t_out[399]
    DIRECTION OUTPUT ;
    USE SIGNAL ;
    PORT
      LAYER M4 ;
        RECT 0.000 339.360 0.192 339.384 ;
    END
  END t_out[399]
  PIN t_out[400]
    DIRECTION OUTPUT ;
    USE SIGNAL ;
    PORT
      LAYER M4 ;
        RECT 0.000 339.552 0.192 339.576 ;
    END
  END t_out[400]
  PIN t_out[401]
    DIRECTION OUTPUT ;
    USE SIGNAL ;
    PORT
      LAYER M4 ;
        RECT 0.000 339.744 0.192 339.768 ;
    END
  END t_out[401]
  PIN t_out[402]
    DIRECTION OUTPUT ;
    USE SIGNAL ;
    PORT
      LAYER M4 ;
        RECT 0.000 339.936 0.192 339.960 ;
    END
  END t_out[402]
  PIN t_out[403]
    DIRECTION OUTPUT ;
    USE SIGNAL ;
    PORT
      LAYER M4 ;
        RECT 0.000 340.128 0.192 340.152 ;
    END
  END t_out[403]
  PIN t_out[404]
    DIRECTION OUTPUT ;
    USE SIGNAL ;
    PORT
      LAYER M4 ;
        RECT 0.000 340.320 0.192 340.344 ;
    END
  END t_out[404]
  PIN t_out[405]
    DIRECTION OUTPUT ;
    USE SIGNAL ;
    PORT
      LAYER M4 ;
        RECT 0.000 340.512 0.192 340.536 ;
    END
  END t_out[405]
  PIN t_out[406]
    DIRECTION OUTPUT ;
    USE SIGNAL ;
    PORT
      LAYER M4 ;
        RECT 0.000 340.704 0.192 340.728 ;
    END
  END t_out[406]
  PIN t_out[407]
    DIRECTION OUTPUT ;
    USE SIGNAL ;
    PORT
      LAYER M4 ;
        RECT 0.000 340.896 0.192 340.920 ;
    END
  END t_out[407]
  PIN t_out[408]
    DIRECTION OUTPUT ;
    USE SIGNAL ;
    PORT
      LAYER M4 ;
        RECT 0.000 341.088 0.192 341.112 ;
    END
  END t_out[408]
  PIN t_out[409]
    DIRECTION OUTPUT ;
    USE SIGNAL ;
    PORT
      LAYER M4 ;
        RECT 0.000 341.280 0.192 341.304 ;
    END
  END t_out[409]
  PIN t_out[410]
    DIRECTION OUTPUT ;
    USE SIGNAL ;
    PORT
      LAYER M4 ;
        RECT 0.000 341.472 0.192 341.496 ;
    END
  END t_out[410]
  PIN t_out[411]
    DIRECTION OUTPUT ;
    USE SIGNAL ;
    PORT
      LAYER M4 ;
        RECT 0.000 341.664 0.192 341.688 ;
    END
  END t_out[411]
  PIN t_out[412]
    DIRECTION OUTPUT ;
    USE SIGNAL ;
    PORT
      LAYER M4 ;
        RECT 0.000 341.856 0.192 341.880 ;
    END
  END t_out[412]
  PIN t_out[413]
    DIRECTION OUTPUT ;
    USE SIGNAL ;
    PORT
      LAYER M4 ;
        RECT 0.000 342.048 0.192 342.072 ;
    END
  END t_out[413]
  PIN t_out[414]
    DIRECTION OUTPUT ;
    USE SIGNAL ;
    PORT
      LAYER M4 ;
        RECT 0.000 342.240 0.192 342.264 ;
    END
  END t_out[414]
  PIN t_out[415]
    DIRECTION OUTPUT ;
    USE SIGNAL ;
    PORT
      LAYER M4 ;
        RECT 0.000 342.432 0.192 342.456 ;
    END
  END t_out[415]
  PIN t_out[416]
    DIRECTION OUTPUT ;
    USE SIGNAL ;
    PORT
      LAYER M4 ;
        RECT 0.000 342.624 0.192 342.648 ;
    END
  END t_out[416]
  PIN t_out[417]
    DIRECTION OUTPUT ;
    USE SIGNAL ;
    PORT
      LAYER M4 ;
        RECT 0.000 342.816 0.192 342.840 ;
    END
  END t_out[417]
  PIN t_out[418]
    DIRECTION OUTPUT ;
    USE SIGNAL ;
    PORT
      LAYER M4 ;
        RECT 0.000 343.008 0.192 343.032 ;
    END
  END t_out[418]
  PIN t_out[419]
    DIRECTION OUTPUT ;
    USE SIGNAL ;
    PORT
      LAYER M4 ;
        RECT 0.000 343.200 0.192 343.224 ;
    END
  END t_out[419]
  PIN t_out[420]
    DIRECTION OUTPUT ;
    USE SIGNAL ;
    PORT
      LAYER M4 ;
        RECT 0.000 343.392 0.192 343.416 ;
    END
  END t_out[420]
  PIN t_out[421]
    DIRECTION OUTPUT ;
    USE SIGNAL ;
    PORT
      LAYER M4 ;
        RECT 0.000 343.584 0.192 343.608 ;
    END
  END t_out[421]
  PIN t_out[422]
    DIRECTION OUTPUT ;
    USE SIGNAL ;
    PORT
      LAYER M4 ;
        RECT 0.000 343.776 0.192 343.800 ;
    END
  END t_out[422]
  PIN t_out[423]
    DIRECTION OUTPUT ;
    USE SIGNAL ;
    PORT
      LAYER M4 ;
        RECT 0.000 343.968 0.192 343.992 ;
    END
  END t_out[423]
  PIN t_out[424]
    DIRECTION OUTPUT ;
    USE SIGNAL ;
    PORT
      LAYER M4 ;
        RECT 0.000 344.160 0.192 344.184 ;
    END
  END t_out[424]
  PIN t_out[425]
    DIRECTION OUTPUT ;
    USE SIGNAL ;
    PORT
      LAYER M4 ;
        RECT 0.000 344.352 0.192 344.376 ;
    END
  END t_out[425]
  PIN t_out[426]
    DIRECTION OUTPUT ;
    USE SIGNAL ;
    PORT
      LAYER M4 ;
        RECT 0.000 344.544 0.192 344.568 ;
    END
  END t_out[426]
  PIN t_out[427]
    DIRECTION OUTPUT ;
    USE SIGNAL ;
    PORT
      LAYER M4 ;
        RECT 0.000 344.736 0.192 344.760 ;
    END
  END t_out[427]
  PIN t_out[428]
    DIRECTION OUTPUT ;
    USE SIGNAL ;
    PORT
      LAYER M4 ;
        RECT 0.000 344.928 0.192 344.952 ;
    END
  END t_out[428]
  PIN t_out[429]
    DIRECTION OUTPUT ;
    USE SIGNAL ;
    PORT
      LAYER M4 ;
        RECT 0.000 345.120 0.192 345.144 ;
    END
  END t_out[429]
  PIN t_out[430]
    DIRECTION OUTPUT ;
    USE SIGNAL ;
    PORT
      LAYER M4 ;
        RECT 0.000 345.312 0.192 345.336 ;
    END
  END t_out[430]
  PIN t_out[431]
    DIRECTION OUTPUT ;
    USE SIGNAL ;
    PORT
      LAYER M4 ;
        RECT 0.000 345.504 0.192 345.528 ;
    END
  END t_out[431]
  PIN t_out[432]
    DIRECTION OUTPUT ;
    USE SIGNAL ;
    PORT
      LAYER M4 ;
        RECT 0.000 345.696 0.192 345.720 ;
    END
  END t_out[432]
  PIN t_out[433]
    DIRECTION OUTPUT ;
    USE SIGNAL ;
    PORT
      LAYER M4 ;
        RECT 0.000 345.888 0.192 345.912 ;
    END
  END t_out[433]
  PIN t_out[434]
    DIRECTION OUTPUT ;
    USE SIGNAL ;
    PORT
      LAYER M4 ;
        RECT 0.000 346.080 0.192 346.104 ;
    END
  END t_out[434]
  PIN t_out[435]
    DIRECTION OUTPUT ;
    USE SIGNAL ;
    PORT
      LAYER M4 ;
        RECT 0.000 346.272 0.192 346.296 ;
    END
  END t_out[435]
  PIN t_out[436]
    DIRECTION OUTPUT ;
    USE SIGNAL ;
    PORT
      LAYER M4 ;
        RECT 0.000 346.464 0.192 346.488 ;
    END
  END t_out[436]
  PIN t_out[437]
    DIRECTION OUTPUT ;
    USE SIGNAL ;
    PORT
      LAYER M4 ;
        RECT 0.000 346.656 0.192 346.680 ;
    END
  END t_out[437]
  PIN t_out[438]
    DIRECTION OUTPUT ;
    USE SIGNAL ;
    PORT
      LAYER M4 ;
        RECT 0.000 346.848 0.192 346.872 ;
    END
  END t_out[438]
  PIN t_out[439]
    DIRECTION OUTPUT ;
    USE SIGNAL ;
    PORT
      LAYER M4 ;
        RECT 0.000 347.040 0.192 347.064 ;
    END
  END t_out[439]
  PIN t_out[440]
    DIRECTION OUTPUT ;
    USE SIGNAL ;
    PORT
      LAYER M4 ;
        RECT 0.000 347.232 0.192 347.256 ;
    END
  END t_out[440]
  PIN t_out[441]
    DIRECTION OUTPUT ;
    USE SIGNAL ;
    PORT
      LAYER M4 ;
        RECT 0.000 347.424 0.192 347.448 ;
    END
  END t_out[441]
  PIN t_out[442]
    DIRECTION OUTPUT ;
    USE SIGNAL ;
    PORT
      LAYER M4 ;
        RECT 0.000 347.616 0.192 347.640 ;
    END
  END t_out[442]
  PIN t_out[443]
    DIRECTION OUTPUT ;
    USE SIGNAL ;
    PORT
      LAYER M4 ;
        RECT 0.000 347.808 0.192 347.832 ;
    END
  END t_out[443]
  PIN t_out[444]
    DIRECTION OUTPUT ;
    USE SIGNAL ;
    PORT
      LAYER M4 ;
        RECT 0.000 348.000 0.192 348.024 ;
    END
  END t_out[444]
  PIN t_out[445]
    DIRECTION OUTPUT ;
    USE SIGNAL ;
    PORT
      LAYER M4 ;
        RECT 0.000 348.192 0.192 348.216 ;
    END
  END t_out[445]
  PIN t_out[446]
    DIRECTION OUTPUT ;
    USE SIGNAL ;
    PORT
      LAYER M4 ;
        RECT 0.000 348.384 0.192 348.408 ;
    END
  END t_out[446]
  PIN t_out[447]
    DIRECTION OUTPUT ;
    USE SIGNAL ;
    PORT
      LAYER M4 ;
        RECT 0.000 348.576 0.192 348.600 ;
    END
  END t_out[447]
  PIN t_out[448]
    DIRECTION OUTPUT ;
    USE SIGNAL ;
    PORT
      LAYER M4 ;
        RECT 0.000 348.768 0.192 348.792 ;
    END
  END t_out[448]
  PIN t_out[449]
    DIRECTION OUTPUT ;
    USE SIGNAL ;
    PORT
      LAYER M4 ;
        RECT 0.000 348.960 0.192 348.984 ;
    END
  END t_out[449]
  PIN t_out[450]
    DIRECTION OUTPUT ;
    USE SIGNAL ;
    PORT
      LAYER M4 ;
        RECT 0.000 349.152 0.192 349.176 ;
    END
  END t_out[450]
  PIN t_out[451]
    DIRECTION OUTPUT ;
    USE SIGNAL ;
    PORT
      LAYER M4 ;
        RECT 0.000 349.344 0.192 349.368 ;
    END
  END t_out[451]
  PIN t_out[452]
    DIRECTION OUTPUT ;
    USE SIGNAL ;
    PORT
      LAYER M4 ;
        RECT 0.000 349.536 0.192 349.560 ;
    END
  END t_out[452]
  PIN t_out[453]
    DIRECTION OUTPUT ;
    USE SIGNAL ;
    PORT
      LAYER M4 ;
        RECT 0.000 349.728 0.192 349.752 ;
    END
  END t_out[453]
  PIN t_out[454]
    DIRECTION OUTPUT ;
    USE SIGNAL ;
    PORT
      LAYER M4 ;
        RECT 0.000 349.920 0.192 349.944 ;
    END
  END t_out[454]
  PIN t_out[455]
    DIRECTION OUTPUT ;
    USE SIGNAL ;
    PORT
      LAYER M4 ;
        RECT 0.000 350.112 0.192 350.136 ;
    END
  END t_out[455]
  PIN t_out[456]
    DIRECTION OUTPUT ;
    USE SIGNAL ;
    PORT
      LAYER M4 ;
        RECT 0.000 350.304 0.192 350.328 ;
    END
  END t_out[456]
  PIN t_out[457]
    DIRECTION OUTPUT ;
    USE SIGNAL ;
    PORT
      LAYER M4 ;
        RECT 0.000 350.496 0.192 350.520 ;
    END
  END t_out[457]
  PIN t_out[458]
    DIRECTION OUTPUT ;
    USE SIGNAL ;
    PORT
      LAYER M4 ;
        RECT 0.000 350.688 0.192 350.712 ;
    END
  END t_out[458]
  PIN t_out[459]
    DIRECTION OUTPUT ;
    USE SIGNAL ;
    PORT
      LAYER M4 ;
        RECT 0.000 350.880 0.192 350.904 ;
    END
  END t_out[459]
  PIN t_out[460]
    DIRECTION OUTPUT ;
    USE SIGNAL ;
    PORT
      LAYER M4 ;
        RECT 0.000 351.072 0.192 351.096 ;
    END
  END t_out[460]
  PIN t_out[461]
    DIRECTION OUTPUT ;
    USE SIGNAL ;
    PORT
      LAYER M4 ;
        RECT 0.000 351.264 0.192 351.288 ;
    END
  END t_out[461]
  PIN t_out[462]
    DIRECTION OUTPUT ;
    USE SIGNAL ;
    PORT
      LAYER M4 ;
        RECT 0.000 351.456 0.192 351.480 ;
    END
  END t_out[462]
  PIN t_out[463]
    DIRECTION OUTPUT ;
    USE SIGNAL ;
    PORT
      LAYER M4 ;
        RECT 0.000 351.648 0.192 351.672 ;
    END
  END t_out[463]
  PIN t_out[464]
    DIRECTION OUTPUT ;
    USE SIGNAL ;
    PORT
      LAYER M4 ;
        RECT 0.000 351.840 0.192 351.864 ;
    END
  END t_out[464]
  PIN t_out[465]
    DIRECTION OUTPUT ;
    USE SIGNAL ;
    PORT
      LAYER M4 ;
        RECT 0.000 352.032 0.192 352.056 ;
    END
  END t_out[465]
  PIN t_out[466]
    DIRECTION OUTPUT ;
    USE SIGNAL ;
    PORT
      LAYER M4 ;
        RECT 0.000 352.224 0.192 352.248 ;
    END
  END t_out[466]
  PIN t_out[467]
    DIRECTION OUTPUT ;
    USE SIGNAL ;
    PORT
      LAYER M4 ;
        RECT 0.000 352.416 0.192 352.440 ;
    END
  END t_out[467]
  PIN t_out[468]
    DIRECTION OUTPUT ;
    USE SIGNAL ;
    PORT
      LAYER M4 ;
        RECT 0.000 352.608 0.192 352.632 ;
    END
  END t_out[468]
  PIN t_out[469]
    DIRECTION OUTPUT ;
    USE SIGNAL ;
    PORT
      LAYER M4 ;
        RECT 0.000 352.800 0.192 352.824 ;
    END
  END t_out[469]
  PIN t_out[470]
    DIRECTION OUTPUT ;
    USE SIGNAL ;
    PORT
      LAYER M4 ;
        RECT 0.000 352.992 0.192 353.016 ;
    END
  END t_out[470]
  PIN t_out[471]
    DIRECTION OUTPUT ;
    USE SIGNAL ;
    PORT
      LAYER M4 ;
        RECT 0.000 353.184 0.192 353.208 ;
    END
  END t_out[471]
  PIN t_out[472]
    DIRECTION OUTPUT ;
    USE SIGNAL ;
    PORT
      LAYER M4 ;
        RECT 0.000 353.376 0.192 353.400 ;
    END
  END t_out[472]
  PIN t_out[473]
    DIRECTION OUTPUT ;
    USE SIGNAL ;
    PORT
      LAYER M4 ;
        RECT 0.000 353.568 0.192 353.592 ;
    END
  END t_out[473]
  PIN t_out[474]
    DIRECTION OUTPUT ;
    USE SIGNAL ;
    PORT
      LAYER M4 ;
        RECT 0.000 353.760 0.192 353.784 ;
    END
  END t_out[474]
  PIN t_out[475]
    DIRECTION OUTPUT ;
    USE SIGNAL ;
    PORT
      LAYER M4 ;
        RECT 0.000 353.952 0.192 353.976 ;
    END
  END t_out[475]
  PIN t_out[476]
    DIRECTION OUTPUT ;
    USE SIGNAL ;
    PORT
      LAYER M4 ;
        RECT 0.000 354.144 0.192 354.168 ;
    END
  END t_out[476]
  PIN t_out[477]
    DIRECTION OUTPUT ;
    USE SIGNAL ;
    PORT
      LAYER M4 ;
        RECT 0.000 354.336 0.192 354.360 ;
    END
  END t_out[477]
  PIN t_out[478]
    DIRECTION OUTPUT ;
    USE SIGNAL ;
    PORT
      LAYER M4 ;
        RECT 0.000 354.528 0.192 354.552 ;
    END
  END t_out[478]
  PIN t_out[479]
    DIRECTION OUTPUT ;
    USE SIGNAL ;
    PORT
      LAYER M4 ;
        RECT 0.000 354.720 0.192 354.744 ;
    END
  END t_out[479]
  PIN t_out[480]
    DIRECTION OUTPUT ;
    USE SIGNAL ;
    PORT
      LAYER M4 ;
        RECT 0.000 354.912 0.192 354.936 ;
    END
  END t_out[480]
  PIN t_out[481]
    DIRECTION OUTPUT ;
    USE SIGNAL ;
    PORT
      LAYER M4 ;
        RECT 0.000 355.104 0.192 355.128 ;
    END
  END t_out[481]
  PIN t_out[482]
    DIRECTION OUTPUT ;
    USE SIGNAL ;
    PORT
      LAYER M4 ;
        RECT 0.000 355.296 0.192 355.320 ;
    END
  END t_out[482]
  PIN t_out[483]
    DIRECTION OUTPUT ;
    USE SIGNAL ;
    PORT
      LAYER M4 ;
        RECT 0.000 355.488 0.192 355.512 ;
    END
  END t_out[483]
  PIN t_out[484]
    DIRECTION OUTPUT ;
    USE SIGNAL ;
    PORT
      LAYER M4 ;
        RECT 0.000 355.680 0.192 355.704 ;
    END
  END t_out[484]
  PIN t_out[485]
    DIRECTION OUTPUT ;
    USE SIGNAL ;
    PORT
      LAYER M4 ;
        RECT 0.000 355.872 0.192 355.896 ;
    END
  END t_out[485]
  PIN t_out[486]
    DIRECTION OUTPUT ;
    USE SIGNAL ;
    PORT
      LAYER M4 ;
        RECT 0.000 356.064 0.192 356.088 ;
    END
  END t_out[486]
  PIN t_out[487]
    DIRECTION OUTPUT ;
    USE SIGNAL ;
    PORT
      LAYER M4 ;
        RECT 0.000 356.256 0.192 356.280 ;
    END
  END t_out[487]
  PIN t_out[488]
    DIRECTION OUTPUT ;
    USE SIGNAL ;
    PORT
      LAYER M4 ;
        RECT 0.000 356.448 0.192 356.472 ;
    END
  END t_out[488]
  PIN t_out[489]
    DIRECTION OUTPUT ;
    USE SIGNAL ;
    PORT
      LAYER M4 ;
        RECT 0.000 356.640 0.192 356.664 ;
    END
  END t_out[489]
  PIN t_out[490]
    DIRECTION OUTPUT ;
    USE SIGNAL ;
    PORT
      LAYER M4 ;
        RECT 0.000 356.832 0.192 356.856 ;
    END
  END t_out[490]
  PIN t_out[491]
    DIRECTION OUTPUT ;
    USE SIGNAL ;
    PORT
      LAYER M4 ;
        RECT 0.000 357.024 0.192 357.048 ;
    END
  END t_out[491]
  PIN t_out[492]
    DIRECTION OUTPUT ;
    USE SIGNAL ;
    PORT
      LAYER M4 ;
        RECT 0.000 357.216 0.192 357.240 ;
    END
  END t_out[492]
  PIN t_out[493]
    DIRECTION OUTPUT ;
    USE SIGNAL ;
    PORT
      LAYER M4 ;
        RECT 0.000 357.408 0.192 357.432 ;
    END
  END t_out[493]
  PIN t_out[494]
    DIRECTION OUTPUT ;
    USE SIGNAL ;
    PORT
      LAYER M4 ;
        RECT 0.000 357.600 0.192 357.624 ;
    END
  END t_out[494]
  PIN t_out[495]
    DIRECTION OUTPUT ;
    USE SIGNAL ;
    PORT
      LAYER M4 ;
        RECT 0.000 357.792 0.192 357.816 ;
    END
  END t_out[495]
  PIN t_out[496]
    DIRECTION OUTPUT ;
    USE SIGNAL ;
    PORT
      LAYER M4 ;
        RECT 0.000 357.984 0.192 358.008 ;
    END
  END t_out[496]
  PIN t_out[497]
    DIRECTION OUTPUT ;
    USE SIGNAL ;
    PORT
      LAYER M4 ;
        RECT 0.000 358.176 0.192 358.200 ;
    END
  END t_out[497]
  PIN t_out[498]
    DIRECTION OUTPUT ;
    USE SIGNAL ;
    PORT
      LAYER M4 ;
        RECT 0.000 358.368 0.192 358.392 ;
    END
  END t_out[498]
  PIN t_out[499]
    DIRECTION OUTPUT ;
    USE SIGNAL ;
    PORT
      LAYER M4 ;
        RECT 0.000 358.560 0.192 358.584 ;
    END
  END t_out[499]
  PIN t_out[500]
    DIRECTION OUTPUT ;
    USE SIGNAL ;
    PORT
      LAYER M4 ;
        RECT 0.000 358.752 0.192 358.776 ;
    END
  END t_out[500]
  PIN t_out[501]
    DIRECTION OUTPUT ;
    USE SIGNAL ;
    PORT
      LAYER M4 ;
        RECT 0.000 358.944 0.192 358.968 ;
    END
  END t_out[501]
  PIN t_out[502]
    DIRECTION OUTPUT ;
    USE SIGNAL ;
    PORT
      LAYER M4 ;
        RECT 0.000 359.136 0.192 359.160 ;
    END
  END t_out[502]
  PIN t_out[503]
    DIRECTION OUTPUT ;
    USE SIGNAL ;
    PORT
      LAYER M4 ;
        RECT 0.000 359.328 0.192 359.352 ;
    END
  END t_out[503]
  PIN t_out[504]
    DIRECTION OUTPUT ;
    USE SIGNAL ;
    PORT
      LAYER M4 ;
        RECT 0.000 359.520 0.192 359.544 ;
    END
  END t_out[504]
  PIN t_out[505]
    DIRECTION OUTPUT ;
    USE SIGNAL ;
    PORT
      LAYER M4 ;
        RECT 0.000 359.712 0.192 359.736 ;
    END
  END t_out[505]
  PIN t_out[506]
    DIRECTION OUTPUT ;
    USE SIGNAL ;
    PORT
      LAYER M4 ;
        RECT 0.000 359.904 0.192 359.928 ;
    END
  END t_out[506]
  PIN t_out[507]
    DIRECTION OUTPUT ;
    USE SIGNAL ;
    PORT
      LAYER M4 ;
        RECT 0.000 360.096 0.192 360.120 ;
    END
  END t_out[507]
  PIN t_out[508]
    DIRECTION OUTPUT ;
    USE SIGNAL ;
    PORT
      LAYER M4 ;
        RECT 0.000 360.288 0.192 360.312 ;
    END
  END t_out[508]
  PIN t_out[509]
    DIRECTION OUTPUT ;
    USE SIGNAL ;
    PORT
      LAYER M4 ;
        RECT 0.000 360.480 0.192 360.504 ;
    END
  END t_out[509]
  PIN t_out[510]
    DIRECTION OUTPUT ;
    USE SIGNAL ;
    PORT
      LAYER M4 ;
        RECT 0.000 360.672 0.192 360.696 ;
    END
  END t_out[510]
  PIN t_out[511]
    DIRECTION OUTPUT ;
    USE SIGNAL ;
    PORT
      LAYER M4 ;
        RECT 0.000 360.864 0.192 360.888 ;
    END
  END t_out[511]
  PIN t_out[512]
    DIRECTION OUTPUT ;
    USE SIGNAL ;
    PORT
      LAYER M4 ;
        RECT 0.000 361.056 0.192 361.080 ;
    END
  END t_out[512]
  PIN t_out[513]
    DIRECTION OUTPUT ;
    USE SIGNAL ;
    PORT
      LAYER M4 ;
        RECT 0.000 361.248 0.192 361.272 ;
    END
  END t_out[513]
  PIN tie_lo
    DIRECTION OUTPUT ;
    USE SIGNAL ;
    PORT
      LAYER M4 ;
        RECT 457.728 429.168 457.920 429.192 ;
    END
  END tie_lo
  PIN tie_hi
    DIRECTION OUTPUT ;
    USE SIGNAL ;
    PORT
      LAYER M4 ;
        RECT 457.728 430.704 457.920 430.728 ;
    END
  END tie_hi
  PIN tile_id[0]
    DIRECTION INPUT ;
    USE SIGNAL ;
    PORT
      LAYER M4 ;
        RECT 457.728 432.192 457.920 432.216 ;
    END
  END tile_id[0]
  PIN tile_id[1]
    DIRECTION INPUT ;
    USE SIGNAL ;
    PORT
      LAYER M4 ;
        RECT 457.728 432.384 457.920 432.408 ;
    END
  END tile_id[1]
  PIN tile_id[2]
    DIRECTION INPUT ;
    USE SIGNAL ;
    PORT
      LAYER M4 ;
        RECT 457.728 432.576 457.920 432.600 ;
    END
  END tile_id[2]
  PIN tile_id[3]
    DIRECTION INPUT ;
    USE SIGNAL ;
    PORT
      LAYER M4 ;
        RECT 457.728 432.768 457.920 432.792 ;
    END
  END tile_id[3]
  PIN tile_id[4]
    DIRECTION INPUT ;
    USE SIGNAL ;
    PORT
      LAYER M4 ;
        RECT 457.728 432.960 457.920 432.984 ;
    END
  END tile_id[4]
  PIN tile_id[5]
    DIRECTION INPUT ;
    USE SIGNAL ;
    PORT
      LAYER M4 ;
        RECT 457.728 433.152 457.920 433.176 ;
    END
  END tile_id[5]
  PIN tile_id[6]
    DIRECTION INPUT ;
    USE SIGNAL ;
    PORT
      LAYER M4 ;
        RECT 457.728 433.344 457.920 433.368 ;
    END
  END tile_id[6]
  PIN tile_id[7]
    DIRECTION INPUT ;
    USE SIGNAL ;
    PORT
      LAYER M4 ;
        RECT 457.728 433.536 457.920 433.560 ;
    END
  END tile_id[7]
  PIN tile_id[8]
    DIRECTION INPUT ;
    USE SIGNAL ;
    PORT
      LAYER M4 ;
        RECT 457.728 433.728 457.920 433.752 ;
    END
  END tile_id[8]
  PIN tile_id[9]
    DIRECTION INPUT ;
    USE SIGNAL ;
    PORT
      LAYER M4 ;
        RECT 457.728 433.920 457.920 433.944 ;
    END
  END tile_id[9]
  PIN tile_id[10]
    DIRECTION INPUT ;
    USE SIGNAL ;
    PORT
      LAYER M4 ;
        RECT 457.728 434.112 457.920 434.136 ;
    END
  END tile_id[10]
  PIN tile_id[11]
    DIRECTION INPUT ;
    USE SIGNAL ;
    PORT
      LAYER M4 ;
        RECT 457.728 434.304 457.920 434.328 ;
    END
  END tile_id[11]
  PIN tile_id[12]
    DIRECTION INPUT ;
    USE SIGNAL ;
    PORT
      LAYER M4 ;
        RECT 457.728 434.496 457.920 434.520 ;
    END
  END tile_id[12]
  PIN tile_id[13]
    DIRECTION INPUT ;
    USE SIGNAL ;
    PORT
      LAYER M4 ;
        RECT 457.728 434.688 457.920 434.712 ;
    END
  END tile_id[13]
  PIN tile_id[14]
    DIRECTION INPUT ;
    USE SIGNAL ;
    PORT
      LAYER M4 ;
        RECT 457.728 434.880 457.920 434.904 ;
    END
  END tile_id[14]
  PIN tile_id[15]
    DIRECTION INPUT ;
    USE SIGNAL ;
    PORT
      LAYER M4 ;
        RECT 457.728 435.072 457.920 435.096 ;
    END
  END tile_id[15]
  PIN rst_n
    DIRECTION INPUT ;
    USE SIGNAL ;
    PORT
      LAYER M4 ;
        RECT 457.728 435.696 457.920 435.720 ;
    END
  END rst_n
  PIN tap[0]
    DIRECTION INPUT ;
    USE SIGNAL ;
    PORT
      LAYER M4 ;
        RECT 457.728 437.184 457.920 437.208 ;
    END
  END tap[0]
  PIN tap[1]
    DIRECTION INPUT ;
    USE SIGNAL ;
    PORT
      LAYER M4 ;
        RECT 457.728 437.280 457.920 437.304 ;
    END
  END tap[1]
  PIN tap[2]
    DIRECTION INPUT ;
    USE SIGNAL ;
    PORT
      LAYER M4 ;
        RECT 457.728 437.376 457.920 437.400 ;
    END
  END tap[2]
  PIN tap[3]
    DIRECTION INPUT ;
    USE SIGNAL ;
    PORT
      LAYER M4 ;
        RECT 457.728 437.472 457.920 437.496 ;
    END
  END tap[3]
  PIN tap[4]
    DIRECTION INPUT ;
    USE SIGNAL ;
    PORT
      LAYER M4 ;
        RECT 457.728 437.568 457.920 437.592 ;
    END
  END tap[4]
  PIN tap[5]
    DIRECTION INPUT ;
    USE SIGNAL ;
    PORT
      LAYER M4 ;
        RECT 457.728 437.664 457.920 437.688 ;
    END
  END tap[5]
  PIN tap[6]
    DIRECTION INPUT ;
    USE SIGNAL ;
    PORT
      LAYER M4 ;
        RECT 457.728 437.760 457.920 437.784 ;
    END
  END tap[6]
  PIN tap[7]
    DIRECTION INPUT ;
    USE SIGNAL ;
    PORT
      LAYER M4 ;
        RECT 457.728 437.856 457.920 437.880 ;
    END
  END tap[7]
  PIN tap[8]
    DIRECTION INPUT ;
    USE SIGNAL ;
    PORT
      LAYER M4 ;
        RECT 457.728 437.952 457.920 437.976 ;
    END
  END tap[8]
  PIN tap[9]
    DIRECTION INPUT ;
    USE SIGNAL ;
    PORT
      LAYER M4 ;
        RECT 457.728 438.048 457.920 438.072 ;
    END
  END tap[9]
  PIN tap[10]
    DIRECTION INPUT ;
    USE SIGNAL ;
    PORT
      LAYER M4 ;
        RECT 457.728 438.144 457.920 438.168 ;
    END
  END tap[10]
  PIN tap[11]
    DIRECTION INPUT ;
    USE SIGNAL ;
    PORT
      LAYER M4 ;
        RECT 457.728 438.240 457.920 438.264 ;
    END
  END tap[11]
  PIN tap[12]
    DIRECTION INPUT ;
    USE SIGNAL ;
    PORT
      LAYER M4 ;
        RECT 457.728 438.336 457.920 438.360 ;
    END
  END tap[12]
  PIN tap[13]
    DIRECTION INPUT ;
    USE SIGNAL ;
    PORT
      LAYER M4 ;
        RECT 457.728 438.432 457.920 438.456 ;
    END
  END tap[13]
  PIN tap[14]
    DIRECTION INPUT ;
    USE SIGNAL ;
    PORT
      LAYER M4 ;
        RECT 457.728 438.528 457.920 438.552 ;
    END
  END tap[14]
  PIN tap[15]
    DIRECTION INPUT ;
    USE SIGNAL ;
    PORT
      LAYER M4 ;
        RECT 457.728 438.624 457.920 438.648 ;
    END
  END tap[15]
  PIN tap[16]
    DIRECTION INPUT ;
    USE SIGNAL ;
    PORT
      LAYER M4 ;
        RECT 457.728 438.720 457.920 438.744 ;
    END
  END tap[16]
  PIN tap[17]
    DIRECTION INPUT ;
    USE SIGNAL ;
    PORT
      LAYER M4 ;
        RECT 457.728 438.816 457.920 438.840 ;
    END
  END tap[17]
  PIN tap[18]
    DIRECTION INPUT ;
    USE SIGNAL ;
    PORT
      LAYER M4 ;
        RECT 457.728 438.912 457.920 438.936 ;
    END
  END tap[18]
  PIN tap[19]
    DIRECTION INPUT ;
    USE SIGNAL ;
    PORT
      LAYER M4 ;
        RECT 457.728 439.008 457.920 439.032 ;
    END
  END tap[19]
  PIN tap[20]
    DIRECTION INPUT ;
    USE SIGNAL ;
    PORT
      LAYER M4 ;
        RECT 457.728 439.104 457.920 439.128 ;
    END
  END tap[20]
  PIN tap[21]
    DIRECTION INPUT ;
    USE SIGNAL ;
    PORT
      LAYER M4 ;
        RECT 457.728 439.200 457.920 439.224 ;
    END
  END tap[21]
  PIN tap[22]
    DIRECTION INPUT ;
    USE SIGNAL ;
    PORT
      LAYER M4 ;
        RECT 457.728 439.296 457.920 439.320 ;
    END
  END tap[22]
  PIN tap[23]
    DIRECTION INPUT ;
    USE SIGNAL ;
    PORT
      LAYER M4 ;
        RECT 457.728 439.392 457.920 439.416 ;
    END
  END tap[23]
  PIN tap[24]
    DIRECTION INPUT ;
    USE SIGNAL ;
    PORT
      LAYER M4 ;
        RECT 457.728 439.488 457.920 439.512 ;
    END
  END tap[24]
  PIN tap[25]
    DIRECTION INPUT ;
    USE SIGNAL ;
    PORT
      LAYER M4 ;
        RECT 457.728 439.584 457.920 439.608 ;
    END
  END tap[25]
  PIN tap[26]
    DIRECTION INPUT ;
    USE SIGNAL ;
    PORT
      LAYER M4 ;
        RECT 457.728 439.680 457.920 439.704 ;
    END
  END tap[26]
  PIN tap[27]
    DIRECTION INPUT ;
    USE SIGNAL ;
    PORT
      LAYER M4 ;
        RECT 457.728 439.776 457.920 439.800 ;
    END
  END tap[27]
  PIN tap[28]
    DIRECTION INPUT ;
    USE SIGNAL ;
    PORT
      LAYER M4 ;
        RECT 457.728 439.872 457.920 439.896 ;
    END
  END tap[28]
  PIN tap[29]
    DIRECTION INPUT ;
    USE SIGNAL ;
    PORT
      LAYER M4 ;
        RECT 457.728 439.968 457.920 439.992 ;
    END
  END tap[29]
  PIN tap[30]
    DIRECTION INPUT ;
    USE SIGNAL ;
    PORT
      LAYER M4 ;
        RECT 457.728 440.064 457.920 440.088 ;
    END
  END tap[30]
  PIN tap[31]
    DIRECTION INPUT ;
    USE SIGNAL ;
    PORT
      LAYER M4 ;
        RECT 457.728 440.160 457.920 440.184 ;
    END
  END tap[31]
  PIN tap[32]
    DIRECTION INPUT ;
    USE SIGNAL ;
    PORT
      LAYER M4 ;
        RECT 457.728 440.256 457.920 440.280 ;
    END
  END tap[32]
  PIN tap[33]
    DIRECTION INPUT ;
    USE SIGNAL ;
    PORT
      LAYER M4 ;
        RECT 457.728 440.352 457.920 440.376 ;
    END
  END tap[33]
  PIN tap[34]
    DIRECTION INPUT ;
    USE SIGNAL ;
    PORT
      LAYER M4 ;
        RECT 457.728 440.448 457.920 440.472 ;
    END
  END tap[34]
  PIN tap[35]
    DIRECTION INPUT ;
    USE SIGNAL ;
    PORT
      LAYER M4 ;
        RECT 457.728 440.544 457.920 440.568 ;
    END
  END tap[35]
  PIN tap[36]
    DIRECTION INPUT ;
    USE SIGNAL ;
    PORT
      LAYER M4 ;
        RECT 457.728 440.640 457.920 440.664 ;
    END
  END tap[36]
  PIN tap[37]
    DIRECTION INPUT ;
    USE SIGNAL ;
    PORT
      LAYER M4 ;
        RECT 457.728 440.736 457.920 440.760 ;
    END
  END tap[37]
  PIN tap[38]
    DIRECTION INPUT ;
    USE SIGNAL ;
    PORT
      LAYER M4 ;
        RECT 457.728 440.832 457.920 440.856 ;
    END
  END tap[38]
  PIN tap[39]
    DIRECTION INPUT ;
    USE SIGNAL ;
    PORT
      LAYER M4 ;
        RECT 457.728 440.928 457.920 440.952 ;
    END
  END tap[39]
  PIN tap[40]
    DIRECTION INPUT ;
    USE SIGNAL ;
    PORT
      LAYER M4 ;
        RECT 457.728 441.024 457.920 441.048 ;
    END
  END tap[40]
  PIN tap[41]
    DIRECTION INPUT ;
    USE SIGNAL ;
    PORT
      LAYER M4 ;
        RECT 457.728 441.120 457.920 441.144 ;
    END
  END tap[41]
  PIN tap[42]
    DIRECTION INPUT ;
    USE SIGNAL ;
    PORT
      LAYER M4 ;
        RECT 457.728 441.216 457.920 441.240 ;
    END
  END tap[42]
  PIN tap[43]
    DIRECTION INPUT ;
    USE SIGNAL ;
    PORT
      LAYER M4 ;
        RECT 457.728 441.312 457.920 441.336 ;
    END
  END tap[43]
  PIN tap[44]
    DIRECTION INPUT ;
    USE SIGNAL ;
    PORT
      LAYER M4 ;
        RECT 457.728 441.408 457.920 441.432 ;
    END
  END tap[44]
  PIN tap[45]
    DIRECTION INPUT ;
    USE SIGNAL ;
    PORT
      LAYER M4 ;
        RECT 457.728 441.504 457.920 441.528 ;
    END
  END tap[45]
  PIN tap[46]
    DIRECTION INPUT ;
    USE SIGNAL ;
    PORT
      LAYER M4 ;
        RECT 457.728 441.600 457.920 441.624 ;
    END
  END tap[46]
  PIN tap[47]
    DIRECTION INPUT ;
    USE SIGNAL ;
    PORT
      LAYER M4 ;
        RECT 457.728 441.696 457.920 441.720 ;
    END
  END tap[47]
  PIN tap[48]
    DIRECTION INPUT ;
    USE SIGNAL ;
    PORT
      LAYER M4 ;
        RECT 457.728 441.792 457.920 441.816 ;
    END
  END tap[48]
  PIN tap[49]
    DIRECTION INPUT ;
    USE SIGNAL ;
    PORT
      LAYER M4 ;
        RECT 457.728 441.888 457.920 441.912 ;
    END
  END tap[49]
  PIN tap[50]
    DIRECTION INPUT ;
    USE SIGNAL ;
    PORT
      LAYER M4 ;
        RECT 457.728 441.984 457.920 442.008 ;
    END
  END tap[50]
  PIN tap[51]
    DIRECTION INPUT ;
    USE SIGNAL ;
    PORT
      LAYER M4 ;
        RECT 457.728 442.080 457.920 442.104 ;
    END
  END tap[51]
  PIN tap[52]
    DIRECTION INPUT ;
    USE SIGNAL ;
    PORT
      LAYER M4 ;
        RECT 457.728 442.176 457.920 442.200 ;
    END
  END tap[52]
  PIN tap[53]
    DIRECTION INPUT ;
    USE SIGNAL ;
    PORT
      LAYER M4 ;
        RECT 457.728 442.272 457.920 442.296 ;
    END
  END tap[53]
  PIN tap[54]
    DIRECTION INPUT ;
    USE SIGNAL ;
    PORT
      LAYER M4 ;
        RECT 457.728 442.368 457.920 442.392 ;
    END
  END tap[54]
  PIN tap[55]
    DIRECTION INPUT ;
    USE SIGNAL ;
    PORT
      LAYER M4 ;
        RECT 457.728 442.464 457.920 442.488 ;
    END
  END tap[55]
  PIN tap[56]
    DIRECTION INPUT ;
    USE SIGNAL ;
    PORT
      LAYER M4 ;
        RECT 457.728 442.560 457.920 442.584 ;
    END
  END tap[56]
  PIN tap[57]
    DIRECTION INPUT ;
    USE SIGNAL ;
    PORT
      LAYER M4 ;
        RECT 457.728 442.656 457.920 442.680 ;
    END
  END tap[57]
  PIN tap[58]
    DIRECTION INPUT ;
    USE SIGNAL ;
    PORT
      LAYER M4 ;
        RECT 457.728 442.752 457.920 442.776 ;
    END
  END tap[58]
  PIN tap[59]
    DIRECTION INPUT ;
    USE SIGNAL ;
    PORT
      LAYER M4 ;
        RECT 457.728 442.848 457.920 442.872 ;
    END
  END tap[59]
  PIN tap[60]
    DIRECTION INPUT ;
    USE SIGNAL ;
    PORT
      LAYER M4 ;
        RECT 457.728 442.944 457.920 442.968 ;
    END
  END tap[60]
  PIN tap[61]
    DIRECTION INPUT ;
    USE SIGNAL ;
    PORT
      LAYER M4 ;
        RECT 457.728 443.040 457.920 443.064 ;
    END
  END tap[61]
  PIN tap[62]
    DIRECTION INPUT ;
    USE SIGNAL ;
    PORT
      LAYER M4 ;
        RECT 457.728 443.136 457.920 443.160 ;
    END
  END tap[62]
  PIN tap[63]
    DIRECTION INPUT ;
    USE SIGNAL ;
    PORT
      LAYER M4 ;
        RECT 457.728 443.232 457.920 443.256 ;
    END
  END tap[63]
  PIN tap[64]
    DIRECTION INPUT ;
    USE SIGNAL ;
    PORT
      LAYER M4 ;
        RECT 457.728 443.328 457.920 443.352 ;
    END
  END tap[64]
  PIN tap[65]
    DIRECTION INPUT ;
    USE SIGNAL ;
    PORT
      LAYER M4 ;
        RECT 457.728 443.424 457.920 443.448 ;
    END
  END tap[65]
  PIN tap[66]
    DIRECTION INPUT ;
    USE SIGNAL ;
    PORT
      LAYER M4 ;
        RECT 457.728 443.520 457.920 443.544 ;
    END
  END tap[66]
  PIN tap[67]
    DIRECTION INPUT ;
    USE SIGNAL ;
    PORT
      LAYER M4 ;
        RECT 457.728 443.616 457.920 443.640 ;
    END
  END tap[67]
  PIN tap[68]
    DIRECTION INPUT ;
    USE SIGNAL ;
    PORT
      LAYER M4 ;
        RECT 457.728 443.712 457.920 443.736 ;
    END
  END tap[68]
  PIN tap[69]
    DIRECTION INPUT ;
    USE SIGNAL ;
    PORT
      LAYER M4 ;
        RECT 457.728 443.808 457.920 443.832 ;
    END
  END tap[69]
  PIN tap[70]
    DIRECTION INPUT ;
    USE SIGNAL ;
    PORT
      LAYER M4 ;
        RECT 457.728 443.904 457.920 443.928 ;
    END
  END tap[70]
  PIN tap[71]
    DIRECTION INPUT ;
    USE SIGNAL ;
    PORT
      LAYER M4 ;
        RECT 457.728 444.000 457.920 444.024 ;
    END
  END tap[71]
  PIN tap[72]
    DIRECTION INPUT ;
    USE SIGNAL ;
    PORT
      LAYER M4 ;
        RECT 457.728 444.096 457.920 444.120 ;
    END
  END tap[72]
  PIN tap[73]
    DIRECTION INPUT ;
    USE SIGNAL ;
    PORT
      LAYER M4 ;
        RECT 457.728 444.192 457.920 444.216 ;
    END
  END tap[73]
  PIN tap[74]
    DIRECTION INPUT ;
    USE SIGNAL ;
    PORT
      LAYER M4 ;
        RECT 457.728 444.288 457.920 444.312 ;
    END
  END tap[74]
  PIN tap[75]
    DIRECTION INPUT ;
    USE SIGNAL ;
    PORT
      LAYER M4 ;
        RECT 457.728 444.384 457.920 444.408 ;
    END
  END tap[75]
  PIN tap[76]
    DIRECTION INPUT ;
    USE SIGNAL ;
    PORT
      LAYER M4 ;
        RECT 457.728 444.480 457.920 444.504 ;
    END
  END tap[76]
  PIN tap[77]
    DIRECTION INPUT ;
    USE SIGNAL ;
    PORT
      LAYER M4 ;
        RECT 457.728 444.576 457.920 444.600 ;
    END
  END tap[77]
  PIN tap[78]
    DIRECTION INPUT ;
    USE SIGNAL ;
    PORT
      LAYER M4 ;
        RECT 457.728 444.672 457.920 444.696 ;
    END
  END tap[78]
  PIN tap[79]
    DIRECTION INPUT ;
    USE SIGNAL ;
    PORT
      LAYER M4 ;
        RECT 457.728 444.768 457.920 444.792 ;
    END
  END tap[79]
  PIN tap[80]
    DIRECTION INPUT ;
    USE SIGNAL ;
    PORT
      LAYER M4 ;
        RECT 457.728 444.864 457.920 444.888 ;
    END
  END tap[80]
  PIN tap[81]
    DIRECTION INPUT ;
    USE SIGNAL ;
    PORT
      LAYER M4 ;
        RECT 457.728 444.960 457.920 444.984 ;
    END
  END tap[81]
  PIN tap[82]
    DIRECTION INPUT ;
    USE SIGNAL ;
    PORT
      LAYER M4 ;
        RECT 457.728 445.056 457.920 445.080 ;
    END
  END tap[82]
  PIN tap[83]
    DIRECTION INPUT ;
    USE SIGNAL ;
    PORT
      LAYER M4 ;
        RECT 457.728 445.152 457.920 445.176 ;
    END
  END tap[83]
  PIN tap[84]
    DIRECTION INPUT ;
    USE SIGNAL ;
    PORT
      LAYER M4 ;
        RECT 457.728 445.248 457.920 445.272 ;
    END
  END tap[84]
  PIN tap[85]
    DIRECTION INPUT ;
    USE SIGNAL ;
    PORT
      LAYER M4 ;
        RECT 457.728 445.344 457.920 445.368 ;
    END
  END tap[85]
  PIN tap[86]
    DIRECTION INPUT ;
    USE SIGNAL ;
    PORT
      LAYER M4 ;
        RECT 457.728 445.440 457.920 445.464 ;
    END
  END tap[86]
  PIN tap[87]
    DIRECTION INPUT ;
    USE SIGNAL ;
    PORT
      LAYER M4 ;
        RECT 457.728 445.536 457.920 445.560 ;
    END
  END tap[87]
  PIN tap[88]
    DIRECTION INPUT ;
    USE SIGNAL ;
    PORT
      LAYER M4 ;
        RECT 457.728 445.632 457.920 445.656 ;
    END
  END tap[88]
  PIN tap[89]
    DIRECTION INPUT ;
    USE SIGNAL ;
    PORT
      LAYER M4 ;
        RECT 457.728 445.728 457.920 445.752 ;
    END
  END tap[89]
  PIN tap[90]
    DIRECTION INPUT ;
    USE SIGNAL ;
    PORT
      LAYER M4 ;
        RECT 457.728 445.824 457.920 445.848 ;
    END
  END tap[90]
  PIN tap[91]
    DIRECTION INPUT ;
    USE SIGNAL ;
    PORT
      LAYER M4 ;
        RECT 457.728 445.920 457.920 445.944 ;
    END
  END tap[91]
  PIN tap[92]
    DIRECTION INPUT ;
    USE SIGNAL ;
    PORT
      LAYER M4 ;
        RECT 457.728 446.016 457.920 446.040 ;
    END
  END tap[92]
  PIN tap[93]
    DIRECTION INPUT ;
    USE SIGNAL ;
    PORT
      LAYER M4 ;
        RECT 457.728 446.112 457.920 446.136 ;
    END
  END tap[93]
  PIN tap[94]
    DIRECTION INPUT ;
    USE SIGNAL ;
    PORT
      LAYER M4 ;
        RECT 457.728 446.208 457.920 446.232 ;
    END
  END tap[94]
  PIN tap[95]
    DIRECTION INPUT ;
    USE SIGNAL ;
    PORT
      LAYER M4 ;
        RECT 457.728 446.304 457.920 446.328 ;
    END
  END tap[95]
  PIN tap[96]
    DIRECTION INPUT ;
    USE SIGNAL ;
    PORT
      LAYER M4 ;
        RECT 457.728 446.400 457.920 446.424 ;
    END
  END tap[96]
  PIN tap[97]
    DIRECTION INPUT ;
    USE SIGNAL ;
    PORT
      LAYER M4 ;
        RECT 457.728 446.496 457.920 446.520 ;
    END
  END tap[97]
  PIN tap[98]
    DIRECTION INPUT ;
    USE SIGNAL ;
    PORT
      LAYER M4 ;
        RECT 457.728 446.592 457.920 446.616 ;
    END
  END tap[98]
  PIN tap[99]
    DIRECTION INPUT ;
    USE SIGNAL ;
    PORT
      LAYER M4 ;
        RECT 457.728 446.688 457.920 446.712 ;
    END
  END tap[99]
  PIN tap[100]
    DIRECTION INPUT ;
    USE SIGNAL ;
    PORT
      LAYER M4 ;
        RECT 457.728 446.784 457.920 446.808 ;
    END
  END tap[100]
  PIN tap[101]
    DIRECTION INPUT ;
    USE SIGNAL ;
    PORT
      LAYER M4 ;
        RECT 457.728 446.880 457.920 446.904 ;
    END
  END tap[101]
  PIN tap[102]
    DIRECTION INPUT ;
    USE SIGNAL ;
    PORT
      LAYER M4 ;
        RECT 457.728 446.976 457.920 447.000 ;
    END
  END tap[102]
  PIN tap[103]
    DIRECTION INPUT ;
    USE SIGNAL ;
    PORT
      LAYER M4 ;
        RECT 457.728 447.072 457.920 447.096 ;
    END
  END tap[103]
  PIN tap[104]
    DIRECTION INPUT ;
    USE SIGNAL ;
    PORT
      LAYER M4 ;
        RECT 457.728 447.168 457.920 447.192 ;
    END
  END tap[104]
  PIN tap[105]
    DIRECTION INPUT ;
    USE SIGNAL ;
    PORT
      LAYER M4 ;
        RECT 457.728 447.264 457.920 447.288 ;
    END
  END tap[105]
  PIN tap[106]
    DIRECTION INPUT ;
    USE SIGNAL ;
    PORT
      LAYER M4 ;
        RECT 457.728 447.360 457.920 447.384 ;
    END
  END tap[106]
  PIN tap[107]
    DIRECTION INPUT ;
    USE SIGNAL ;
    PORT
      LAYER M4 ;
        RECT 457.728 447.456 457.920 447.480 ;
    END
  END tap[107]
  PIN tap[108]
    DIRECTION INPUT ;
    USE SIGNAL ;
    PORT
      LAYER M4 ;
        RECT 457.728 447.552 457.920 447.576 ;
    END
  END tap[108]
  PIN tap[109]
    DIRECTION INPUT ;
    USE SIGNAL ;
    PORT
      LAYER M4 ;
        RECT 457.728 447.648 457.920 447.672 ;
    END
  END tap[109]
  PIN tap[110]
    DIRECTION INPUT ;
    USE SIGNAL ;
    PORT
      LAYER M4 ;
        RECT 457.728 447.744 457.920 447.768 ;
    END
  END tap[110]
  PIN tap[111]
    DIRECTION INPUT ;
    USE SIGNAL ;
    PORT
      LAYER M4 ;
        RECT 457.728 447.840 457.920 447.864 ;
    END
  END tap[111]
  PIN tap[112]
    DIRECTION INPUT ;
    USE SIGNAL ;
    PORT
      LAYER M4 ;
        RECT 457.728 447.936 457.920 447.960 ;
    END
  END tap[112]
  PIN tap[113]
    DIRECTION INPUT ;
    USE SIGNAL ;
    PORT
      LAYER M4 ;
        RECT 457.728 448.032 457.920 448.056 ;
    END
  END tap[113]
  PIN tap[114]
    DIRECTION INPUT ;
    USE SIGNAL ;
    PORT
      LAYER M4 ;
        RECT 457.728 448.128 457.920 448.152 ;
    END
  END tap[114]
  PIN tap[115]
    DIRECTION INPUT ;
    USE SIGNAL ;
    PORT
      LAYER M4 ;
        RECT 457.728 448.224 457.920 448.248 ;
    END
  END tap[115]
  PIN tap[116]
    DIRECTION INPUT ;
    USE SIGNAL ;
    PORT
      LAYER M4 ;
        RECT 457.728 448.320 457.920 448.344 ;
    END
  END tap[116]
  PIN tap[117]
    DIRECTION INPUT ;
    USE SIGNAL ;
    PORT
      LAYER M4 ;
        RECT 457.728 448.416 457.920 448.440 ;
    END
  END tap[117]
  PIN tap[118]
    DIRECTION INPUT ;
    USE SIGNAL ;
    PORT
      LAYER M4 ;
        RECT 457.728 448.512 457.920 448.536 ;
    END
  END tap[118]
  PIN tap[119]
    DIRECTION INPUT ;
    USE SIGNAL ;
    PORT
      LAYER M4 ;
        RECT 457.728 448.608 457.920 448.632 ;
    END
  END tap[119]
  PIN tap[120]
    DIRECTION INPUT ;
    USE SIGNAL ;
    PORT
      LAYER M4 ;
        RECT 457.728 448.704 457.920 448.728 ;
    END
  END tap[120]
  PIN tap[121]
    DIRECTION INPUT ;
    USE SIGNAL ;
    PORT
      LAYER M4 ;
        RECT 457.728 448.800 457.920 448.824 ;
    END
  END tap[121]
  PIN tap[122]
    DIRECTION INPUT ;
    USE SIGNAL ;
    PORT
      LAYER M4 ;
        RECT 457.728 448.896 457.920 448.920 ;
    END
  END tap[122]
  PIN tap[123]
    DIRECTION INPUT ;
    USE SIGNAL ;
    PORT
      LAYER M4 ;
        RECT 457.728 448.992 457.920 449.016 ;
    END
  END tap[123]
  PIN tap[124]
    DIRECTION INPUT ;
    USE SIGNAL ;
    PORT
      LAYER M4 ;
        RECT 457.728 449.088 457.920 449.112 ;
    END
  END tap[124]
  PIN tap[125]
    DIRECTION INPUT ;
    USE SIGNAL ;
    PORT
      LAYER M4 ;
        RECT 457.728 449.184 457.920 449.208 ;
    END
  END tap[125]
  PIN tap[126]
    DIRECTION INPUT ;
    USE SIGNAL ;
    PORT
      LAYER M4 ;
        RECT 457.728 449.280 457.920 449.304 ;
    END
  END tap[126]
  PIN tap[127]
    DIRECTION INPUT ;
    USE SIGNAL ;
    PORT
      LAYER M4 ;
        RECT 457.728 449.376 457.920 449.400 ;
    END
  END tap[127]
  PIN tap[128]
    DIRECTION INPUT ;
    USE SIGNAL ;
    PORT
      LAYER M4 ;
        RECT 457.728 449.472 457.920 449.496 ;
    END
  END tap[128]
  PIN tap[129]
    DIRECTION INPUT ;
    USE SIGNAL ;
    PORT
      LAYER M4 ;
        RECT 457.728 449.568 457.920 449.592 ;
    END
  END tap[129]
  PIN tap[130]
    DIRECTION INPUT ;
    USE SIGNAL ;
    PORT
      LAYER M4 ;
        RECT 457.728 449.664 457.920 449.688 ;
    END
  END tap[130]
  PIN tap[131]
    DIRECTION INPUT ;
    USE SIGNAL ;
    PORT
      LAYER M4 ;
        RECT 457.728 449.760 457.920 449.784 ;
    END
  END tap[131]
  PIN tap[132]
    DIRECTION INPUT ;
    USE SIGNAL ;
    PORT
      LAYER M4 ;
        RECT 457.728 449.856 457.920 449.880 ;
    END
  END tap[132]
  PIN tap[133]
    DIRECTION INPUT ;
    USE SIGNAL ;
    PORT
      LAYER M4 ;
        RECT 457.728 449.952 457.920 449.976 ;
    END
  END tap[133]
  PIN tap[134]
    DIRECTION INPUT ;
    USE SIGNAL ;
    PORT
      LAYER M4 ;
        RECT 457.728 450.048 457.920 450.072 ;
    END
  END tap[134]
  PIN tap[135]
    DIRECTION INPUT ;
    USE SIGNAL ;
    PORT
      LAYER M4 ;
        RECT 457.728 450.144 457.920 450.168 ;
    END
  END tap[135]
  PIN tap[136]
    DIRECTION INPUT ;
    USE SIGNAL ;
    PORT
      LAYER M4 ;
        RECT 457.728 450.240 457.920 450.264 ;
    END
  END tap[136]
  PIN tap[137]
    DIRECTION INPUT ;
    USE SIGNAL ;
    PORT
      LAYER M4 ;
        RECT 457.728 450.336 457.920 450.360 ;
    END
  END tap[137]
  PIN tap[138]
    DIRECTION INPUT ;
    USE SIGNAL ;
    PORT
      LAYER M4 ;
        RECT 457.728 450.432 457.920 450.456 ;
    END
  END tap[138]
  PIN tap[139]
    DIRECTION INPUT ;
    USE SIGNAL ;
    PORT
      LAYER M4 ;
        RECT 457.728 450.528 457.920 450.552 ;
    END
  END tap[139]
  PIN tap[140]
    DIRECTION INPUT ;
    USE SIGNAL ;
    PORT
      LAYER M4 ;
        RECT 457.728 450.624 457.920 450.648 ;
    END
  END tap[140]
  PIN tap[141]
    DIRECTION INPUT ;
    USE SIGNAL ;
    PORT
      LAYER M4 ;
        RECT 457.728 450.720 457.920 450.744 ;
    END
  END tap[141]
  PIN tap[142]
    DIRECTION INPUT ;
    USE SIGNAL ;
    PORT
      LAYER M4 ;
        RECT 457.728 450.816 457.920 450.840 ;
    END
  END tap[142]
  PIN tap[143]
    DIRECTION INPUT ;
    USE SIGNAL ;
    PORT
      LAYER M4 ;
        RECT 457.728 450.912 457.920 450.936 ;
    END
  END tap[143]
  PIN tap[144]
    DIRECTION INPUT ;
    USE SIGNAL ;
    PORT
      LAYER M4 ;
        RECT 457.728 451.008 457.920 451.032 ;
    END
  END tap[144]
  PIN tap[145]
    DIRECTION INPUT ;
    USE SIGNAL ;
    PORT
      LAYER M4 ;
        RECT 457.728 451.104 457.920 451.128 ;
    END
  END tap[145]
  PIN tap[146]
    DIRECTION INPUT ;
    USE SIGNAL ;
    PORT
      LAYER M4 ;
        RECT 457.728 451.200 457.920 451.224 ;
    END
  END tap[146]
  PIN tap[147]
    DIRECTION INPUT ;
    USE SIGNAL ;
    PORT
      LAYER M4 ;
        RECT 457.728 451.296 457.920 451.320 ;
    END
  END tap[147]
  PIN tap[148]
    DIRECTION INPUT ;
    USE SIGNAL ;
    PORT
      LAYER M4 ;
        RECT 457.728 451.392 457.920 451.416 ;
    END
  END tap[148]
  PIN tap[149]
    DIRECTION INPUT ;
    USE SIGNAL ;
    PORT
      LAYER M4 ;
        RECT 457.728 451.488 457.920 451.512 ;
    END
  END tap[149]
  PIN tap[150]
    DIRECTION INPUT ;
    USE SIGNAL ;
    PORT
      LAYER M4 ;
        RECT 457.728 451.584 457.920 451.608 ;
    END
  END tap[150]
  PIN tap[151]
    DIRECTION INPUT ;
    USE SIGNAL ;
    PORT
      LAYER M4 ;
        RECT 457.728 451.680 457.920 451.704 ;
    END
  END tap[151]
  PIN tap[152]
    DIRECTION INPUT ;
    USE SIGNAL ;
    PORT
      LAYER M4 ;
        RECT 457.728 451.776 457.920 451.800 ;
    END
  END tap[152]
  PIN tap[153]
    DIRECTION INPUT ;
    USE SIGNAL ;
    PORT
      LAYER M4 ;
        RECT 457.728 451.872 457.920 451.896 ;
    END
  END tap[153]
  PIN tap[154]
    DIRECTION INPUT ;
    USE SIGNAL ;
    PORT
      LAYER M4 ;
        RECT 457.728 451.968 457.920 451.992 ;
    END
  END tap[154]
  PIN tap[155]
    DIRECTION INPUT ;
    USE SIGNAL ;
    PORT
      LAYER M4 ;
        RECT 457.728 452.064 457.920 452.088 ;
    END
  END tap[155]
  PIN tap[156]
    DIRECTION INPUT ;
    USE SIGNAL ;
    PORT
      LAYER M4 ;
        RECT 457.728 452.160 457.920 452.184 ;
    END
  END tap[156]
  PIN tap[157]
    DIRECTION INPUT ;
    USE SIGNAL ;
    PORT
      LAYER M4 ;
        RECT 457.728 452.256 457.920 452.280 ;
    END
  END tap[157]
  PIN tap[158]
    DIRECTION INPUT ;
    USE SIGNAL ;
    PORT
      LAYER M4 ;
        RECT 457.728 452.352 457.920 452.376 ;
    END
  END tap[158]
  PIN tap[159]
    DIRECTION INPUT ;
    USE SIGNAL ;
    PORT
      LAYER M4 ;
        RECT 457.728 452.448 457.920 452.472 ;
    END
  END tap[159]
  PIN tap[160]
    DIRECTION INPUT ;
    USE SIGNAL ;
    PORT
      LAYER M4 ;
        RECT 457.728 452.544 457.920 452.568 ;
    END
  END tap[160]
  PIN tap[161]
    DIRECTION INPUT ;
    USE SIGNAL ;
    PORT
      LAYER M4 ;
        RECT 457.728 452.640 457.920 452.664 ;
    END
  END tap[161]
  PIN tap[162]
    DIRECTION INPUT ;
    USE SIGNAL ;
    PORT
      LAYER M4 ;
        RECT 457.728 452.736 457.920 452.760 ;
    END
  END tap[162]
  PIN tap[163]
    DIRECTION INPUT ;
    USE SIGNAL ;
    PORT
      LAYER M4 ;
        RECT 457.728 452.832 457.920 452.856 ;
    END
  END tap[163]
  PIN tap[164]
    DIRECTION INPUT ;
    USE SIGNAL ;
    PORT
      LAYER M4 ;
        RECT 457.728 452.928 457.920 452.952 ;
    END
  END tap[164]
  PIN tap[165]
    DIRECTION INPUT ;
    USE SIGNAL ;
    PORT
      LAYER M4 ;
        RECT 457.728 453.024 457.920 453.048 ;
    END
  END tap[165]
  PIN tap[166]
    DIRECTION INPUT ;
    USE SIGNAL ;
    PORT
      LAYER M4 ;
        RECT 457.728 453.120 457.920 453.144 ;
    END
  END tap[166]
  PIN tap[167]
    DIRECTION INPUT ;
    USE SIGNAL ;
    PORT
      LAYER M4 ;
        RECT 457.728 453.216 457.920 453.240 ;
    END
  END tap[167]
  PIN tap[168]
    DIRECTION INPUT ;
    USE SIGNAL ;
    PORT
      LAYER M4 ;
        RECT 457.728 453.312 457.920 453.336 ;
    END
  END tap[168]
  PIN tap[169]
    DIRECTION INPUT ;
    USE SIGNAL ;
    PORT
      LAYER M4 ;
        RECT 457.728 453.408 457.920 453.432 ;
    END
  END tap[169]
  PIN tap[170]
    DIRECTION INPUT ;
    USE SIGNAL ;
    PORT
      LAYER M4 ;
        RECT 457.728 453.504 457.920 453.528 ;
    END
  END tap[170]
  PIN tap[171]
    DIRECTION INPUT ;
    USE SIGNAL ;
    PORT
      LAYER M4 ;
        RECT 457.728 453.600 457.920 453.624 ;
    END
  END tap[171]
  PIN tap[172]
    DIRECTION INPUT ;
    USE SIGNAL ;
    PORT
      LAYER M4 ;
        RECT 457.728 453.696 457.920 453.720 ;
    END
  END tap[172]
  PIN tap[173]
    DIRECTION INPUT ;
    USE SIGNAL ;
    PORT
      LAYER M4 ;
        RECT 457.728 453.792 457.920 453.816 ;
    END
  END tap[173]
  PIN tap[174]
    DIRECTION INPUT ;
    USE SIGNAL ;
    PORT
      LAYER M4 ;
        RECT 457.728 453.888 457.920 453.912 ;
    END
  END tap[174]
  PIN tap[175]
    DIRECTION INPUT ;
    USE SIGNAL ;
    PORT
      LAYER M4 ;
        RECT 457.728 453.984 457.920 454.008 ;
    END
  END tap[175]
  PIN tap[176]
    DIRECTION INPUT ;
    USE SIGNAL ;
    PORT
      LAYER M4 ;
        RECT 457.728 454.080 457.920 454.104 ;
    END
  END tap[176]
  PIN tap[177]
    DIRECTION INPUT ;
    USE SIGNAL ;
    PORT
      LAYER M4 ;
        RECT 457.728 454.176 457.920 454.200 ;
    END
  END tap[177]
  PIN tap[178]
    DIRECTION INPUT ;
    USE SIGNAL ;
    PORT
      LAYER M4 ;
        RECT 457.728 454.272 457.920 454.296 ;
    END
  END tap[178]
  PIN tap[179]
    DIRECTION INPUT ;
    USE SIGNAL ;
    PORT
      LAYER M4 ;
        RECT 457.728 454.368 457.920 454.392 ;
    END
  END tap[179]
  PIN tap[180]
    DIRECTION INPUT ;
    USE SIGNAL ;
    PORT
      LAYER M4 ;
        RECT 457.728 454.464 457.920 454.488 ;
    END
  END tap[180]
  PIN tap[181]
    DIRECTION INPUT ;
    USE SIGNAL ;
    PORT
      LAYER M4 ;
        RECT 457.728 454.560 457.920 454.584 ;
    END
  END tap[181]
  PIN tap[182]
    DIRECTION INPUT ;
    USE SIGNAL ;
    PORT
      LAYER M4 ;
        RECT 457.728 454.656 457.920 454.680 ;
    END
  END tap[182]
  PIN tap[183]
    DIRECTION INPUT ;
    USE SIGNAL ;
    PORT
      LAYER M4 ;
        RECT 457.728 454.752 457.920 454.776 ;
    END
  END tap[183]
  PIN tap[184]
    DIRECTION INPUT ;
    USE SIGNAL ;
    PORT
      LAYER M4 ;
        RECT 457.728 454.848 457.920 454.872 ;
    END
  END tap[184]
  PIN tap[185]
    DIRECTION INPUT ;
    USE SIGNAL ;
    PORT
      LAYER M4 ;
        RECT 457.728 454.944 457.920 454.968 ;
    END
  END tap[185]
  PIN tap[186]
    DIRECTION INPUT ;
    USE SIGNAL ;
    PORT
      LAYER M4 ;
        RECT 457.728 455.040 457.920 455.064 ;
    END
  END tap[186]
  PIN tap[187]
    DIRECTION INPUT ;
    USE SIGNAL ;
    PORT
      LAYER M4 ;
        RECT 457.728 455.136 457.920 455.160 ;
    END
  END tap[187]
  PIN tap[188]
    DIRECTION INPUT ;
    USE SIGNAL ;
    PORT
      LAYER M4 ;
        RECT 457.728 455.232 457.920 455.256 ;
    END
  END tap[188]
  PIN tap[189]
    DIRECTION INPUT ;
    USE SIGNAL ;
    PORT
      LAYER M4 ;
        RECT 457.728 455.328 457.920 455.352 ;
    END
  END tap[189]
  PIN tap[190]
    DIRECTION INPUT ;
    USE SIGNAL ;
    PORT
      LAYER M4 ;
        RECT 457.728 455.424 457.920 455.448 ;
    END
  END tap[190]
  PIN tap[191]
    DIRECTION INPUT ;
    USE SIGNAL ;
    PORT
      LAYER M4 ;
        RECT 457.728 455.520 457.920 455.544 ;
    END
  END tap[191]
  PIN tap[192]
    DIRECTION INPUT ;
    USE SIGNAL ;
    PORT
      LAYER M4 ;
        RECT 457.728 455.616 457.920 455.640 ;
    END
  END tap[192]
  PIN tap[193]
    DIRECTION INPUT ;
    USE SIGNAL ;
    PORT
      LAYER M4 ;
        RECT 457.728 455.712 457.920 455.736 ;
    END
  END tap[193]
  PIN tap[194]
    DIRECTION INPUT ;
    USE SIGNAL ;
    PORT
      LAYER M4 ;
        RECT 457.728 455.808 457.920 455.832 ;
    END
  END tap[194]
  PIN tap[195]
    DIRECTION INPUT ;
    USE SIGNAL ;
    PORT
      LAYER M4 ;
        RECT 457.728 455.904 457.920 455.928 ;
    END
  END tap[195]
  PIN tap[196]
    DIRECTION INPUT ;
    USE SIGNAL ;
    PORT
      LAYER M4 ;
        RECT 457.728 456.000 457.920 456.024 ;
    END
  END tap[196]
  PIN tap[197]
    DIRECTION INPUT ;
    USE SIGNAL ;
    PORT
      LAYER M4 ;
        RECT 457.728 456.096 457.920 456.120 ;
    END
  END tap[197]
  PIN tap[198]
    DIRECTION INPUT ;
    USE SIGNAL ;
    PORT
      LAYER M4 ;
        RECT 457.728 456.192 457.920 456.216 ;
    END
  END tap[198]
  PIN tap[199]
    DIRECTION INPUT ;
    USE SIGNAL ;
    PORT
      LAYER M4 ;
        RECT 457.728 456.288 457.920 456.312 ;
    END
  END tap[199]
  PIN tap[200]
    DIRECTION INPUT ;
    USE SIGNAL ;
    PORT
      LAYER M4 ;
        RECT 457.728 456.384 457.920 456.408 ;
    END
  END tap[200]
  PIN tap[201]
    DIRECTION INPUT ;
    USE SIGNAL ;
    PORT
      LAYER M4 ;
        RECT 457.728 456.480 457.920 456.504 ;
    END
  END tap[201]
  PIN tap[202]
    DIRECTION INPUT ;
    USE SIGNAL ;
    PORT
      LAYER M4 ;
        RECT 457.728 456.576 457.920 456.600 ;
    END
  END tap[202]
  PIN tap[203]
    DIRECTION INPUT ;
    USE SIGNAL ;
    PORT
      LAYER M4 ;
        RECT 457.728 456.672 457.920 456.696 ;
    END
  END tap[203]
  PIN tap[204]
    DIRECTION INPUT ;
    USE SIGNAL ;
    PORT
      LAYER M4 ;
        RECT 457.728 456.768 457.920 456.792 ;
    END
  END tap[204]
  PIN tap[205]
    DIRECTION INPUT ;
    USE SIGNAL ;
    PORT
      LAYER M4 ;
        RECT 457.728 456.864 457.920 456.888 ;
    END
  END tap[205]
  PIN tap[206]
    DIRECTION INPUT ;
    USE SIGNAL ;
    PORT
      LAYER M4 ;
        RECT 457.728 456.960 457.920 456.984 ;
    END
  END tap[206]
  PIN tap[207]
    DIRECTION INPUT ;
    USE SIGNAL ;
    PORT
      LAYER M4 ;
        RECT 457.728 457.056 457.920 457.080 ;
    END
  END tap[207]
  PIN tap[208]
    DIRECTION INPUT ;
    USE SIGNAL ;
    PORT
      LAYER M4 ;
        RECT 457.728 457.152 457.920 457.176 ;
    END
  END tap[208]
  PIN tap[209]
    DIRECTION INPUT ;
    USE SIGNAL ;
    PORT
      LAYER M4 ;
        RECT 457.728 457.248 457.920 457.272 ;
    END
  END tap[209]
  PIN tap[210]
    DIRECTION INPUT ;
    USE SIGNAL ;
    PORT
      LAYER M4 ;
        RECT 457.728 457.344 457.920 457.368 ;
    END
  END tap[210]
  PIN tap[211]
    DIRECTION INPUT ;
    USE SIGNAL ;
    PORT
      LAYER M4 ;
        RECT 457.728 457.440 457.920 457.464 ;
    END
  END tap[211]
  PIN tap[212]
    DIRECTION INPUT ;
    USE SIGNAL ;
    PORT
      LAYER M4 ;
        RECT 457.728 457.536 457.920 457.560 ;
    END
  END tap[212]
  PIN tap[213]
    DIRECTION INPUT ;
    USE SIGNAL ;
    PORT
      LAYER M4 ;
        RECT 457.728 457.632 457.920 457.656 ;
    END
  END tap[213]
  PIN tap[214]
    DIRECTION INPUT ;
    USE SIGNAL ;
    PORT
      LAYER M4 ;
        RECT 457.728 457.728 457.920 457.752 ;
    END
  END tap[214]
  PIN tap[215]
    DIRECTION INPUT ;
    USE SIGNAL ;
    PORT
      LAYER M4 ;
        RECT 457.728 457.824 457.920 457.848 ;
    END
  END tap[215]
  PIN tap[216]
    DIRECTION INPUT ;
    USE SIGNAL ;
    PORT
      LAYER M4 ;
        RECT 457.728 457.920 457.920 457.944 ;
    END
  END tap[216]
  PIN tap[217]
    DIRECTION INPUT ;
    USE SIGNAL ;
    PORT
      LAYER M4 ;
        RECT 457.728 458.016 457.920 458.040 ;
    END
  END tap[217]
  PIN tap[218]
    DIRECTION INPUT ;
    USE SIGNAL ;
    PORT
      LAYER M4 ;
        RECT 457.728 458.112 457.920 458.136 ;
    END
  END tap[218]
  PIN tap[219]
    DIRECTION INPUT ;
    USE SIGNAL ;
    PORT
      LAYER M4 ;
        RECT 457.728 458.208 457.920 458.232 ;
    END
  END tap[219]
  PIN tap[220]
    DIRECTION INPUT ;
    USE SIGNAL ;
    PORT
      LAYER M4 ;
        RECT 457.728 458.304 457.920 458.328 ;
    END
  END tap[220]
  PIN tap[221]
    DIRECTION INPUT ;
    USE SIGNAL ;
    PORT
      LAYER M4 ;
        RECT 457.728 458.400 457.920 458.424 ;
    END
  END tap[221]
  PIN tap[222]
    DIRECTION INPUT ;
    USE SIGNAL ;
    PORT
      LAYER M4 ;
        RECT 457.728 458.496 457.920 458.520 ;
    END
  END tap[222]
  PIN tap[223]
    DIRECTION INPUT ;
    USE SIGNAL ;
    PORT
      LAYER M4 ;
        RECT 457.728 458.592 457.920 458.616 ;
    END
  END tap[223]
  PIN tap[224]
    DIRECTION INPUT ;
    USE SIGNAL ;
    PORT
      LAYER M4 ;
        RECT 457.728 458.688 457.920 458.712 ;
    END
  END tap[224]
  PIN tap[225]
    DIRECTION INPUT ;
    USE SIGNAL ;
    PORT
      LAYER M4 ;
        RECT 457.728 458.784 457.920 458.808 ;
    END
  END tap[225]
  PIN tap[226]
    DIRECTION INPUT ;
    USE SIGNAL ;
    PORT
      LAYER M4 ;
        RECT 457.728 458.880 457.920 458.904 ;
    END
  END tap[226]
  PIN tap[227]
    DIRECTION INPUT ;
    USE SIGNAL ;
    PORT
      LAYER M4 ;
        RECT 457.728 458.976 457.920 459.000 ;
    END
  END tap[227]
  PIN tap[228]
    DIRECTION INPUT ;
    USE SIGNAL ;
    PORT
      LAYER M4 ;
        RECT 457.728 459.072 457.920 459.096 ;
    END
  END tap[228]
  PIN tap[229]
    DIRECTION INPUT ;
    USE SIGNAL ;
    PORT
      LAYER M4 ;
        RECT 457.728 459.168 457.920 459.192 ;
    END
  END tap[229]
  PIN tap[230]
    DIRECTION INPUT ;
    USE SIGNAL ;
    PORT
      LAYER M4 ;
        RECT 457.728 459.264 457.920 459.288 ;
    END
  END tap[230]
  PIN tap[231]
    DIRECTION INPUT ;
    USE SIGNAL ;
    PORT
      LAYER M4 ;
        RECT 457.728 459.360 457.920 459.384 ;
    END
  END tap[231]
  PIN tap[232]
    DIRECTION INPUT ;
    USE SIGNAL ;
    PORT
      LAYER M4 ;
        RECT 457.728 459.456 457.920 459.480 ;
    END
  END tap[232]
  PIN tap[233]
    DIRECTION INPUT ;
    USE SIGNAL ;
    PORT
      LAYER M4 ;
        RECT 457.728 459.552 457.920 459.576 ;
    END
  END tap[233]
  PIN tap[234]
    DIRECTION INPUT ;
    USE SIGNAL ;
    PORT
      LAYER M4 ;
        RECT 457.728 459.648 457.920 459.672 ;
    END
  END tap[234]
  PIN tap[235]
    DIRECTION INPUT ;
    USE SIGNAL ;
    PORT
      LAYER M4 ;
        RECT 457.728 459.744 457.920 459.768 ;
    END
  END tap[235]
  PIN tap[236]
    DIRECTION INPUT ;
    USE SIGNAL ;
    PORT
      LAYER M4 ;
        RECT 457.728 459.840 457.920 459.864 ;
    END
  END tap[236]
  PIN tap[237]
    DIRECTION INPUT ;
    USE SIGNAL ;
    PORT
      LAYER M4 ;
        RECT 457.728 459.936 457.920 459.960 ;
    END
  END tap[237]
  PIN tap[238]
    DIRECTION INPUT ;
    USE SIGNAL ;
    PORT
      LAYER M4 ;
        RECT 457.728 460.032 457.920 460.056 ;
    END
  END tap[238]
  PIN tap[239]
    DIRECTION INPUT ;
    USE SIGNAL ;
    PORT
      LAYER M4 ;
        RECT 457.728 460.128 457.920 460.152 ;
    END
  END tap[239]
  PIN tap[240]
    DIRECTION INPUT ;
    USE SIGNAL ;
    PORT
      LAYER M4 ;
        RECT 457.728 460.224 457.920 460.248 ;
    END
  END tap[240]
  PIN tap[241]
    DIRECTION INPUT ;
    USE SIGNAL ;
    PORT
      LAYER M4 ;
        RECT 457.728 460.320 457.920 460.344 ;
    END
  END tap[241]
  PIN tap[242]
    DIRECTION INPUT ;
    USE SIGNAL ;
    PORT
      LAYER M4 ;
        RECT 457.728 460.416 457.920 460.440 ;
    END
  END tap[242]
  PIN tap[243]
    DIRECTION INPUT ;
    USE SIGNAL ;
    PORT
      LAYER M4 ;
        RECT 457.728 460.512 457.920 460.536 ;
    END
  END tap[243]
  PIN tap[244]
    DIRECTION INPUT ;
    USE SIGNAL ;
    PORT
      LAYER M4 ;
        RECT 457.728 460.608 457.920 460.632 ;
    END
  END tap[244]
  PIN tap[245]
    DIRECTION INPUT ;
    USE SIGNAL ;
    PORT
      LAYER M4 ;
        RECT 457.728 460.704 457.920 460.728 ;
    END
  END tap[245]
  PIN tap[246]
    DIRECTION INPUT ;
    USE SIGNAL ;
    PORT
      LAYER M4 ;
        RECT 457.728 460.800 457.920 460.824 ;
    END
  END tap[246]
  PIN tap[247]
    DIRECTION INPUT ;
    USE SIGNAL ;
    PORT
      LAYER M4 ;
        RECT 457.728 460.896 457.920 460.920 ;
    END
  END tap[247]
  PIN tap[248]
    DIRECTION INPUT ;
    USE SIGNAL ;
    PORT
      LAYER M4 ;
        RECT 457.728 460.992 457.920 461.016 ;
    END
  END tap[248]
  PIN tap[249]
    DIRECTION INPUT ;
    USE SIGNAL ;
    PORT
      LAYER M4 ;
        RECT 457.728 461.088 457.920 461.112 ;
    END
  END tap[249]
  PIN tap[250]
    DIRECTION INPUT ;
    USE SIGNAL ;
    PORT
      LAYER M4 ;
        RECT 457.728 461.184 457.920 461.208 ;
    END
  END tap[250]
  PIN tap[251]
    DIRECTION INPUT ;
    USE SIGNAL ;
    PORT
      LAYER M4 ;
        RECT 457.728 461.280 457.920 461.304 ;
    END
  END tap[251]
  PIN tap[252]
    DIRECTION INPUT ;
    USE SIGNAL ;
    PORT
      LAYER M4 ;
        RECT 457.728 461.376 457.920 461.400 ;
    END
  END tap[252]
  PIN tap[253]
    DIRECTION INPUT ;
    USE SIGNAL ;
    PORT
      LAYER M4 ;
        RECT 457.728 461.472 457.920 461.496 ;
    END
  END tap[253]
  PIN tap[254]
    DIRECTION INPUT ;
    USE SIGNAL ;
    PORT
      LAYER M4 ;
        RECT 457.728 461.568 457.920 461.592 ;
    END
  END tap[254]
  PIN tap[255]
    DIRECTION INPUT ;
    USE SIGNAL ;
    PORT
      LAYER M4 ;
        RECT 457.728 461.664 457.920 461.688 ;
    END
  END tap[255]
  PIN tap[256]
    DIRECTION INPUT ;
    USE SIGNAL ;
    PORT
      LAYER M4 ;
        RECT 457.728 461.760 457.920 461.784 ;
    END
  END tap[256]
  PIN tap[257]
    DIRECTION INPUT ;
    USE SIGNAL ;
    PORT
      LAYER M4 ;
        RECT 457.728 461.856 457.920 461.880 ;
    END
  END tap[257]
  PIN tap[258]
    DIRECTION INPUT ;
    USE SIGNAL ;
    PORT
      LAYER M4 ;
        RECT 457.728 461.952 457.920 461.976 ;
    END
  END tap[258]
  PIN tap[259]
    DIRECTION INPUT ;
    USE SIGNAL ;
    PORT
      LAYER M4 ;
        RECT 457.728 462.048 457.920 462.072 ;
    END
  END tap[259]
  PIN tap[260]
    DIRECTION INPUT ;
    USE SIGNAL ;
    PORT
      LAYER M4 ;
        RECT 457.728 462.144 457.920 462.168 ;
    END
  END tap[260]
  PIN tap[261]
    DIRECTION INPUT ;
    USE SIGNAL ;
    PORT
      LAYER M4 ;
        RECT 457.728 462.240 457.920 462.264 ;
    END
  END tap[261]
  PIN tap[262]
    DIRECTION INPUT ;
    USE SIGNAL ;
    PORT
      LAYER M4 ;
        RECT 457.728 462.336 457.920 462.360 ;
    END
  END tap[262]
  PIN tap[263]
    DIRECTION INPUT ;
    USE SIGNAL ;
    PORT
      LAYER M4 ;
        RECT 457.728 462.432 457.920 462.456 ;
    END
  END tap[263]
  PIN tap[264]
    DIRECTION INPUT ;
    USE SIGNAL ;
    PORT
      LAYER M4 ;
        RECT 457.728 462.528 457.920 462.552 ;
    END
  END tap[264]
  PIN tap[265]
    DIRECTION INPUT ;
    USE SIGNAL ;
    PORT
      LAYER M4 ;
        RECT 457.728 462.624 457.920 462.648 ;
    END
  END tap[265]
  PIN tap[266]
    DIRECTION INPUT ;
    USE SIGNAL ;
    PORT
      LAYER M4 ;
        RECT 457.728 462.720 457.920 462.744 ;
    END
  END tap[266]
  PIN tap[267]
    DIRECTION INPUT ;
    USE SIGNAL ;
    PORT
      LAYER M4 ;
        RECT 457.728 462.816 457.920 462.840 ;
    END
  END tap[267]
  PIN tap[268]
    DIRECTION INPUT ;
    USE SIGNAL ;
    PORT
      LAYER M4 ;
        RECT 457.728 462.912 457.920 462.936 ;
    END
  END tap[268]
  PIN tap[269]
    DIRECTION INPUT ;
    USE SIGNAL ;
    PORT
      LAYER M4 ;
        RECT 457.728 463.008 457.920 463.032 ;
    END
  END tap[269]
  PIN tap[270]
    DIRECTION INPUT ;
    USE SIGNAL ;
    PORT
      LAYER M4 ;
        RECT 457.728 463.104 457.920 463.128 ;
    END
  END tap[270]
  PIN tap[271]
    DIRECTION INPUT ;
    USE SIGNAL ;
    PORT
      LAYER M4 ;
        RECT 457.728 463.200 457.920 463.224 ;
    END
  END tap[271]
  PIN tap[272]
    DIRECTION INPUT ;
    USE SIGNAL ;
    PORT
      LAYER M4 ;
        RECT 457.728 463.296 457.920 463.320 ;
    END
  END tap[272]
  PIN tap[273]
    DIRECTION INPUT ;
    USE SIGNAL ;
    PORT
      LAYER M4 ;
        RECT 457.728 463.392 457.920 463.416 ;
    END
  END tap[273]
  PIN tap[274]
    DIRECTION INPUT ;
    USE SIGNAL ;
    PORT
      LAYER M4 ;
        RECT 457.728 463.488 457.920 463.512 ;
    END
  END tap[274]
  PIN tap[275]
    DIRECTION INPUT ;
    USE SIGNAL ;
    PORT
      LAYER M4 ;
        RECT 457.728 463.584 457.920 463.608 ;
    END
  END tap[275]
  PIN tap[276]
    DIRECTION INPUT ;
    USE SIGNAL ;
    PORT
      LAYER M4 ;
        RECT 457.728 463.680 457.920 463.704 ;
    END
  END tap[276]
  PIN tap[277]
    DIRECTION INPUT ;
    USE SIGNAL ;
    PORT
      LAYER M4 ;
        RECT 457.728 463.776 457.920 463.800 ;
    END
  END tap[277]
  PIN tap[278]
    DIRECTION INPUT ;
    USE SIGNAL ;
    PORT
      LAYER M4 ;
        RECT 457.728 463.872 457.920 463.896 ;
    END
  END tap[278]
  PIN tap[279]
    DIRECTION INPUT ;
    USE SIGNAL ;
    PORT
      LAYER M4 ;
        RECT 457.728 463.968 457.920 463.992 ;
    END
  END tap[279]
  PIN tap[280]
    DIRECTION INPUT ;
    USE SIGNAL ;
    PORT
      LAYER M4 ;
        RECT 457.728 464.064 457.920 464.088 ;
    END
  END tap[280]
  PIN tap[281]
    DIRECTION INPUT ;
    USE SIGNAL ;
    PORT
      LAYER M4 ;
        RECT 457.728 464.160 457.920 464.184 ;
    END
  END tap[281]
  PIN tap[282]
    DIRECTION INPUT ;
    USE SIGNAL ;
    PORT
      LAYER M4 ;
        RECT 457.728 464.256 457.920 464.280 ;
    END
  END tap[282]
  PIN tap[283]
    DIRECTION INPUT ;
    USE SIGNAL ;
    PORT
      LAYER M4 ;
        RECT 457.728 464.352 457.920 464.376 ;
    END
  END tap[283]
  PIN tap[284]
    DIRECTION INPUT ;
    USE SIGNAL ;
    PORT
      LAYER M4 ;
        RECT 457.728 464.448 457.920 464.472 ;
    END
  END tap[284]
  PIN tap[285]
    DIRECTION INPUT ;
    USE SIGNAL ;
    PORT
      LAYER M4 ;
        RECT 457.728 464.544 457.920 464.568 ;
    END
  END tap[285]
  PIN tap[286]
    DIRECTION INPUT ;
    USE SIGNAL ;
    PORT
      LAYER M4 ;
        RECT 457.728 464.640 457.920 464.664 ;
    END
  END tap[286]
  PIN tap[287]
    DIRECTION INPUT ;
    USE SIGNAL ;
    PORT
      LAYER M4 ;
        RECT 457.728 464.736 457.920 464.760 ;
    END
  END tap[287]
  PIN tap[288]
    DIRECTION INPUT ;
    USE SIGNAL ;
    PORT
      LAYER M4 ;
        RECT 457.728 464.832 457.920 464.856 ;
    END
  END tap[288]
  PIN tap[289]
    DIRECTION INPUT ;
    USE SIGNAL ;
    PORT
      LAYER M4 ;
        RECT 457.728 464.928 457.920 464.952 ;
    END
  END tap[289]
  PIN tap[290]
    DIRECTION INPUT ;
    USE SIGNAL ;
    PORT
      LAYER M4 ;
        RECT 457.728 465.024 457.920 465.048 ;
    END
  END tap[290]
  PIN tap[291]
    DIRECTION INPUT ;
    USE SIGNAL ;
    PORT
      LAYER M4 ;
        RECT 457.728 465.120 457.920 465.144 ;
    END
  END tap[291]
  PIN tap[292]
    DIRECTION INPUT ;
    USE SIGNAL ;
    PORT
      LAYER M4 ;
        RECT 457.728 465.216 457.920 465.240 ;
    END
  END tap[292]
  PIN tap[293]
    DIRECTION INPUT ;
    USE SIGNAL ;
    PORT
      LAYER M4 ;
        RECT 457.728 465.312 457.920 465.336 ;
    END
  END tap[293]
  PIN tap[294]
    DIRECTION INPUT ;
    USE SIGNAL ;
    PORT
      LAYER M4 ;
        RECT 457.728 465.408 457.920 465.432 ;
    END
  END tap[294]
  PIN tap[295]
    DIRECTION INPUT ;
    USE SIGNAL ;
    PORT
      LAYER M4 ;
        RECT 457.728 465.504 457.920 465.528 ;
    END
  END tap[295]
  PIN tap[296]
    DIRECTION INPUT ;
    USE SIGNAL ;
    PORT
      LAYER M4 ;
        RECT 457.728 465.600 457.920 465.624 ;
    END
  END tap[296]
  PIN tap[297]
    DIRECTION INPUT ;
    USE SIGNAL ;
    PORT
      LAYER M4 ;
        RECT 457.728 465.696 457.920 465.720 ;
    END
  END tap[297]
  PIN tap[298]
    DIRECTION INPUT ;
    USE SIGNAL ;
    PORT
      LAYER M4 ;
        RECT 457.728 465.792 457.920 465.816 ;
    END
  END tap[298]
  PIN tap[299]
    DIRECTION INPUT ;
    USE SIGNAL ;
    PORT
      LAYER M4 ;
        RECT 457.728 465.888 457.920 465.912 ;
    END
  END tap[299]
  PIN tap[300]
    DIRECTION INPUT ;
    USE SIGNAL ;
    PORT
      LAYER M4 ;
        RECT 457.728 465.984 457.920 466.008 ;
    END
  END tap[300]
  PIN tap[301]
    DIRECTION INPUT ;
    USE SIGNAL ;
    PORT
      LAYER M4 ;
        RECT 457.728 466.080 457.920 466.104 ;
    END
  END tap[301]
  PIN tap[302]
    DIRECTION INPUT ;
    USE SIGNAL ;
    PORT
      LAYER M4 ;
        RECT 457.728 466.176 457.920 466.200 ;
    END
  END tap[302]
  PIN tap[303]
    DIRECTION INPUT ;
    USE SIGNAL ;
    PORT
      LAYER M4 ;
        RECT 457.728 466.272 457.920 466.296 ;
    END
  END tap[303]
  PIN tap[304]
    DIRECTION INPUT ;
    USE SIGNAL ;
    PORT
      LAYER M4 ;
        RECT 457.728 466.368 457.920 466.392 ;
    END
  END tap[304]
  PIN tap[305]
    DIRECTION INPUT ;
    USE SIGNAL ;
    PORT
      LAYER M4 ;
        RECT 457.728 466.464 457.920 466.488 ;
    END
  END tap[305]
  PIN tap[306]
    DIRECTION INPUT ;
    USE SIGNAL ;
    PORT
      LAYER M4 ;
        RECT 457.728 466.560 457.920 466.584 ;
    END
  END tap[306]
  PIN tap[307]
    DIRECTION INPUT ;
    USE SIGNAL ;
    PORT
      LAYER M4 ;
        RECT 457.728 466.656 457.920 466.680 ;
    END
  END tap[307]
  PIN tap[308]
    DIRECTION INPUT ;
    USE SIGNAL ;
    PORT
      LAYER M4 ;
        RECT 457.728 466.752 457.920 466.776 ;
    END
  END tap[308]
  PIN tap[309]
    DIRECTION INPUT ;
    USE SIGNAL ;
    PORT
      LAYER M4 ;
        RECT 457.728 466.848 457.920 466.872 ;
    END
  END tap[309]
  PIN tap[310]
    DIRECTION INPUT ;
    USE SIGNAL ;
    PORT
      LAYER M4 ;
        RECT 457.728 466.944 457.920 466.968 ;
    END
  END tap[310]
  PIN tap[311]
    DIRECTION INPUT ;
    USE SIGNAL ;
    PORT
      LAYER M4 ;
        RECT 457.728 467.040 457.920 467.064 ;
    END
  END tap[311]
  PIN tap[312]
    DIRECTION INPUT ;
    USE SIGNAL ;
    PORT
      LAYER M4 ;
        RECT 457.728 467.136 457.920 467.160 ;
    END
  END tap[312]
  PIN tap[313]
    DIRECTION INPUT ;
    USE SIGNAL ;
    PORT
      LAYER M4 ;
        RECT 457.728 467.232 457.920 467.256 ;
    END
  END tap[313]
  PIN tap[314]
    DIRECTION INPUT ;
    USE SIGNAL ;
    PORT
      LAYER M4 ;
        RECT 457.728 467.328 457.920 467.352 ;
    END
  END tap[314]
  PIN tap[315]
    DIRECTION INPUT ;
    USE SIGNAL ;
    PORT
      LAYER M4 ;
        RECT 457.728 467.424 457.920 467.448 ;
    END
  END tap[315]
  PIN tap[316]
    DIRECTION INPUT ;
    USE SIGNAL ;
    PORT
      LAYER M4 ;
        RECT 457.728 467.520 457.920 467.544 ;
    END
  END tap[316]
  PIN tap[317]
    DIRECTION INPUT ;
    USE SIGNAL ;
    PORT
      LAYER M4 ;
        RECT 457.728 467.616 457.920 467.640 ;
    END
  END tap[317]
  PIN tap[318]
    DIRECTION INPUT ;
    USE SIGNAL ;
    PORT
      LAYER M4 ;
        RECT 457.728 467.712 457.920 467.736 ;
    END
  END tap[318]
  PIN tap[319]
    DIRECTION INPUT ;
    USE SIGNAL ;
    PORT
      LAYER M4 ;
        RECT 457.728 467.808 457.920 467.832 ;
    END
  END tap[319]
  PIN tap[320]
    DIRECTION INPUT ;
    USE SIGNAL ;
    PORT
      LAYER M4 ;
        RECT 457.728 467.904 457.920 467.928 ;
    END
  END tap[320]
  PIN tap[321]
    DIRECTION INPUT ;
    USE SIGNAL ;
    PORT
      LAYER M4 ;
        RECT 457.728 468.000 457.920 468.024 ;
    END
  END tap[321]
  PIN tap[322]
    DIRECTION INPUT ;
    USE SIGNAL ;
    PORT
      LAYER M4 ;
        RECT 457.728 468.096 457.920 468.120 ;
    END
  END tap[322]
  PIN tap[323]
    DIRECTION INPUT ;
    USE SIGNAL ;
    PORT
      LAYER M4 ;
        RECT 457.728 468.192 457.920 468.216 ;
    END
  END tap[323]
  PIN tap[324]
    DIRECTION INPUT ;
    USE SIGNAL ;
    PORT
      LAYER M4 ;
        RECT 457.728 468.288 457.920 468.312 ;
    END
  END tap[324]
  PIN tap[325]
    DIRECTION INPUT ;
    USE SIGNAL ;
    PORT
      LAYER M4 ;
        RECT 457.728 468.384 457.920 468.408 ;
    END
  END tap[325]
  PIN tap[326]
    DIRECTION INPUT ;
    USE SIGNAL ;
    PORT
      LAYER M4 ;
        RECT 457.728 468.480 457.920 468.504 ;
    END
  END tap[326]
  PIN tap[327]
    DIRECTION INPUT ;
    USE SIGNAL ;
    PORT
      LAYER M4 ;
        RECT 457.728 468.576 457.920 468.600 ;
    END
  END tap[327]
  PIN tap[328]
    DIRECTION INPUT ;
    USE SIGNAL ;
    PORT
      LAYER M4 ;
        RECT 457.728 468.672 457.920 468.696 ;
    END
  END tap[328]
  PIN tap[329]
    DIRECTION INPUT ;
    USE SIGNAL ;
    PORT
      LAYER M4 ;
        RECT 457.728 468.768 457.920 468.792 ;
    END
  END tap[329]
  PIN tap[330]
    DIRECTION INPUT ;
    USE SIGNAL ;
    PORT
      LAYER M4 ;
        RECT 457.728 468.864 457.920 468.888 ;
    END
  END tap[330]
  PIN tap[331]
    DIRECTION INPUT ;
    USE SIGNAL ;
    PORT
      LAYER M4 ;
        RECT 457.728 468.960 457.920 468.984 ;
    END
  END tap[331]
  PIN tap[332]
    DIRECTION INPUT ;
    USE SIGNAL ;
    PORT
      LAYER M4 ;
        RECT 457.728 469.056 457.920 469.080 ;
    END
  END tap[332]
  PIN tap[333]
    DIRECTION INPUT ;
    USE SIGNAL ;
    PORT
      LAYER M4 ;
        RECT 457.728 469.152 457.920 469.176 ;
    END
  END tap[333]
  PIN tap[334]
    DIRECTION INPUT ;
    USE SIGNAL ;
    PORT
      LAYER M4 ;
        RECT 457.728 469.248 457.920 469.272 ;
    END
  END tap[334]
  PIN tap[335]
    DIRECTION INPUT ;
    USE SIGNAL ;
    PORT
      LAYER M4 ;
        RECT 457.728 469.344 457.920 469.368 ;
    END
  END tap[335]
  PIN tap[336]
    DIRECTION INPUT ;
    USE SIGNAL ;
    PORT
      LAYER M4 ;
        RECT 457.728 469.440 457.920 469.464 ;
    END
  END tap[336]
  PIN tap[337]
    DIRECTION INPUT ;
    USE SIGNAL ;
    PORT
      LAYER M4 ;
        RECT 457.728 469.536 457.920 469.560 ;
    END
  END tap[337]
  PIN tap[338]
    DIRECTION INPUT ;
    USE SIGNAL ;
    PORT
      LAYER M4 ;
        RECT 457.728 469.632 457.920 469.656 ;
    END
  END tap[338]
  PIN tap[339]
    DIRECTION INPUT ;
    USE SIGNAL ;
    PORT
      LAYER M4 ;
        RECT 457.728 469.728 457.920 469.752 ;
    END
  END tap[339]
  PIN tap[340]
    DIRECTION INPUT ;
    USE SIGNAL ;
    PORT
      LAYER M4 ;
        RECT 457.728 469.824 457.920 469.848 ;
    END
  END tap[340]
  PIN tap[341]
    DIRECTION INPUT ;
    USE SIGNAL ;
    PORT
      LAYER M4 ;
        RECT 457.728 469.920 457.920 469.944 ;
    END
  END tap[341]
  PIN tap[342]
    DIRECTION INPUT ;
    USE SIGNAL ;
    PORT
      LAYER M4 ;
        RECT 457.728 470.016 457.920 470.040 ;
    END
  END tap[342]
  PIN tap[343]
    DIRECTION INPUT ;
    USE SIGNAL ;
    PORT
      LAYER M4 ;
        RECT 457.728 470.112 457.920 470.136 ;
    END
  END tap[343]
  PIN tap[344]
    DIRECTION INPUT ;
    USE SIGNAL ;
    PORT
      LAYER M4 ;
        RECT 457.728 470.208 457.920 470.232 ;
    END
  END tap[344]
  PIN tap[345]
    DIRECTION INPUT ;
    USE SIGNAL ;
    PORT
      LAYER M4 ;
        RECT 457.728 470.304 457.920 470.328 ;
    END
  END tap[345]
  PIN tap[346]
    DIRECTION INPUT ;
    USE SIGNAL ;
    PORT
      LAYER M4 ;
        RECT 457.728 470.400 457.920 470.424 ;
    END
  END tap[346]
  PIN tap[347]
    DIRECTION INPUT ;
    USE SIGNAL ;
    PORT
      LAYER M4 ;
        RECT 457.728 470.496 457.920 470.520 ;
    END
  END tap[347]
  PIN tap[348]
    DIRECTION INPUT ;
    USE SIGNAL ;
    PORT
      LAYER M4 ;
        RECT 457.728 470.592 457.920 470.616 ;
    END
  END tap[348]
  PIN tap[349]
    DIRECTION INPUT ;
    USE SIGNAL ;
    PORT
      LAYER M4 ;
        RECT 457.728 470.688 457.920 470.712 ;
    END
  END tap[349]
  PIN tap[350]
    DIRECTION INPUT ;
    USE SIGNAL ;
    PORT
      LAYER M4 ;
        RECT 457.728 470.784 457.920 470.808 ;
    END
  END tap[350]
  PIN tap[351]
    DIRECTION INPUT ;
    USE SIGNAL ;
    PORT
      LAYER M4 ;
        RECT 457.728 470.880 457.920 470.904 ;
    END
  END tap[351]
  PIN tap[352]
    DIRECTION INPUT ;
    USE SIGNAL ;
    PORT
      LAYER M4 ;
        RECT 457.728 470.976 457.920 471.000 ;
    END
  END tap[352]
  PIN tap[353]
    DIRECTION INPUT ;
    USE SIGNAL ;
    PORT
      LAYER M4 ;
        RECT 457.728 471.072 457.920 471.096 ;
    END
  END tap[353]
  PIN tap[354]
    DIRECTION INPUT ;
    USE SIGNAL ;
    PORT
      LAYER M4 ;
        RECT 457.728 471.168 457.920 471.192 ;
    END
  END tap[354]
  PIN tap[355]
    DIRECTION INPUT ;
    USE SIGNAL ;
    PORT
      LAYER M4 ;
        RECT 457.728 471.264 457.920 471.288 ;
    END
  END tap[355]
  PIN tap[356]
    DIRECTION INPUT ;
    USE SIGNAL ;
    PORT
      LAYER M4 ;
        RECT 457.728 471.360 457.920 471.384 ;
    END
  END tap[356]
  PIN tap[357]
    DIRECTION INPUT ;
    USE SIGNAL ;
    PORT
      LAYER M4 ;
        RECT 457.728 471.456 457.920 471.480 ;
    END
  END tap[357]
  PIN tap[358]
    DIRECTION INPUT ;
    USE SIGNAL ;
    PORT
      LAYER M4 ;
        RECT 457.728 471.552 457.920 471.576 ;
    END
  END tap[358]
  PIN tap[359]
    DIRECTION INPUT ;
    USE SIGNAL ;
    PORT
      LAYER M4 ;
        RECT 457.728 471.648 457.920 471.672 ;
    END
  END tap[359]
  PIN tap[360]
    DIRECTION INPUT ;
    USE SIGNAL ;
    PORT
      LAYER M4 ;
        RECT 457.728 471.744 457.920 471.768 ;
    END
  END tap[360]
  PIN tap[361]
    DIRECTION INPUT ;
    USE SIGNAL ;
    PORT
      LAYER M4 ;
        RECT 457.728 471.840 457.920 471.864 ;
    END
  END tap[361]
  PIN tap[362]
    DIRECTION INPUT ;
    USE SIGNAL ;
    PORT
      LAYER M4 ;
        RECT 457.728 471.936 457.920 471.960 ;
    END
  END tap[362]
  PIN tap[363]
    DIRECTION INPUT ;
    USE SIGNAL ;
    PORT
      LAYER M4 ;
        RECT 457.728 472.032 457.920 472.056 ;
    END
  END tap[363]
  PIN tap[364]
    DIRECTION INPUT ;
    USE SIGNAL ;
    PORT
      LAYER M4 ;
        RECT 457.728 472.128 457.920 472.152 ;
    END
  END tap[364]
  PIN tap[365]
    DIRECTION INPUT ;
    USE SIGNAL ;
    PORT
      LAYER M4 ;
        RECT 457.728 472.224 457.920 472.248 ;
    END
  END tap[365]
  PIN tap[366]
    DIRECTION INPUT ;
    USE SIGNAL ;
    PORT
      LAYER M4 ;
        RECT 457.728 472.320 457.920 472.344 ;
    END
  END tap[366]
  PIN tap[367]
    DIRECTION INPUT ;
    USE SIGNAL ;
    PORT
      LAYER M4 ;
        RECT 457.728 472.416 457.920 472.440 ;
    END
  END tap[367]
  PIN tap[368]
    DIRECTION INPUT ;
    USE SIGNAL ;
    PORT
      LAYER M4 ;
        RECT 457.728 472.512 457.920 472.536 ;
    END
  END tap[368]
  PIN tap[369]
    DIRECTION INPUT ;
    USE SIGNAL ;
    PORT
      LAYER M4 ;
        RECT 457.728 472.608 457.920 472.632 ;
    END
  END tap[369]
  PIN tap[370]
    DIRECTION INPUT ;
    USE SIGNAL ;
    PORT
      LAYER M4 ;
        RECT 457.728 472.704 457.920 472.728 ;
    END
  END tap[370]
  PIN tap[371]
    DIRECTION INPUT ;
    USE SIGNAL ;
    PORT
      LAYER M4 ;
        RECT 457.728 472.800 457.920 472.824 ;
    END
  END tap[371]
  PIN tap[372]
    DIRECTION INPUT ;
    USE SIGNAL ;
    PORT
      LAYER M4 ;
        RECT 457.728 472.896 457.920 472.920 ;
    END
  END tap[372]
  PIN tap[373]
    DIRECTION INPUT ;
    USE SIGNAL ;
    PORT
      LAYER M4 ;
        RECT 457.728 472.992 457.920 473.016 ;
    END
  END tap[373]
  PIN tap[374]
    DIRECTION INPUT ;
    USE SIGNAL ;
    PORT
      LAYER M4 ;
        RECT 457.728 473.088 457.920 473.112 ;
    END
  END tap[374]
  PIN tap[375]
    DIRECTION INPUT ;
    USE SIGNAL ;
    PORT
      LAYER M4 ;
        RECT 457.728 473.184 457.920 473.208 ;
    END
  END tap[375]
  PIN tap[376]
    DIRECTION INPUT ;
    USE SIGNAL ;
    PORT
      LAYER M4 ;
        RECT 457.728 473.280 457.920 473.304 ;
    END
  END tap[376]
  PIN tap[377]
    DIRECTION INPUT ;
    USE SIGNAL ;
    PORT
      LAYER M4 ;
        RECT 457.728 473.376 457.920 473.400 ;
    END
  END tap[377]
  PIN tap[378]
    DIRECTION INPUT ;
    USE SIGNAL ;
    PORT
      LAYER M4 ;
        RECT 457.728 473.472 457.920 473.496 ;
    END
  END tap[378]
  PIN tap[379]
    DIRECTION INPUT ;
    USE SIGNAL ;
    PORT
      LAYER M4 ;
        RECT 457.728 473.568 457.920 473.592 ;
    END
  END tap[379]
  PIN tap[380]
    DIRECTION INPUT ;
    USE SIGNAL ;
    PORT
      LAYER M4 ;
        RECT 457.728 473.664 457.920 473.688 ;
    END
  END tap[380]
  PIN tap[381]
    DIRECTION INPUT ;
    USE SIGNAL ;
    PORT
      LAYER M4 ;
        RECT 457.728 473.760 457.920 473.784 ;
    END
  END tap[381]
  PIN tap[382]
    DIRECTION INPUT ;
    USE SIGNAL ;
    PORT
      LAYER M4 ;
        RECT 457.728 473.856 457.920 473.880 ;
    END
  END tap[382]
  PIN tap[383]
    DIRECTION INPUT ;
    USE SIGNAL ;
    PORT
      LAYER M4 ;
        RECT 457.728 473.952 457.920 473.976 ;
    END
  END tap[383]
  PIN tap[384]
    DIRECTION INPUT ;
    USE SIGNAL ;
    PORT
      LAYER M4 ;
        RECT 457.728 474.048 457.920 474.072 ;
    END
  END tap[384]
  PIN tap[385]
    DIRECTION INPUT ;
    USE SIGNAL ;
    PORT
      LAYER M4 ;
        RECT 457.728 474.144 457.920 474.168 ;
    END
  END tap[385]
  PIN tap[386]
    DIRECTION INPUT ;
    USE SIGNAL ;
    PORT
      LAYER M4 ;
        RECT 457.728 474.240 457.920 474.264 ;
    END
  END tap[386]
  PIN tap[387]
    DIRECTION INPUT ;
    USE SIGNAL ;
    PORT
      LAYER M4 ;
        RECT 457.728 474.336 457.920 474.360 ;
    END
  END tap[387]
  PIN tap[388]
    DIRECTION INPUT ;
    USE SIGNAL ;
    PORT
      LAYER M4 ;
        RECT 457.728 474.432 457.920 474.456 ;
    END
  END tap[388]
  PIN tap[389]
    DIRECTION INPUT ;
    USE SIGNAL ;
    PORT
      LAYER M4 ;
        RECT 457.728 474.528 457.920 474.552 ;
    END
  END tap[389]
  PIN tap[390]
    DIRECTION INPUT ;
    USE SIGNAL ;
    PORT
      LAYER M4 ;
        RECT 457.728 474.624 457.920 474.648 ;
    END
  END tap[390]
  PIN tap[391]
    DIRECTION INPUT ;
    USE SIGNAL ;
    PORT
      LAYER M4 ;
        RECT 457.728 474.720 457.920 474.744 ;
    END
  END tap[391]
  PIN tap[392]
    DIRECTION INPUT ;
    USE SIGNAL ;
    PORT
      LAYER M4 ;
        RECT 457.728 474.816 457.920 474.840 ;
    END
  END tap[392]
  PIN tap[393]
    DIRECTION INPUT ;
    USE SIGNAL ;
    PORT
      LAYER M4 ;
        RECT 457.728 474.912 457.920 474.936 ;
    END
  END tap[393]
  PIN tap[394]
    DIRECTION INPUT ;
    USE SIGNAL ;
    PORT
      LAYER M4 ;
        RECT 457.728 475.008 457.920 475.032 ;
    END
  END tap[394]
  PIN tap[395]
    DIRECTION INPUT ;
    USE SIGNAL ;
    PORT
      LAYER M4 ;
        RECT 457.728 475.104 457.920 475.128 ;
    END
  END tap[395]
  PIN tap[396]
    DIRECTION INPUT ;
    USE SIGNAL ;
    PORT
      LAYER M4 ;
        RECT 457.728 475.200 457.920 475.224 ;
    END
  END tap[396]
  PIN tap[397]
    DIRECTION INPUT ;
    USE SIGNAL ;
    PORT
      LAYER M4 ;
        RECT 457.728 475.296 457.920 475.320 ;
    END
  END tap[397]
  PIN tap[398]
    DIRECTION INPUT ;
    USE SIGNAL ;
    PORT
      LAYER M4 ;
        RECT 457.728 475.392 457.920 475.416 ;
    END
  END tap[398]
  PIN tap[399]
    DIRECTION INPUT ;
    USE SIGNAL ;
    PORT
      LAYER M4 ;
        RECT 457.728 475.488 457.920 475.512 ;
    END
  END tap[399]
  PIN tap[400]
    DIRECTION INPUT ;
    USE SIGNAL ;
    PORT
      LAYER M4 ;
        RECT 457.728 475.584 457.920 475.608 ;
    END
  END tap[400]
  PIN tap[401]
    DIRECTION INPUT ;
    USE SIGNAL ;
    PORT
      LAYER M4 ;
        RECT 457.728 475.680 457.920 475.704 ;
    END
  END tap[401]
  PIN tap[402]
    DIRECTION INPUT ;
    USE SIGNAL ;
    PORT
      LAYER M4 ;
        RECT 457.728 475.776 457.920 475.800 ;
    END
  END tap[402]
  PIN tap[403]
    DIRECTION INPUT ;
    USE SIGNAL ;
    PORT
      LAYER M4 ;
        RECT 457.728 475.872 457.920 475.896 ;
    END
  END tap[403]
  PIN tap[404]
    DIRECTION INPUT ;
    USE SIGNAL ;
    PORT
      LAYER M4 ;
        RECT 457.728 475.968 457.920 475.992 ;
    END
  END tap[404]
  PIN tap[405]
    DIRECTION INPUT ;
    USE SIGNAL ;
    PORT
      LAYER M4 ;
        RECT 457.728 476.064 457.920 476.088 ;
    END
  END tap[405]
  PIN tap[406]
    DIRECTION INPUT ;
    USE SIGNAL ;
    PORT
      LAYER M4 ;
        RECT 457.728 476.160 457.920 476.184 ;
    END
  END tap[406]
  PIN tap[407]
    DIRECTION INPUT ;
    USE SIGNAL ;
    PORT
      LAYER M4 ;
        RECT 457.728 476.256 457.920 476.280 ;
    END
  END tap[407]
  PIN tap[408]
    DIRECTION INPUT ;
    USE SIGNAL ;
    PORT
      LAYER M4 ;
        RECT 457.728 476.352 457.920 476.376 ;
    END
  END tap[408]
  PIN tap[409]
    DIRECTION INPUT ;
    USE SIGNAL ;
    PORT
      LAYER M4 ;
        RECT 457.728 476.448 457.920 476.472 ;
    END
  END tap[409]
  PIN tap[410]
    DIRECTION INPUT ;
    USE SIGNAL ;
    PORT
      LAYER M4 ;
        RECT 457.728 476.544 457.920 476.568 ;
    END
  END tap[410]
  PIN tap[411]
    DIRECTION INPUT ;
    USE SIGNAL ;
    PORT
      LAYER M4 ;
        RECT 457.728 476.640 457.920 476.664 ;
    END
  END tap[411]
  PIN tap[412]
    DIRECTION INPUT ;
    USE SIGNAL ;
    PORT
      LAYER M4 ;
        RECT 457.728 476.736 457.920 476.760 ;
    END
  END tap[412]
  PIN tap[413]
    DIRECTION INPUT ;
    USE SIGNAL ;
    PORT
      LAYER M4 ;
        RECT 457.728 476.832 457.920 476.856 ;
    END
  END tap[413]
  PIN tap[414]
    DIRECTION INPUT ;
    USE SIGNAL ;
    PORT
      LAYER M4 ;
        RECT 457.728 476.928 457.920 476.952 ;
    END
  END tap[414]
  PIN tap[415]
    DIRECTION INPUT ;
    USE SIGNAL ;
    PORT
      LAYER M4 ;
        RECT 457.728 477.024 457.920 477.048 ;
    END
  END tap[415]
  PIN tap[416]
    DIRECTION INPUT ;
    USE SIGNAL ;
    PORT
      LAYER M4 ;
        RECT 457.728 477.120 457.920 477.144 ;
    END
  END tap[416]
  PIN tap[417]
    DIRECTION INPUT ;
    USE SIGNAL ;
    PORT
      LAYER M4 ;
        RECT 457.728 477.216 457.920 477.240 ;
    END
  END tap[417]
  PIN tap[418]
    DIRECTION INPUT ;
    USE SIGNAL ;
    PORT
      LAYER M4 ;
        RECT 457.728 477.312 457.920 477.336 ;
    END
  END tap[418]
  PIN tap[419]
    DIRECTION INPUT ;
    USE SIGNAL ;
    PORT
      LAYER M4 ;
        RECT 457.728 477.408 457.920 477.432 ;
    END
  END tap[419]
  PIN tap[420]
    DIRECTION INPUT ;
    USE SIGNAL ;
    PORT
      LAYER M4 ;
        RECT 457.728 477.504 457.920 477.528 ;
    END
  END tap[420]
  PIN tap[421]
    DIRECTION INPUT ;
    USE SIGNAL ;
    PORT
      LAYER M4 ;
        RECT 457.728 477.600 457.920 477.624 ;
    END
  END tap[421]
  PIN tap[422]
    DIRECTION INPUT ;
    USE SIGNAL ;
    PORT
      LAYER M4 ;
        RECT 457.728 477.696 457.920 477.720 ;
    END
  END tap[422]
  PIN tap[423]
    DIRECTION INPUT ;
    USE SIGNAL ;
    PORT
      LAYER M4 ;
        RECT 457.728 477.792 457.920 477.816 ;
    END
  END tap[423]
  PIN tap[424]
    DIRECTION INPUT ;
    USE SIGNAL ;
    PORT
      LAYER M4 ;
        RECT 457.728 477.888 457.920 477.912 ;
    END
  END tap[424]
  PIN tap[425]
    DIRECTION INPUT ;
    USE SIGNAL ;
    PORT
      LAYER M4 ;
        RECT 457.728 477.984 457.920 478.008 ;
    END
  END tap[425]
  PIN tap[426]
    DIRECTION INPUT ;
    USE SIGNAL ;
    PORT
      LAYER M4 ;
        RECT 457.728 478.080 457.920 478.104 ;
    END
  END tap[426]
  PIN tap[427]
    DIRECTION INPUT ;
    USE SIGNAL ;
    PORT
      LAYER M4 ;
        RECT 457.728 478.176 457.920 478.200 ;
    END
  END tap[427]
  PIN tap[428]
    DIRECTION INPUT ;
    USE SIGNAL ;
    PORT
      LAYER M4 ;
        RECT 457.728 478.272 457.920 478.296 ;
    END
  END tap[428]
  PIN tap[429]
    DIRECTION INPUT ;
    USE SIGNAL ;
    PORT
      LAYER M4 ;
        RECT 457.728 478.368 457.920 478.392 ;
    END
  END tap[429]
  PIN tap[430]
    DIRECTION INPUT ;
    USE SIGNAL ;
    PORT
      LAYER M4 ;
        RECT 457.728 478.464 457.920 478.488 ;
    END
  END tap[430]
  PIN tap[431]
    DIRECTION INPUT ;
    USE SIGNAL ;
    PORT
      LAYER M4 ;
        RECT 457.728 478.560 457.920 478.584 ;
    END
  END tap[431]
  PIN tap[432]
    DIRECTION INPUT ;
    USE SIGNAL ;
    PORT
      LAYER M4 ;
        RECT 457.728 478.656 457.920 478.680 ;
    END
  END tap[432]
  PIN tap[433]
    DIRECTION INPUT ;
    USE SIGNAL ;
    PORT
      LAYER M4 ;
        RECT 457.728 478.752 457.920 478.776 ;
    END
  END tap[433]
  PIN tap[434]
    DIRECTION INPUT ;
    USE SIGNAL ;
    PORT
      LAYER M4 ;
        RECT 457.728 478.848 457.920 478.872 ;
    END
  END tap[434]
  PIN tap[435]
    DIRECTION INPUT ;
    USE SIGNAL ;
    PORT
      LAYER M4 ;
        RECT 457.728 478.944 457.920 478.968 ;
    END
  END tap[435]
  PIN tap[436]
    DIRECTION INPUT ;
    USE SIGNAL ;
    PORT
      LAYER M4 ;
        RECT 457.728 479.040 457.920 479.064 ;
    END
  END tap[436]
  PIN tap[437]
    DIRECTION INPUT ;
    USE SIGNAL ;
    PORT
      LAYER M4 ;
        RECT 457.728 479.136 457.920 479.160 ;
    END
  END tap[437]
  PIN tap[438]
    DIRECTION INPUT ;
    USE SIGNAL ;
    PORT
      LAYER M4 ;
        RECT 457.728 479.232 457.920 479.256 ;
    END
  END tap[438]
  PIN tap[439]
    DIRECTION INPUT ;
    USE SIGNAL ;
    PORT
      LAYER M4 ;
        RECT 457.728 479.328 457.920 479.352 ;
    END
  END tap[439]
  PIN tap[440]
    DIRECTION INPUT ;
    USE SIGNAL ;
    PORT
      LAYER M4 ;
        RECT 457.728 479.424 457.920 479.448 ;
    END
  END tap[440]
  PIN tap[441]
    DIRECTION INPUT ;
    USE SIGNAL ;
    PORT
      LAYER M4 ;
        RECT 457.728 479.520 457.920 479.544 ;
    END
  END tap[441]
  PIN tap[442]
    DIRECTION INPUT ;
    USE SIGNAL ;
    PORT
      LAYER M4 ;
        RECT 457.728 479.616 457.920 479.640 ;
    END
  END tap[442]
  PIN tap[443]
    DIRECTION INPUT ;
    USE SIGNAL ;
    PORT
      LAYER M4 ;
        RECT 457.728 479.712 457.920 479.736 ;
    END
  END tap[443]
  PIN tap[444]
    DIRECTION INPUT ;
    USE SIGNAL ;
    PORT
      LAYER M4 ;
        RECT 457.728 479.808 457.920 479.832 ;
    END
  END tap[444]
  PIN tap[445]
    DIRECTION INPUT ;
    USE SIGNAL ;
    PORT
      LAYER M4 ;
        RECT 457.728 479.904 457.920 479.928 ;
    END
  END tap[445]
  PIN tap[446]
    DIRECTION INPUT ;
    USE SIGNAL ;
    PORT
      LAYER M4 ;
        RECT 457.728 480.000 457.920 480.024 ;
    END
  END tap[446]
  PIN tap[447]
    DIRECTION INPUT ;
    USE SIGNAL ;
    PORT
      LAYER M4 ;
        RECT 457.728 480.096 457.920 480.120 ;
    END
  END tap[447]
  PIN tap[448]
    DIRECTION INPUT ;
    USE SIGNAL ;
    PORT
      LAYER M4 ;
        RECT 457.728 480.192 457.920 480.216 ;
    END
  END tap[448]
  PIN tap[449]
    DIRECTION INPUT ;
    USE SIGNAL ;
    PORT
      LAYER M4 ;
        RECT 457.728 480.288 457.920 480.312 ;
    END
  END tap[449]
  PIN tap[450]
    DIRECTION INPUT ;
    USE SIGNAL ;
    PORT
      LAYER M4 ;
        RECT 457.728 480.384 457.920 480.408 ;
    END
  END tap[450]
  PIN tap[451]
    DIRECTION INPUT ;
    USE SIGNAL ;
    PORT
      LAYER M4 ;
        RECT 457.728 480.480 457.920 480.504 ;
    END
  END tap[451]
  PIN tap[452]
    DIRECTION INPUT ;
    USE SIGNAL ;
    PORT
      LAYER M4 ;
        RECT 457.728 480.576 457.920 480.600 ;
    END
  END tap[452]
  PIN tap[453]
    DIRECTION INPUT ;
    USE SIGNAL ;
    PORT
      LAYER M4 ;
        RECT 457.728 480.672 457.920 480.696 ;
    END
  END tap[453]
  PIN tap[454]
    DIRECTION INPUT ;
    USE SIGNAL ;
    PORT
      LAYER M4 ;
        RECT 457.728 480.768 457.920 480.792 ;
    END
  END tap[454]
  PIN tap[455]
    DIRECTION INPUT ;
    USE SIGNAL ;
    PORT
      LAYER M4 ;
        RECT 457.728 480.864 457.920 480.888 ;
    END
  END tap[455]
  PIN tap[456]
    DIRECTION INPUT ;
    USE SIGNAL ;
    PORT
      LAYER M4 ;
        RECT 457.728 480.960 457.920 480.984 ;
    END
  END tap[456]
  PIN tap[457]
    DIRECTION INPUT ;
    USE SIGNAL ;
    PORT
      LAYER M4 ;
        RECT 457.728 481.056 457.920 481.080 ;
    END
  END tap[457]
  PIN tap[458]
    DIRECTION INPUT ;
    USE SIGNAL ;
    PORT
      LAYER M4 ;
        RECT 457.728 481.152 457.920 481.176 ;
    END
  END tap[458]
  PIN tap[459]
    DIRECTION INPUT ;
    USE SIGNAL ;
    PORT
      LAYER M4 ;
        RECT 457.728 481.248 457.920 481.272 ;
    END
  END tap[459]
  PIN tap[460]
    DIRECTION INPUT ;
    USE SIGNAL ;
    PORT
      LAYER M4 ;
        RECT 457.728 481.344 457.920 481.368 ;
    END
  END tap[460]
  PIN tap[461]
    DIRECTION INPUT ;
    USE SIGNAL ;
    PORT
      LAYER M4 ;
        RECT 457.728 481.440 457.920 481.464 ;
    END
  END tap[461]
  PIN tap[462]
    DIRECTION INPUT ;
    USE SIGNAL ;
    PORT
      LAYER M4 ;
        RECT 457.728 481.536 457.920 481.560 ;
    END
  END tap[462]
  PIN tap[463]
    DIRECTION INPUT ;
    USE SIGNAL ;
    PORT
      LAYER M4 ;
        RECT 457.728 481.632 457.920 481.656 ;
    END
  END tap[463]
  PIN tap[464]
    DIRECTION INPUT ;
    USE SIGNAL ;
    PORT
      LAYER M4 ;
        RECT 457.728 481.728 457.920 481.752 ;
    END
  END tap[464]
  PIN tap[465]
    DIRECTION INPUT ;
    USE SIGNAL ;
    PORT
      LAYER M4 ;
        RECT 457.728 481.824 457.920 481.848 ;
    END
  END tap[465]
  PIN tap[466]
    DIRECTION INPUT ;
    USE SIGNAL ;
    PORT
      LAYER M4 ;
        RECT 457.728 481.920 457.920 481.944 ;
    END
  END tap[466]
  PIN tap[467]
    DIRECTION INPUT ;
    USE SIGNAL ;
    PORT
      LAYER M4 ;
        RECT 457.728 482.016 457.920 482.040 ;
    END
  END tap[467]
  PIN tap[468]
    DIRECTION INPUT ;
    USE SIGNAL ;
    PORT
      LAYER M4 ;
        RECT 457.728 482.112 457.920 482.136 ;
    END
  END tap[468]
  PIN tap[469]
    DIRECTION INPUT ;
    USE SIGNAL ;
    PORT
      LAYER M4 ;
        RECT 457.728 482.208 457.920 482.232 ;
    END
  END tap[469]
  PIN tap[470]
    DIRECTION INPUT ;
    USE SIGNAL ;
    PORT
      LAYER M4 ;
        RECT 457.728 482.304 457.920 482.328 ;
    END
  END tap[470]
  PIN tap[471]
    DIRECTION INPUT ;
    USE SIGNAL ;
    PORT
      LAYER M4 ;
        RECT 457.728 482.400 457.920 482.424 ;
    END
  END tap[471]
  PIN tap[472]
    DIRECTION INPUT ;
    USE SIGNAL ;
    PORT
      LAYER M4 ;
        RECT 457.728 482.496 457.920 482.520 ;
    END
  END tap[472]
  PIN tap[473]
    DIRECTION INPUT ;
    USE SIGNAL ;
    PORT
      LAYER M4 ;
        RECT 457.728 482.592 457.920 482.616 ;
    END
  END tap[473]
  PIN tap[474]
    DIRECTION INPUT ;
    USE SIGNAL ;
    PORT
      LAYER M4 ;
        RECT 457.728 482.688 457.920 482.712 ;
    END
  END tap[474]
  PIN tap[475]
    DIRECTION INPUT ;
    USE SIGNAL ;
    PORT
      LAYER M4 ;
        RECT 457.728 482.784 457.920 482.808 ;
    END
  END tap[475]
  PIN tap[476]
    DIRECTION INPUT ;
    USE SIGNAL ;
    PORT
      LAYER M4 ;
        RECT 457.728 482.880 457.920 482.904 ;
    END
  END tap[476]
  PIN tap[477]
    DIRECTION INPUT ;
    USE SIGNAL ;
    PORT
      LAYER M4 ;
        RECT 457.728 482.976 457.920 483.000 ;
    END
  END tap[477]
  PIN tap[478]
    DIRECTION INPUT ;
    USE SIGNAL ;
    PORT
      LAYER M4 ;
        RECT 457.728 483.072 457.920 483.096 ;
    END
  END tap[478]
  PIN tap[479]
    DIRECTION INPUT ;
    USE SIGNAL ;
    PORT
      LAYER M4 ;
        RECT 457.728 483.168 457.920 483.192 ;
    END
  END tap[479]
  PIN tap[480]
    DIRECTION INPUT ;
    USE SIGNAL ;
    PORT
      LAYER M4 ;
        RECT 457.728 483.264 457.920 483.288 ;
    END
  END tap[480]
  PIN tap[481]
    DIRECTION INPUT ;
    USE SIGNAL ;
    PORT
      LAYER M4 ;
        RECT 457.728 483.360 457.920 483.384 ;
    END
  END tap[481]
  PIN tap[482]
    DIRECTION INPUT ;
    USE SIGNAL ;
    PORT
      LAYER M4 ;
        RECT 457.728 483.456 457.920 483.480 ;
    END
  END tap[482]
  PIN tap[483]
    DIRECTION INPUT ;
    USE SIGNAL ;
    PORT
      LAYER M4 ;
        RECT 457.728 483.552 457.920 483.576 ;
    END
  END tap[483]
  PIN tap[484]
    DIRECTION INPUT ;
    USE SIGNAL ;
    PORT
      LAYER M4 ;
        RECT 457.728 483.648 457.920 483.672 ;
    END
  END tap[484]
  PIN tap[485]
    DIRECTION INPUT ;
    USE SIGNAL ;
    PORT
      LAYER M4 ;
        RECT 457.728 483.744 457.920 483.768 ;
    END
  END tap[485]
  PIN tap[486]
    DIRECTION INPUT ;
    USE SIGNAL ;
    PORT
      LAYER M4 ;
        RECT 457.728 483.840 457.920 483.864 ;
    END
  END tap[486]
  PIN tap[487]
    DIRECTION INPUT ;
    USE SIGNAL ;
    PORT
      LAYER M4 ;
        RECT 457.728 483.936 457.920 483.960 ;
    END
  END tap[487]
  PIN tap[488]
    DIRECTION INPUT ;
    USE SIGNAL ;
    PORT
      LAYER M4 ;
        RECT 457.728 484.032 457.920 484.056 ;
    END
  END tap[488]
  PIN tap[489]
    DIRECTION INPUT ;
    USE SIGNAL ;
    PORT
      LAYER M4 ;
        RECT 457.728 484.128 457.920 484.152 ;
    END
  END tap[489]
  PIN tap[490]
    DIRECTION INPUT ;
    USE SIGNAL ;
    PORT
      LAYER M4 ;
        RECT 457.728 484.224 457.920 484.248 ;
    END
  END tap[490]
  PIN tap[491]
    DIRECTION INPUT ;
    USE SIGNAL ;
    PORT
      LAYER M4 ;
        RECT 457.728 484.320 457.920 484.344 ;
    END
  END tap[491]
  PIN tap[492]
    DIRECTION INPUT ;
    USE SIGNAL ;
    PORT
      LAYER M4 ;
        RECT 457.728 484.416 457.920 484.440 ;
    END
  END tap[492]
  PIN tap[493]
    DIRECTION INPUT ;
    USE SIGNAL ;
    PORT
      LAYER M4 ;
        RECT 457.728 484.512 457.920 484.536 ;
    END
  END tap[493]
  PIN tap[494]
    DIRECTION INPUT ;
    USE SIGNAL ;
    PORT
      LAYER M4 ;
        RECT 457.728 484.608 457.920 484.632 ;
    END
  END tap[494]
  PIN tap[495]
    DIRECTION INPUT ;
    USE SIGNAL ;
    PORT
      LAYER M4 ;
        RECT 457.728 484.704 457.920 484.728 ;
    END
  END tap[495]
  PIN tap[496]
    DIRECTION INPUT ;
    USE SIGNAL ;
    PORT
      LAYER M4 ;
        RECT 457.728 484.800 457.920 484.824 ;
    END
  END tap[496]
  PIN tap[497]
    DIRECTION INPUT ;
    USE SIGNAL ;
    PORT
      LAYER M4 ;
        RECT 457.728 484.896 457.920 484.920 ;
    END
  END tap[497]
  PIN tap[498]
    DIRECTION INPUT ;
    USE SIGNAL ;
    PORT
      LAYER M4 ;
        RECT 457.728 484.992 457.920 485.016 ;
    END
  END tap[498]
  PIN tap[499]
    DIRECTION INPUT ;
    USE SIGNAL ;
    PORT
      LAYER M4 ;
        RECT 457.728 485.088 457.920 485.112 ;
    END
  END tap[499]
  PIN tap[500]
    DIRECTION INPUT ;
    USE SIGNAL ;
    PORT
      LAYER M4 ;
        RECT 457.728 485.184 457.920 485.208 ;
    END
  END tap[500]
  PIN tap[501]
    DIRECTION INPUT ;
    USE SIGNAL ;
    PORT
      LAYER M4 ;
        RECT 457.728 485.280 457.920 485.304 ;
    END
  END tap[501]
  PIN tap[502]
    DIRECTION INPUT ;
    USE SIGNAL ;
    PORT
      LAYER M4 ;
        RECT 457.728 485.376 457.920 485.400 ;
    END
  END tap[502]
  PIN tap[503]
    DIRECTION INPUT ;
    USE SIGNAL ;
    PORT
      LAYER M4 ;
        RECT 457.728 485.472 457.920 485.496 ;
    END
  END tap[503]
  PIN tap[504]
    DIRECTION INPUT ;
    USE SIGNAL ;
    PORT
      LAYER M4 ;
        RECT 457.728 485.568 457.920 485.592 ;
    END
  END tap[504]
  PIN tap[505]
    DIRECTION INPUT ;
    USE SIGNAL ;
    PORT
      LAYER M4 ;
        RECT 457.728 485.664 457.920 485.688 ;
    END
  END tap[505]
  PIN tap[506]
    DIRECTION INPUT ;
    USE SIGNAL ;
    PORT
      LAYER M4 ;
        RECT 457.728 485.760 457.920 485.784 ;
    END
  END tap[506]
  PIN tap[507]
    DIRECTION INPUT ;
    USE SIGNAL ;
    PORT
      LAYER M4 ;
        RECT 457.728 485.856 457.920 485.880 ;
    END
  END tap[507]
  PIN ck_lsl0
    DIRECTION INPUT ;
    USE CLOCK ;
    PORT
      LAYER M4 ;
        RECT 0.000 430.176 0.192 430.200 ;
    END
  END ck_lsl0
  PIN ck_lsl1
    DIRECTION INPUT ;
    USE CLOCK ;
    PORT
      LAYER M4 ;
        RECT 0.000 259.488 0.192 259.512 ;
    END
  END ck_lsl1
  PIN ck_lsl2
    DIRECTION INPUT ;
    USE CLOCK ;
    PORT
      LAYER M4 ;
        RECT 0.000 88.992 0.192 89.016 ;
    END
  END ck_lsl2
  PIN ck_lsl3
    DIRECTION INPUT ;
    USE CLOCK ;
    PORT
      LAYER M4 ;
        RECT 457.728 430.176 457.920 430.200 ;
    END
  END ck_lsl3
  PIN ck_lsl4
    DIRECTION INPUT ;
    USE CLOCK ;
    PORT
      LAYER M4 ;
        RECT 457.728 259.536 457.920 259.560 ;
    END
  END ck_lsl4
  PIN ck_lsl5
    DIRECTION INPUT ;
    USE CLOCK ;
    PORT
      LAYER M4 ;
        RECT 457.728 88.896 457.920 88.920 ;
    END
  END ck_lsl5
  PIN ck_lsl6
    DIRECTION INPUT ;
    USE CLOCK ;
    PORT
      LAYER M4 ;
        RECT 457.728 259.632 457.920 259.656 ;
    END
  END ck_lsl6
  PIN ck_lsl7
    DIRECTION INPUT ;
    USE CLOCK ;
    PORT
      LAYER M4 ;
        RECT 457.728 88.992 457.920 89.016 ;
    END
  END ck_lsl7
  PIN ck_fa2
    DIRECTION INPUT ;
    USE CLOCK ;
    PORT
      LAYER M4 ;
        RECT 0.000 312.384 0.192 312.408 ;
    END
  END ck_fa2
  PIN ck_fa4
    DIRECTION INPUT ;
    USE CLOCK ;
    PORT
      LAYER M4 ;
        RECT 457.728 487.872 457.920 487.896 ;
    END
  END ck_fa4
  PIN ck
    DIRECTION INPUT ;
    USE CLOCK ;
    PORT
      LAYER M4 ;
        RECT 457.728 424.992 457.920 425.016 ;
    END
  END ck
  PIN ck_rp0
    DIRECTION INPUT ;
    USE CLOCK ;
    PORT
      LAYER M4 ;
        RECT 0.000 533.232 0.192 533.256 ;
    END
  END ck_rp0
  PIN ck_rp5
    DIRECTION INPUT ;
    USE CLOCK ;
    PORT
      LAYER M4 ;
        RECT 457.728 533.232 457.920 533.256 ;
    END
  END ck_rp5
  PIN ck_rp1
    DIRECTION INPUT ;
    USE CLOCK ;
    PORT
      LAYER M4 ;
        RECT 0.000 663.696 0.192 663.720 ;
    END
  END ck_rp1
  PIN ck_rp6
    DIRECTION INPUT ;
    USE CLOCK ;
    PORT
      LAYER M4 ;
        RECT 457.728 663.696 457.920 663.720 ;
    END
  END ck_rp6
  PIN ck_rp2
    DIRECTION INPUT ;
    USE CLOCK ;
    PORT
      LAYER M4 ;
        RECT 0.000 794.160 0.192 794.184 ;
    END
  END ck_rp2
  PIN ck_rp7
    DIRECTION INPUT ;
    USE CLOCK ;
    PORT
      LAYER M4 ;
        RECT 457.728 794.160 457.920 794.184 ;
    END
  END ck_rp7
  PIN ck_rp3
    DIRECTION INPUT ;
    USE CLOCK ;
    PORT
      LAYER M4 ;
        RECT 0.000 924.624 0.192 924.648 ;
    END
  END ck_rp3
  PIN ck_rp8
    DIRECTION INPUT ;
    USE CLOCK ;
    PORT
      LAYER M4 ;
        RECT 457.728 924.624 457.920 924.648 ;
    END
  END ck_rp8
  PIN ck_rp4
    DIRECTION INPUT ;
    USE CLOCK ;
    PORT
      LAYER M4 ;
        RECT 0.000 1055.088 0.192 1055.112 ;
    END
  END ck_rp4
  PIN ck_rp9
    DIRECTION INPUT ;
    USE CLOCK ;
    PORT
      LAYER M4 ;
        RECT 457.728 1055.088 457.920 1055.112 ;
    END
  END ck_rp9
  PIN ck_tx0
    DIRECTION INPUT ;
    USE CLOCK ;
    PORT
      LAYER M4 ;
        RECT 0.000 421.008 0.192 421.032 ;
    END
  END ck_tx0
  PIN ck_tx1
    DIRECTION INPUT ;
    USE CLOCK ;
    PORT
      LAYER M4 ;
        RECT 0.000 249.984 0.192 250.008 ;
    END
  END ck_tx1
  PIN ck_tx2
    DIRECTION INPUT ;
    USE CLOCK ;
    PORT
      LAYER M4 ;
        RECT 0.000 96.000 0.192 96.024 ;
    END
  END ck_tx2
  PIN ck_tx3
    DIRECTION INPUT ;
    USE CLOCK ;
    PORT
      LAYER M4 ;
        RECT 457.728 399.984 457.920 400.008 ;
    END
  END ck_tx3
  PIN ck_tx6
    DIRECTION INPUT ;
    USE CLOCK ;
    PORT
      LAYER M4 ;
        RECT 457.728 249.984 457.920 250.008 ;
    END
  END ck_tx6
  PIN ck_tx7
    DIRECTION INPUT ;
    USE CLOCK ;
    PORT
      LAYER M4 ;
        RECT 457.728 99.984 457.920 100.008 ;
    END
  END ck_tx7
  PIN ck_rsw
    DIRECTION INPUT ;
    USE CLOCK ;
    PORT
      LAYER M4 ;
        RECT 0.000 679.968 0.192 679.992 ;
    END
  END ck_rsw
  PIN ck_rnw
    DIRECTION INPUT ;
    USE CLOCK ;
    PORT
      LAYER M4 ;
        RECT 0.000 870.000 0.192 870.024 ;
    END
  END ck_rnw
  PIN ck_dw
    DIRECTION INPUT ;
    USE CLOCK ;
    PORT
      LAYER M4 ;
        RECT 0.000 547.968 0.192 547.992 ;
    END
  END ck_dw
  PIN ck_de
    DIRECTION INPUT ;
    USE CLOCK ;
    PORT
      LAYER M4 ;
        RECT 457.728 547.968 457.920 547.992 ;
    END
  END ck_de
  PIN ck_rs
    DIRECTION INPUT ;
    USE CLOCK ;
    PORT
      LAYER M4 ;
        RECT 457.728 679.968 457.920 679.992 ;
    END
  END ck_rs
  PIN ck_rn
    DIRECTION INPUT ;
    USE CLOCK ;
    PORT
      LAYER M4 ;
        RECT 457.728 870.000 457.920 870.024 ;
    END
  END ck_rn
  PIN ck_tx5
    DIRECTION INPUT ;
    USE CLOCK ;
    PORT
      LAYER M5 ;
        RECT 314.400 0.000 314.424 0.192 ;
    END
  END ck_tx5
  PIN ck_tx4
    DIRECTION INPUT ;
    USE CLOCK ;
    PORT
      LAYER M5 ;
        RECT 315.360 0.000 315.384 0.192 ;
    END
  END ck_tx4
  OBS
    LAYER M1 ;
      RECT 0.000 0.000 457.920 1166.400 ;
    LAYER M2 ;
      RECT 0.000 0.000 457.920 1166.400 ;
    LAYER M3 ;
      RECT 0.000 0.000 457.920 1166.400 ;
    LAYER M4 ;
      RECT 0.000 0.000 457.920 1166.400 ;
    LAYER M5 ;
      RECT 0.000 0.000 457.920 1166.400 ;
    LAYER M6 ;
      RECT 0.000 0.000 457.920 1166.400 ;
    LAYER M7 ;
      RECT 0.000 0.000 457.920 1166.400 ;
  END
END qfd_tile_nl_rp2_romleaf_rr
END LIBRARY
